VERSION 5.8 ;
BUSBITCHARS "[]" ;
DIVIDERCHAR "/" ;
UNITS
    DATABASE MICRONS 1000 ;
END UNITS

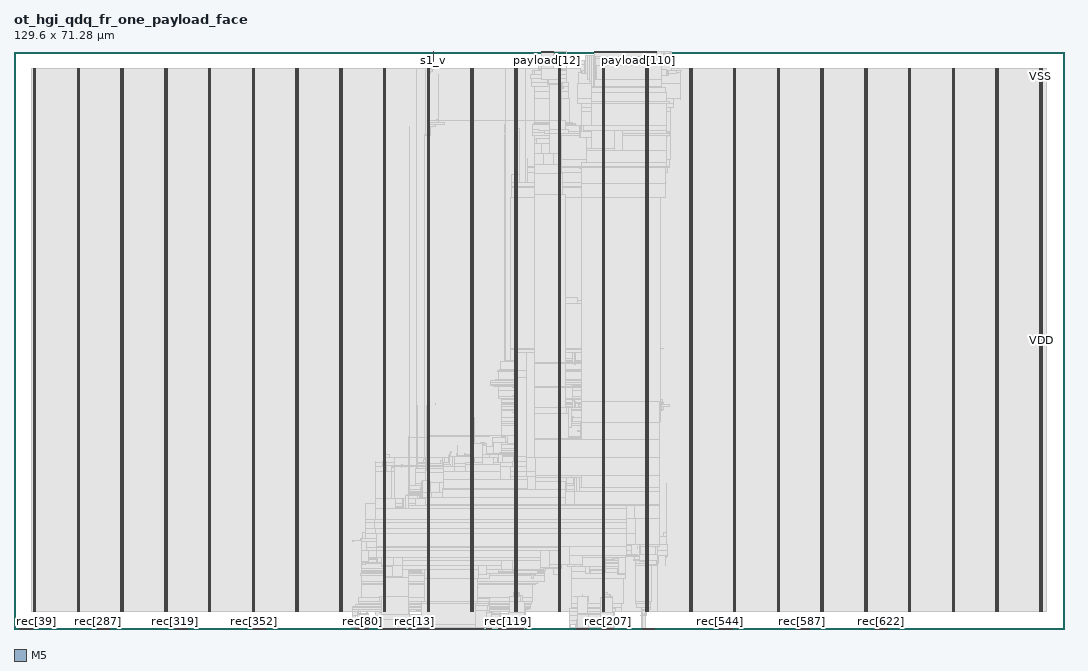
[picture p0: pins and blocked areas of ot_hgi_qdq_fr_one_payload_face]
MACRO ot_hgi_qdq_fr_one_payload_face
  FOREIGN ot_hgi_qdq_fr_one_payload_face 0 0 ;
  CLASS BLOCK ;
  SIZE 129.6 BY 71.28 ;
  PIN clk
    DIRECTION INPUT ;
    USE SIGNAL ;
    PORT
      LAYER M5 ;
        RECT  48.72 0 48.744 0.084 ;
    END
  END clk
  PIN nfault
    DIRECTION OUTPUT ;
    USE SIGNAL ;
    PORT
      LAYER M5 ;
        RECT  65.136 71.196 65.16 71.28 ;
    END
  END nfault
  PIN one_s1
    DIRECTION OUTPUT ;
    USE SIGNAL ;
    PORT
      LAYER M5 ;
        RECT  65.184 71.196 65.208 71.28 ;
    END
  END one_s1
  PIN payload[0]
    DIRECTION OUTPUT ;
    USE SIGNAL ;
    PORT
      LAYER M5 ;
        RECT  65.232 71.196 65.256 71.28 ;
    END
  END payload[0]
  PIN payload[100]
    DIRECTION OUTPUT ;
    USE SIGNAL ;
    PORT
      LAYER M5 ;
        RECT  76.56 71.196 76.584 71.28 ;
    END
  END payload[100]
  PIN payload[101]
    DIRECTION OUTPUT ;
    USE SIGNAL ;
    PORT
      LAYER M5 ;
        RECT  76.608 71.196 76.632 71.28 ;
    END
  END payload[101]
  PIN payload[102]
    DIRECTION OUTPUT ;
    USE SIGNAL ;
    PORT
      LAYER M5 ;
        RECT  76.656 71.196 76.68 71.28 ;
    END
  END payload[102]
  PIN payload[103]
    DIRECTION OUTPUT ;
    USE SIGNAL ;
    PORT
      LAYER M5 ;
        RECT  76.704 71.196 76.728 71.28 ;
    END
  END payload[103]
  PIN payload[104]
    DIRECTION OUTPUT ;
    USE SIGNAL ;
    PORT
      LAYER M5 ;
        RECT  76.752 71.196 76.776 71.28 ;
    END
  END payload[104]
  PIN payload[105]
    DIRECTION OUTPUT ;
    USE SIGNAL ;
    PORT
      LAYER M5 ;
        RECT  76.8 71.196 76.824 71.28 ;
    END
  END payload[105]
  PIN payload[106]
    DIRECTION OUTPUT ;
    USE SIGNAL ;
    PORT
      LAYER M5 ;
        RECT  76.848 71.196 76.872 71.28 ;
    END
  END payload[106]
  PIN payload[107]
    DIRECTION OUTPUT ;
    USE SIGNAL ;
    PORT
      LAYER M5 ;
        RECT  76.896 71.196 76.92 71.28 ;
    END
  END payload[107]
  PIN payload[108]
    DIRECTION OUTPUT ;
    USE SIGNAL ;
    PORT
      LAYER M5 ;
        RECT  76.944 71.196 76.968 71.28 ;
    END
  END payload[108]
  PIN payload[109]
    DIRECTION OUTPUT ;
    USE SIGNAL ;
    PORT
      LAYER M5 ;
        RECT  76.992 71.196 77.016 71.28 ;
    END
  END payload[109]
  PIN payload[10]
    DIRECTION OUTPUT ;
    USE SIGNAL ;
    PORT
      LAYER M5 ;
        RECT  65.712 71.196 65.736 71.28 ;
    END
  END payload[10]
  PIN payload[110]
    DIRECTION OUTPUT ;
    USE SIGNAL ;
    PORT
      LAYER M5 ;
        RECT  77.04 71.196 77.064 71.28 ;
    END
  END payload[110]
  PIN payload[111]
    DIRECTION OUTPUT ;
    USE SIGNAL ;
    PORT
      LAYER M5 ;
        RECT  77.088 71.196 77.112 71.28 ;
    END
  END payload[111]
  PIN payload[112]
    DIRECTION OUTPUT ;
    USE SIGNAL ;
    PORT
      LAYER M5 ;
        RECT  77.136 71.196 77.16 71.28 ;
    END
  END payload[112]
  PIN payload[113]
    DIRECTION OUTPUT ;
    USE SIGNAL ;
    PORT
      LAYER M5 ;
        RECT  77.184 71.196 77.208 71.28 ;
    END
  END payload[113]
  PIN payload[114]
    DIRECTION OUTPUT ;
    USE SIGNAL ;
    PORT
      LAYER M5 ;
        RECT  77.232 71.196 77.256 71.28 ;
    END
  END payload[114]
  PIN payload[115]
    DIRECTION OUTPUT ;
    USE SIGNAL ;
    PORT
      LAYER M5 ;
        RECT  77.28 71.196 77.304 71.28 ;
    END
  END payload[115]
  PIN payload[116]
    DIRECTION OUTPUT ;
    USE SIGNAL ;
    PORT
      LAYER M5 ;
        RECT  77.328 71.196 77.352 71.28 ;
    END
  END payload[116]
  PIN payload[117]
    DIRECTION OUTPUT ;
    USE SIGNAL ;
    PORT
      LAYER M5 ;
        RECT  77.376 71.196 77.4 71.28 ;
    END
  END payload[117]
  PIN payload[118]
    DIRECTION OUTPUT ;
    USE SIGNAL ;
    PORT
      LAYER M5 ;
        RECT  77.424 71.196 77.448 71.28 ;
    END
  END payload[118]
  PIN payload[119]
    DIRECTION OUTPUT ;
    USE SIGNAL ;
    PORT
      LAYER M5 ;
        RECT  77.472 71.196 77.496 71.28 ;
    END
  END payload[119]
  PIN payload[11]
    DIRECTION OUTPUT ;
    USE SIGNAL ;
    PORT
      LAYER M5 ;
        RECT  65.76 71.196 65.784 71.28 ;
    END
  END payload[11]
  PIN payload[120]
    DIRECTION OUTPUT ;
    USE SIGNAL ;
    PORT
      LAYER M5 ;
        RECT  77.52 71.196 77.544 71.28 ;
    END
  END payload[120]
  PIN payload[121]
    DIRECTION OUTPUT ;
    USE SIGNAL ;
    PORT
      LAYER M5 ;
        RECT  77.568 71.196 77.592 71.28 ;
    END
  END payload[121]
  PIN payload[122]
    DIRECTION OUTPUT ;
    USE SIGNAL ;
    PORT
      LAYER M5 ;
        RECT  77.616 71.196 77.64 71.28 ;
    END
  END payload[122]
  PIN payload[123]
    DIRECTION OUTPUT ;
    USE SIGNAL ;
    PORT
      LAYER M5 ;
        RECT  77.664 71.196 77.688 71.28 ;
    END
  END payload[123]
  PIN payload[124]
    DIRECTION OUTPUT ;
    USE SIGNAL ;
    PORT
      LAYER M5 ;
        RECT  77.712 71.196 77.736 71.28 ;
    END
  END payload[124]
  PIN payload[125]
    DIRECTION OUTPUT ;
    USE SIGNAL ;
    PORT
      LAYER M5 ;
        RECT  77.76 71.196 77.784 71.28 ;
    END
  END payload[125]
  PIN payload[126]
    DIRECTION OUTPUT ;
    USE SIGNAL ;
    PORT
      LAYER M5 ;
        RECT  74.736 71.196 74.76 71.28 ;
    END
  END payload[126]
  PIN payload[127]
    DIRECTION OUTPUT ;
    USE SIGNAL ;
    PORT
      LAYER M5 ;
        RECT  74.784 71.196 74.808 71.28 ;
    END
  END payload[127]
  PIN payload[128]
    DIRECTION OUTPUT ;
    USE SIGNAL ;
    PORT
      LAYER M5 ;
        RECT  74.832 71.196 74.856 71.28 ;
    END
  END payload[128]
  PIN payload[129]
    DIRECTION OUTPUT ;
    USE SIGNAL ;
    PORT
      LAYER M5 ;
        RECT  74.88 71.196 74.904 71.28 ;
    END
  END payload[129]
  PIN payload[12]
    DIRECTION OUTPUT ;
    USE SIGNAL ;
    PORT
      LAYER M5 ;
        RECT  65.808 71.196 65.832 71.28 ;
    END
  END payload[12]
  PIN payload[130]
    DIRECTION OUTPUT ;
    USE SIGNAL ;
    PORT
      LAYER M5 ;
        RECT  74.928 71.196 74.952 71.28 ;
    END
  END payload[130]
  PIN payload[131]
    DIRECTION OUTPUT ;
    USE SIGNAL ;
    PORT
      LAYER M5 ;
        RECT  74.976 71.196 75 71.28 ;
    END
  END payload[131]
  PIN payload[132]
    DIRECTION OUTPUT ;
    USE SIGNAL ;
    PORT
      LAYER M5 ;
        RECT  75.024 71.196 75.048 71.28 ;
    END
  END payload[132]
  PIN payload[133]
    DIRECTION OUTPUT ;
    USE SIGNAL ;
    PORT
      LAYER M5 ;
        RECT  75.072 71.196 75.096 71.28 ;
    END
  END payload[133]
  PIN payload[134]
    DIRECTION OUTPUT ;
    USE SIGNAL ;
    PORT
      LAYER M5 ;
        RECT  75.12 71.196 75.144 71.28 ;
    END
  END payload[134]
  PIN payload[135]
    DIRECTION OUTPUT ;
    USE SIGNAL ;
    PORT
      LAYER M5 ;
        RECT  75.168 71.196 75.192 71.28 ;
    END
  END payload[135]
  PIN payload[136]
    DIRECTION OUTPUT ;
    USE SIGNAL ;
    PORT
      LAYER M5 ;
        RECT  75.216 71.196 75.24 71.28 ;
    END
  END payload[136]
  PIN payload[137]
    DIRECTION OUTPUT ;
    USE SIGNAL ;
    PORT
      LAYER M5 ;
        RECT  75.264 71.196 75.288 71.28 ;
    END
  END payload[137]
  PIN payload[138]
    DIRECTION OUTPUT ;
    USE SIGNAL ;
    PORT
      LAYER M5 ;
        RECT  75.312 71.196 75.336 71.28 ;
    END
  END payload[138]
  PIN payload[139]
    DIRECTION OUTPUT ;
    USE SIGNAL ;
    PORT
      LAYER M5 ;
        RECT  75.36 71.196 75.384 71.28 ;
    END
  END payload[139]
  PIN payload[13]
    DIRECTION OUTPUT ;
    USE SIGNAL ;
    PORT
      LAYER M5 ;
        RECT  65.856 71.196 65.88 71.28 ;
    END
  END payload[13]
  PIN payload[140]
    DIRECTION OUTPUT ;
    USE SIGNAL ;
    PORT
      LAYER M5 ;
        RECT  75.408 71.196 75.432 71.28 ;
    END
  END payload[140]
  PIN payload[141]
    DIRECTION OUTPUT ;
    USE SIGNAL ;
    PORT
      LAYER M5 ;
        RECT  75.456 71.196 75.48 71.28 ;
    END
  END payload[141]
  PIN payload[142]
    DIRECTION OUTPUT ;
    USE SIGNAL ;
    PORT
      LAYER M5 ;
        RECT  75.504 71.196 75.528 71.28 ;
    END
  END payload[142]
  PIN payload[143]
    DIRECTION OUTPUT ;
    USE SIGNAL ;
    PORT
      LAYER M5 ;
        RECT  75.552 71.196 75.576 71.28 ;
    END
  END payload[143]
  PIN payload[144]
    DIRECTION OUTPUT ;
    USE SIGNAL ;
    PORT
      LAYER M5 ;
        RECT  75.6 71.196 75.624 71.28 ;
    END
  END payload[144]
  PIN payload[145]
    DIRECTION OUTPUT ;
    USE SIGNAL ;
    PORT
      LAYER M5 ;
        RECT  75.648 71.196 75.672 71.28 ;
    END
  END payload[145]
  PIN payload[146]
    DIRECTION OUTPUT ;
    USE SIGNAL ;
    PORT
      LAYER M5 ;
        RECT  75.696 71.196 75.72 71.28 ;
    END
  END payload[146]
  PIN payload[147]
    DIRECTION OUTPUT ;
    USE SIGNAL ;
    PORT
      LAYER M5 ;
        RECT  75.744 71.196 75.768 71.28 ;
    END
  END payload[147]
  PIN payload[148]
    DIRECTION OUTPUT ;
    USE SIGNAL ;
    PORT
      LAYER M5 ;
        RECT  75.792 71.196 75.816 71.28 ;
    END
  END payload[148]
  PIN payload[149]
    DIRECTION OUTPUT ;
    USE SIGNAL ;
    PORT
      LAYER M5 ;
        RECT  75.84 71.196 75.864 71.28 ;
    END
  END payload[149]
  PIN payload[14]
    DIRECTION OUTPUT ;
    USE SIGNAL ;
    PORT
      LAYER M5 ;
        RECT  65.904 71.196 65.928 71.28 ;
    END
  END payload[14]
  PIN payload[150]
    DIRECTION OUTPUT ;
    USE SIGNAL ;
    PORT
      LAYER M5 ;
        RECT  75.888 71.196 75.912 71.28 ;
    END
  END payload[150]
  PIN payload[151]
    DIRECTION OUTPUT ;
    USE SIGNAL ;
    PORT
      LAYER M5 ;
        RECT  75.936 71.196 75.96 71.28 ;
    END
  END payload[151]
  PIN payload[152]
    DIRECTION OUTPUT ;
    USE SIGNAL ;
    PORT
      LAYER M5 ;
        RECT  75.984 71.196 76.008 71.28 ;
    END
  END payload[152]
  PIN payload[153]
    DIRECTION OUTPUT ;
    USE SIGNAL ;
    PORT
      LAYER M5 ;
        RECT  76.032 71.196 76.056 71.28 ;
    END
  END payload[153]
  PIN payload[154]
    DIRECTION OUTPUT ;
    USE SIGNAL ;
    PORT
      LAYER M5 ;
        RECT  76.08 71.196 76.104 71.28 ;
    END
  END payload[154]
  PIN payload[155]
    DIRECTION OUTPUT ;
    USE SIGNAL ;
    PORT
      LAYER M5 ;
        RECT  76.128 71.196 76.152 71.28 ;
    END
  END payload[155]
  PIN payload[156]
    DIRECTION OUTPUT ;
    USE SIGNAL ;
    PORT
      LAYER M5 ;
        RECT  76.176 71.196 76.2 71.28 ;
    END
  END payload[156]
  PIN payload[157]
    DIRECTION OUTPUT ;
    USE SIGNAL ;
    PORT
      LAYER M5 ;
        RECT  76.224 71.196 76.248 71.28 ;
    END
  END payload[157]
  PIN payload[158]
    DIRECTION OUTPUT ;
    USE SIGNAL ;
    PORT
      LAYER M5 ;
        RECT  77.808 71.196 77.832 71.28 ;
    END
  END payload[158]
  PIN payload[159]
    DIRECTION OUTPUT ;
    USE SIGNAL ;
    PORT
      LAYER M5 ;
        RECT  77.856 71.196 77.88 71.28 ;
    END
  END payload[159]
  PIN payload[15]
    DIRECTION OUTPUT ;
    USE SIGNAL ;
    PORT
      LAYER M5 ;
        RECT  65.952 71.196 65.976 71.28 ;
    END
  END payload[15]
  PIN payload[160]
    DIRECTION OUTPUT ;
    USE SIGNAL ;
    PORT
      LAYER M5 ;
        RECT  77.904 71.196 77.928 71.28 ;
    END
  END payload[160]
  PIN payload[161]
    DIRECTION OUTPUT ;
    USE SIGNAL ;
    PORT
      LAYER M5 ;
        RECT  77.952 71.196 77.976 71.28 ;
    END
  END payload[161]
  PIN payload[162]
    DIRECTION OUTPUT ;
    USE SIGNAL ;
    PORT
      LAYER M5 ;
        RECT  78 71.196 78.024 71.28 ;
    END
  END payload[162]
  PIN payload[163]
    DIRECTION OUTPUT ;
    USE SIGNAL ;
    PORT
      LAYER M5 ;
        RECT  78.048 71.196 78.072 71.28 ;
    END
  END payload[163]
  PIN payload[164]
    DIRECTION OUTPUT ;
    USE SIGNAL ;
    PORT
      LAYER M5 ;
        RECT  78.096 71.196 78.12 71.28 ;
    END
  END payload[164]
  PIN payload[165]
    DIRECTION OUTPUT ;
    USE SIGNAL ;
    PORT
      LAYER M5 ;
        RECT  78.144 71.196 78.168 71.28 ;
    END
  END payload[165]
  PIN payload[166]
    DIRECTION OUTPUT ;
    USE SIGNAL ;
    PORT
      LAYER M5 ;
        RECT  78.192 71.196 78.216 71.28 ;
    END
  END payload[166]
  PIN payload[167]
    DIRECTION OUTPUT ;
    USE SIGNAL ;
    PORT
      LAYER M5 ;
        RECT  78.24 71.196 78.264 71.28 ;
    END
  END payload[167]
  PIN payload[168]
    DIRECTION OUTPUT ;
    USE SIGNAL ;
    PORT
      LAYER M5 ;
        RECT  78.288 71.196 78.312 71.28 ;
    END
  END payload[168]
  PIN payload[169]
    DIRECTION OUTPUT ;
    USE SIGNAL ;
    PORT
      LAYER M5 ;
        RECT  78.336 71.196 78.36 71.28 ;
    END
  END payload[169]
  PIN payload[16]
    DIRECTION OUTPUT ;
    USE SIGNAL ;
    PORT
      LAYER M5 ;
        RECT  66 71.196 66.024 71.28 ;
    END
  END payload[16]
  PIN payload[170]
    DIRECTION OUTPUT ;
    USE SIGNAL ;
    PORT
      LAYER M5 ;
        RECT  78.384 71.196 78.408 71.28 ;
    END
  END payload[170]
  PIN payload[171]
    DIRECTION OUTPUT ;
    USE SIGNAL ;
    PORT
      LAYER M5 ;
        RECT  78.432 71.196 78.456 71.28 ;
    END
  END payload[171]
  PIN payload[172]
    DIRECTION OUTPUT ;
    USE SIGNAL ;
    PORT
      LAYER M5 ;
        RECT  78.48 71.196 78.504 71.28 ;
    END
  END payload[172]
  PIN payload[173]
    DIRECTION OUTPUT ;
    USE SIGNAL ;
    PORT
      LAYER M5 ;
        RECT  78.528 71.196 78.552 71.28 ;
    END
  END payload[173]
  PIN payload[174]
    DIRECTION OUTPUT ;
    USE SIGNAL ;
    PORT
      LAYER M5 ;
        RECT  78.576 71.196 78.6 71.28 ;
    END
  END payload[174]
  PIN payload[175]
    DIRECTION OUTPUT ;
    USE SIGNAL ;
    PORT
      LAYER M5 ;
        RECT  78.624 71.196 78.648 71.28 ;
    END
  END payload[175]
  PIN payload[176]
    DIRECTION OUTPUT ;
    USE SIGNAL ;
    PORT
      LAYER M5 ;
        RECT  78.672 71.196 78.696 71.28 ;
    END
  END payload[176]
  PIN payload[177]
    DIRECTION OUTPUT ;
    USE SIGNAL ;
    PORT
      LAYER M5 ;
        RECT  78.72 71.196 78.744 71.28 ;
    END
  END payload[177]
  PIN payload[178]
    DIRECTION OUTPUT ;
    USE SIGNAL ;
    PORT
      LAYER M5 ;
        RECT  78.768 71.196 78.792 71.28 ;
    END
  END payload[178]
  PIN payload[179]
    DIRECTION OUTPUT ;
    USE SIGNAL ;
    PORT
      LAYER M5 ;
        RECT  78.816 71.196 78.84 71.28 ;
    END
  END payload[179]
  PIN payload[17]
    DIRECTION OUTPUT ;
    USE SIGNAL ;
    PORT
      LAYER M5 ;
        RECT  66.048 71.196 66.072 71.28 ;
    END
  END payload[17]
  PIN payload[180]
    DIRECTION OUTPUT ;
    USE SIGNAL ;
    PORT
      LAYER M5 ;
        RECT  78.864 71.196 78.888 71.28 ;
    END
  END payload[180]
  PIN payload[181]
    DIRECTION OUTPUT ;
    USE SIGNAL ;
    PORT
      LAYER M5 ;
        RECT  78.912 71.196 78.936 71.28 ;
    END
  END payload[181]
  PIN payload[182]
    DIRECTION OUTPUT ;
    USE SIGNAL ;
    PORT
      LAYER M5 ;
        RECT  78.96 71.196 78.984 71.28 ;
    END
  END payload[182]
  PIN payload[183]
    DIRECTION OUTPUT ;
    USE SIGNAL ;
    PORT
      LAYER M5 ;
        RECT  79.008 71.196 79.032 71.28 ;
    END
  END payload[183]
  PIN payload[184]
    DIRECTION OUTPUT ;
    USE SIGNAL ;
    PORT
      LAYER M5 ;
        RECT  79.056 71.196 79.08 71.28 ;
    END
  END payload[184]
  PIN payload[185]
    DIRECTION OUTPUT ;
    USE SIGNAL ;
    PORT
      LAYER M5 ;
        RECT  79.104 71.196 79.128 71.28 ;
    END
  END payload[185]
  PIN payload[186]
    DIRECTION OUTPUT ;
    USE SIGNAL ;
    PORT
      LAYER M5 ;
        RECT  79.152 71.196 79.176 71.28 ;
    END
  END payload[186]
  PIN payload[187]
    DIRECTION OUTPUT ;
    USE SIGNAL ;
    PORT
      LAYER M5 ;
        RECT  79.2 71.196 79.224 71.28 ;
    END
  END payload[187]
  PIN payload[188]
    DIRECTION OUTPUT ;
    USE SIGNAL ;
    PORT
      LAYER M5 ;
        RECT  79.248 71.196 79.272 71.28 ;
    END
  END payload[188]
  PIN payload[189]
    DIRECTION OUTPUT ;
    USE SIGNAL ;
    PORT
      LAYER M5 ;
        RECT  79.296 71.196 79.32 71.28 ;
    END
  END payload[189]
  PIN payload[18]
    DIRECTION OUTPUT ;
    USE SIGNAL ;
    PORT
      LAYER M5 ;
        RECT  66.096 71.196 66.12 71.28 ;
    END
  END payload[18]
  PIN payload[19]
    DIRECTION OUTPUT ;
    USE SIGNAL ;
    PORT
      LAYER M5 ;
        RECT  66.144 71.196 66.168 71.28 ;
    END
  END payload[19]
  PIN payload[1]
    DIRECTION OUTPUT ;
    USE SIGNAL ;
    PORT
      LAYER M5 ;
        RECT  65.28 71.196 65.304 71.28 ;
    END
  END payload[1]
  PIN payload[20]
    DIRECTION OUTPUT ;
    USE SIGNAL ;
    PORT
      LAYER M5 ;
        RECT  66.192 71.196 66.216 71.28 ;
    END
  END payload[20]
  PIN payload[21]
    DIRECTION OUTPUT ;
    USE SIGNAL ;
    PORT
      LAYER M5 ;
        RECT  66.24 71.196 66.264 71.28 ;
    END
  END payload[21]
  PIN payload[22]
    DIRECTION OUTPUT ;
    USE SIGNAL ;
    PORT
      LAYER M5 ;
        RECT  66.288 71.196 66.312 71.28 ;
    END
  END payload[22]
  PIN payload[23]
    DIRECTION OUTPUT ;
    USE SIGNAL ;
    PORT
      LAYER M5 ;
        RECT  66.336 71.196 66.36 71.28 ;
    END
  END payload[23]
  PIN payload[24]
    DIRECTION OUTPUT ;
    USE SIGNAL ;
    PORT
      LAYER M5 ;
        RECT  66.384 71.196 66.408 71.28 ;
    END
  END payload[24]
  PIN payload[25]
    DIRECTION OUTPUT ;
    USE SIGNAL ;
    PORT
      LAYER M5 ;
        RECT  66.432 71.196 66.456 71.28 ;
    END
  END payload[25]
  PIN payload[26]
    DIRECTION OUTPUT ;
    USE SIGNAL ;
    PORT
      LAYER M5 ;
        RECT  66.48 71.196 66.504 71.28 ;
    END
  END payload[26]
  PIN payload[27]
    DIRECTION OUTPUT ;
    USE SIGNAL ;
    PORT
      LAYER M5 ;
        RECT  66.528 71.196 66.552 71.28 ;
    END
  END payload[27]
  PIN payload[28]
    DIRECTION OUTPUT ;
    USE SIGNAL ;
    PORT
      LAYER M5 ;
        RECT  66.576 71.196 66.6 71.28 ;
    END
  END payload[28]
  PIN payload[29]
    DIRECTION OUTPUT ;
    USE SIGNAL ;
    PORT
      LAYER M5 ;
        RECT  66.624 71.196 66.648 71.28 ;
    END
  END payload[29]
  PIN payload[2]
    DIRECTION OUTPUT ;
    USE SIGNAL ;
    PORT
      LAYER M5 ;
        RECT  65.328 71.196 65.352 71.28 ;
    END
  END payload[2]
  PIN payload[30]
    DIRECTION OUTPUT ;
    USE SIGNAL ;
    PORT
      LAYER M5 ;
        RECT  71.664 71.196 71.688 71.28 ;
    END
  END payload[30]
  PIN payload[31]
    DIRECTION OUTPUT ;
    USE SIGNAL ;
    PORT
      LAYER M5 ;
        RECT  71.712 71.196 71.736 71.28 ;
    END
  END payload[31]
  PIN payload[32]
    DIRECTION OUTPUT ;
    USE SIGNAL ;
    PORT
      LAYER M5 ;
        RECT  71.76 71.196 71.784 71.28 ;
    END
  END payload[32]
  PIN payload[33]
    DIRECTION OUTPUT ;
    USE SIGNAL ;
    PORT
      LAYER M5 ;
        RECT  71.808 71.196 71.832 71.28 ;
    END
  END payload[33]
  PIN payload[34]
    DIRECTION OUTPUT ;
    USE SIGNAL ;
    PORT
      LAYER M5 ;
        RECT  71.856 71.196 71.88 71.28 ;
    END
  END payload[34]
  PIN payload[35]
    DIRECTION OUTPUT ;
    USE SIGNAL ;
    PORT
      LAYER M5 ;
        RECT  71.904 71.196 71.928 71.28 ;
    END
  END payload[35]
  PIN payload[36]
    DIRECTION OUTPUT ;
    USE SIGNAL ;
    PORT
      LAYER M5 ;
        RECT  71.952 71.196 71.976 71.28 ;
    END
  END payload[36]
  PIN payload[37]
    DIRECTION OUTPUT ;
    USE SIGNAL ;
    PORT
      LAYER M5 ;
        RECT  72 71.196 72.024 71.28 ;
    END
  END payload[37]
  PIN payload[38]
    DIRECTION OUTPUT ;
    USE SIGNAL ;
    PORT
      LAYER M5 ;
        RECT  72.048 71.196 72.072 71.28 ;
    END
  END payload[38]
  PIN payload[39]
    DIRECTION OUTPUT ;
    USE SIGNAL ;
    PORT
      LAYER M5 ;
        RECT  72.096 71.196 72.12 71.28 ;
    END
  END payload[39]
  PIN payload[3]
    DIRECTION OUTPUT ;
    USE SIGNAL ;
    PORT
      LAYER M5 ;
        RECT  65.376 71.196 65.4 71.28 ;
    END
  END payload[3]
  PIN payload[40]
    DIRECTION OUTPUT ;
    USE SIGNAL ;
    PORT
      LAYER M5 ;
        RECT  72.144 71.196 72.168 71.28 ;
    END
  END payload[40]
  PIN payload[41]
    DIRECTION OUTPUT ;
    USE SIGNAL ;
    PORT
      LAYER M5 ;
        RECT  72.192 71.196 72.216 71.28 ;
    END
  END payload[41]
  PIN payload[42]
    DIRECTION OUTPUT ;
    USE SIGNAL ;
    PORT
      LAYER M5 ;
        RECT  72.24 71.196 72.264 71.28 ;
    END
  END payload[42]
  PIN payload[43]
    DIRECTION OUTPUT ;
    USE SIGNAL ;
    PORT
      LAYER M5 ;
        RECT  72.288 71.196 72.312 71.28 ;
    END
  END payload[43]
  PIN payload[44]
    DIRECTION OUTPUT ;
    USE SIGNAL ;
    PORT
      LAYER M5 ;
        RECT  72.336 71.196 72.36 71.28 ;
    END
  END payload[44]
  PIN payload[45]
    DIRECTION OUTPUT ;
    USE SIGNAL ;
    PORT
      LAYER M5 ;
        RECT  72.384 71.196 72.408 71.28 ;
    END
  END payload[45]
  PIN payload[46]
    DIRECTION OUTPUT ;
    USE SIGNAL ;
    PORT
      LAYER M5 ;
        RECT  72.432 71.196 72.456 71.28 ;
    END
  END payload[46]
  PIN payload[47]
    DIRECTION OUTPUT ;
    USE SIGNAL ;
    PORT
      LAYER M5 ;
        RECT  72.48 71.196 72.504 71.28 ;
    END
  END payload[47]
  PIN payload[48]
    DIRECTION OUTPUT ;
    USE SIGNAL ;
    PORT
      LAYER M5 ;
        RECT  72.528 71.196 72.552 71.28 ;
    END
  END payload[48]
  PIN payload[49]
    DIRECTION OUTPUT ;
    USE SIGNAL ;
    PORT
      LAYER M5 ;
        RECT  72.576 71.196 72.6 71.28 ;
    END
  END payload[49]
  PIN payload[4]
    DIRECTION OUTPUT ;
    USE SIGNAL ;
    PORT
      LAYER M5 ;
        RECT  65.424 71.196 65.448 71.28 ;
    END
  END payload[4]
  PIN payload[50]
    DIRECTION OUTPUT ;
    USE SIGNAL ;
    PORT
      LAYER M5 ;
        RECT  72.624 71.196 72.648 71.28 ;
    END
  END payload[50]
  PIN payload[51]
    DIRECTION OUTPUT ;
    USE SIGNAL ;
    PORT
      LAYER M5 ;
        RECT  72.672 71.196 72.696 71.28 ;
    END
  END payload[51]
  PIN payload[52]
    DIRECTION OUTPUT ;
    USE SIGNAL ;
    PORT
      LAYER M5 ;
        RECT  72.72 71.196 72.744 71.28 ;
    END
  END payload[52]
  PIN payload[53]
    DIRECTION OUTPUT ;
    USE SIGNAL ;
    PORT
      LAYER M5 ;
        RECT  72.768 71.196 72.792 71.28 ;
    END
  END payload[53]
  PIN payload[54]
    DIRECTION OUTPUT ;
    USE SIGNAL ;
    PORT
      LAYER M5 ;
        RECT  72.816 71.196 72.84 71.28 ;
    END
  END payload[54]
  PIN payload[55]
    DIRECTION OUTPUT ;
    USE SIGNAL ;
    PORT
      LAYER M5 ;
        RECT  72.864 71.196 72.888 71.28 ;
    END
  END payload[55]
  PIN payload[56]
    DIRECTION OUTPUT ;
    USE SIGNAL ;
    PORT
      LAYER M5 ;
        RECT  72.912 71.196 72.936 71.28 ;
    END
  END payload[56]
  PIN payload[57]
    DIRECTION OUTPUT ;
    USE SIGNAL ;
    PORT
      LAYER M5 ;
        RECT  72.96 71.196 72.984 71.28 ;
    END
  END payload[57]
  PIN payload[58]
    DIRECTION OUTPUT ;
    USE SIGNAL ;
    PORT
      LAYER M5 ;
        RECT  73.008 71.196 73.032 71.28 ;
    END
  END payload[58]
  PIN payload[59]
    DIRECTION OUTPUT ;
    USE SIGNAL ;
    PORT
      LAYER M5 ;
        RECT  73.056 71.196 73.08 71.28 ;
    END
  END payload[59]
  PIN payload[5]
    DIRECTION OUTPUT ;
    USE SIGNAL ;
    PORT
      LAYER M5 ;
        RECT  65.472 71.196 65.496 71.28 ;
    END
  END payload[5]
  PIN payload[60]
    DIRECTION OUTPUT ;
    USE SIGNAL ;
    PORT
      LAYER M5 ;
        RECT  73.104 71.196 73.128 71.28 ;
    END
  END payload[60]
  PIN payload[61]
    DIRECTION OUTPUT ;
    USE SIGNAL ;
    PORT
      LAYER M5 ;
        RECT  73.152 71.196 73.176 71.28 ;
    END
  END payload[61]
  PIN payload[62]
    DIRECTION OUTPUT ;
    USE SIGNAL ;
    PORT
      LAYER M5 ;
        RECT  73.2 71.196 73.224 71.28 ;
    END
  END payload[62]
  PIN payload[63]
    DIRECTION OUTPUT ;
    USE SIGNAL ;
    PORT
      LAYER M5 ;
        RECT  73.248 71.196 73.272 71.28 ;
    END
  END payload[63]
  PIN payload[64]
    DIRECTION OUTPUT ;
    USE SIGNAL ;
    PORT
      LAYER M5 ;
        RECT  73.296 71.196 73.32 71.28 ;
    END
  END payload[64]
  PIN payload[65]
    DIRECTION OUTPUT ;
    USE SIGNAL ;
    PORT
      LAYER M5 ;
        RECT  73.344 71.196 73.368 71.28 ;
    END
  END payload[65]
  PIN payload[66]
    DIRECTION OUTPUT ;
    USE SIGNAL ;
    PORT
      LAYER M5 ;
        RECT  73.392 71.196 73.416 71.28 ;
    END
  END payload[66]
  PIN payload[67]
    DIRECTION OUTPUT ;
    USE SIGNAL ;
    PORT
      LAYER M5 ;
        RECT  73.44 71.196 73.464 71.28 ;
    END
  END payload[67]
  PIN payload[68]
    DIRECTION OUTPUT ;
    USE SIGNAL ;
    PORT
      LAYER M5 ;
        RECT  73.488 71.196 73.512 71.28 ;
    END
  END payload[68]
  PIN payload[69]
    DIRECTION OUTPUT ;
    USE SIGNAL ;
    PORT
      LAYER M5 ;
        RECT  73.536 71.196 73.56 71.28 ;
    END
  END payload[69]
  PIN payload[6]
    DIRECTION OUTPUT ;
    USE SIGNAL ;
    PORT
      LAYER M5 ;
        RECT  65.52 71.196 65.544 71.28 ;
    END
  END payload[6]
  PIN payload[70]
    DIRECTION OUTPUT ;
    USE SIGNAL ;
    PORT
      LAYER M5 ;
        RECT  73.584 71.196 73.608 71.28 ;
    END
  END payload[70]
  PIN payload[71]
    DIRECTION OUTPUT ;
    USE SIGNAL ;
    PORT
      LAYER M5 ;
        RECT  73.632 71.196 73.656 71.28 ;
    END
  END payload[71]
  PIN payload[72]
    DIRECTION OUTPUT ;
    USE SIGNAL ;
    PORT
      LAYER M5 ;
        RECT  73.68 71.196 73.704 71.28 ;
    END
  END payload[72]
  PIN payload[73]
    DIRECTION OUTPUT ;
    USE SIGNAL ;
    PORT
      LAYER M5 ;
        RECT  73.728 71.196 73.752 71.28 ;
    END
  END payload[73]
  PIN payload[74]
    DIRECTION OUTPUT ;
    USE SIGNAL ;
    PORT
      LAYER M5 ;
        RECT  73.776 71.196 73.8 71.28 ;
    END
  END payload[74]
  PIN payload[75]
    DIRECTION OUTPUT ;
    USE SIGNAL ;
    PORT
      LAYER M5 ;
        RECT  73.824 71.196 73.848 71.28 ;
    END
  END payload[75]
  PIN payload[76]
    DIRECTION OUTPUT ;
    USE SIGNAL ;
    PORT
      LAYER M5 ;
        RECT  73.872 71.196 73.896 71.28 ;
    END
  END payload[76]
  PIN payload[77]
    DIRECTION OUTPUT ;
    USE SIGNAL ;
    PORT
      LAYER M5 ;
        RECT  73.92 71.196 73.944 71.28 ;
    END
  END payload[77]
  PIN payload[78]
    DIRECTION OUTPUT ;
    USE SIGNAL ;
    PORT
      LAYER M5 ;
        RECT  73.968 71.196 73.992 71.28 ;
    END
  END payload[78]
  PIN payload[79]
    DIRECTION OUTPUT ;
    USE SIGNAL ;
    PORT
      LAYER M5 ;
        RECT  74.016 71.196 74.04 71.28 ;
    END
  END payload[79]
  PIN payload[7]
    DIRECTION OUTPUT ;
    USE SIGNAL ;
    PORT
      LAYER M5 ;
        RECT  65.568 71.196 65.592 71.28 ;
    END
  END payload[7]
  PIN payload[80]
    DIRECTION OUTPUT ;
    USE SIGNAL ;
    PORT
      LAYER M5 ;
        RECT  74.064 71.196 74.088 71.28 ;
    END
  END payload[80]
  PIN payload[81]
    DIRECTION OUTPUT ;
    USE SIGNAL ;
    PORT
      LAYER M5 ;
        RECT  74.112 71.196 74.136 71.28 ;
    END
  END payload[81]
  PIN payload[82]
    DIRECTION OUTPUT ;
    USE SIGNAL ;
    PORT
      LAYER M5 ;
        RECT  74.16 71.196 74.184 71.28 ;
    END
  END payload[82]
  PIN payload[83]
    DIRECTION OUTPUT ;
    USE SIGNAL ;
    PORT
      LAYER M5 ;
        RECT  74.208 71.196 74.232 71.28 ;
    END
  END payload[83]
  PIN payload[84]
    DIRECTION OUTPUT ;
    USE SIGNAL ;
    PORT
      LAYER M5 ;
        RECT  74.256 71.196 74.28 71.28 ;
    END
  END payload[84]
  PIN payload[85]
    DIRECTION OUTPUT ;
    USE SIGNAL ;
    PORT
      LAYER M5 ;
        RECT  74.304 71.196 74.328 71.28 ;
    END
  END payload[85]
  PIN payload[86]
    DIRECTION OUTPUT ;
    USE SIGNAL ;
    PORT
      LAYER M5 ;
        RECT  74.352 71.196 74.376 71.28 ;
    END
  END payload[86]
  PIN payload[87]
    DIRECTION OUTPUT ;
    USE SIGNAL ;
    PORT
      LAYER M5 ;
        RECT  74.4 71.196 74.424 71.28 ;
    END
  END payload[87]
  PIN payload[88]
    DIRECTION OUTPUT ;
    USE SIGNAL ;
    PORT
      LAYER M5 ;
        RECT  74.448 71.196 74.472 71.28 ;
    END
  END payload[88]
  PIN payload[89]
    DIRECTION OUTPUT ;
    USE SIGNAL ;
    PORT
      LAYER M5 ;
        RECT  74.496 71.196 74.52 71.28 ;
    END
  END payload[89]
  PIN payload[8]
    DIRECTION OUTPUT ;
    USE SIGNAL ;
    PORT
      LAYER M5 ;
        RECT  65.616 71.196 65.64 71.28 ;
    END
  END payload[8]
  PIN payload[90]
    DIRECTION OUTPUT ;
    USE SIGNAL ;
    PORT
      LAYER M5 ;
        RECT  74.544 71.196 74.568 71.28 ;
    END
  END payload[90]
  PIN payload[91]
    DIRECTION OUTPUT ;
    USE SIGNAL ;
    PORT
      LAYER M5 ;
        RECT  74.592 71.196 74.616 71.28 ;
    END
  END payload[91]
  PIN payload[92]
    DIRECTION OUTPUT ;
    USE SIGNAL ;
    PORT
      LAYER M5 ;
        RECT  74.64 71.196 74.664 71.28 ;
    END
  END payload[92]
  PIN payload[93]
    DIRECTION OUTPUT ;
    USE SIGNAL ;
    PORT
      LAYER M5 ;
        RECT  74.688 71.196 74.712 71.28 ;
    END
  END payload[93]
  PIN payload[94]
    DIRECTION OUTPUT ;
    USE SIGNAL ;
    PORT
      LAYER M5 ;
        RECT  76.272 71.196 76.296 71.28 ;
    END
  END payload[94]
  PIN payload[95]
    DIRECTION OUTPUT ;
    USE SIGNAL ;
    PORT
      LAYER M5 ;
        RECT  76.32 71.196 76.344 71.28 ;
    END
  END payload[95]
  PIN payload[96]
    DIRECTION OUTPUT ;
    USE SIGNAL ;
    PORT
      LAYER M5 ;
        RECT  76.368 71.196 76.392 71.28 ;
    END
  END payload[96]
  PIN payload[97]
    DIRECTION OUTPUT ;
    USE SIGNAL ;
    PORT
      LAYER M5 ;
        RECT  76.416 71.196 76.44 71.28 ;
    END
  END payload[97]
  PIN payload[98]
    DIRECTION OUTPUT ;
    USE SIGNAL ;
    PORT
      LAYER M5 ;
        RECT  76.464 71.196 76.488 71.28 ;
    END
  END payload[98]
  PIN payload[99]
    DIRECTION OUTPUT ;
    USE SIGNAL ;
    PORT
      LAYER M5 ;
        RECT  76.512 71.196 76.536 71.28 ;
    END
  END payload[99]
  PIN payload[9]
    DIRECTION OUTPUT ;
    USE SIGNAL ;
    PORT
      LAYER M5 ;
        RECT  65.664 71.196 65.688 71.28 ;
    END
  END payload[9]
  PIN rec[0]
    DIRECTION INPUT ;
    USE SIGNAL ;
    PORT
      LAYER M5 ;
        RECT  48.768 0 48.792 0.084 ;
    END
  END rec[0]
  PIN rec[100]
    DIRECTION INPUT ;
    USE SIGNAL ;
    PORT
      LAYER M5 ;
        RECT  60.096 0 60.12 0.084 ;
    END
  END rec[100]
  PIN rec[101]
    DIRECTION INPUT ;
    USE SIGNAL ;
    PORT
      LAYER M5 ;
        RECT  60.144 0 60.168 0.084 ;
    END
  END rec[101]
  PIN rec[102]
    DIRECTION INPUT ;
    USE SIGNAL ;
    PORT
      LAYER M5 ;
        RECT  60.192 0 60.216 0.084 ;
    END
  END rec[102]
  PIN rec[103]
    DIRECTION INPUT ;
    USE SIGNAL ;
    PORT
      LAYER M5 ;
        RECT  60.24 0 60.264 0.084 ;
    END
  END rec[103]
  PIN rec[104]
    DIRECTION INPUT ;
    USE SIGNAL ;
    PORT
      LAYER M5 ;
        RECT  60.288 0 60.312 0.084 ;
    END
  END rec[104]
  PIN rec[105]
    DIRECTION INPUT ;
    USE SIGNAL ;
    PORT
      LAYER M5 ;
        RECT  60.336 0 60.36 0.084 ;
    END
  END rec[105]
  PIN rec[106]
    DIRECTION INPUT ;
    USE SIGNAL ;
    PORT
      LAYER M5 ;
        RECT  60.384 0 60.408 0.084 ;
    END
  END rec[106]
  PIN rec[107]
    DIRECTION INPUT ;
    USE SIGNAL ;
    PORT
      LAYER M5 ;
        RECT  60.432 0 60.456 0.084 ;
    END
  END rec[107]
  PIN rec[108]
    DIRECTION INPUT ;
    USE SIGNAL ;
    PORT
      LAYER M5 ;
        RECT  60.48 0 60.504 0.084 ;
    END
  END rec[108]
  PIN rec[109]
    DIRECTION INPUT ;
    USE SIGNAL ;
    PORT
      LAYER M5 ;
        RECT  60.528 0 60.552 0.084 ;
    END
  END rec[109]
  PIN rec[10]
    DIRECTION INPUT ;
    USE SIGNAL ;
    PORT
      LAYER M5 ;
        RECT  49.248 0 49.272 0.084 ;
    END
  END rec[10]
  PIN rec[110]
    DIRECTION INPUT ;
    USE SIGNAL ;
    PORT
      LAYER M5 ;
        RECT  60.576 0 60.6 0.084 ;
    END
  END rec[110]
  PIN rec[111]
    DIRECTION INPUT ;
    USE SIGNAL ;
    PORT
      LAYER M5 ;
        RECT  60.624 0 60.648 0.084 ;
    END
  END rec[111]
  PIN rec[112]
    DIRECTION INPUT ;
    USE SIGNAL ;
    PORT
      LAYER M5 ;
        RECT  60.672 0 60.696 0.084 ;
    END
  END rec[112]
  PIN rec[113]
    DIRECTION INPUT ;
    USE SIGNAL ;
    PORT
      LAYER M5 ;
        RECT  60.72 0 60.744 0.084 ;
    END
  END rec[113]
  PIN rec[114]
    DIRECTION INPUT ;
    USE SIGNAL ;
    PORT
      LAYER M5 ;
        RECT  60.768 0 60.792 0.084 ;
    END
  END rec[114]
  PIN rec[115]
    DIRECTION INPUT ;
    USE SIGNAL ;
    PORT
      LAYER M5 ;
        RECT  60.816 0 60.84 0.084 ;
    END
  END rec[115]
  PIN rec[116]
    DIRECTION INPUT ;
    USE SIGNAL ;
    PORT
      LAYER M5 ;
        RECT  60.864 0 60.888 0.084 ;
    END
  END rec[116]
  PIN rec[117]
    DIRECTION INPUT ;
    USE SIGNAL ;
    PORT
      LAYER M5 ;
        RECT  60.912 0 60.936 0.084 ;
    END
  END rec[117]
  PIN rec[118]
    DIRECTION INPUT ;
    USE SIGNAL ;
    PORT
      LAYER M5 ;
        RECT  60.96 0 60.984 0.084 ;
    END
  END rec[118]
  PIN rec[119]
    DIRECTION INPUT ;
    USE SIGNAL ;
    PORT
      LAYER M5 ;
        RECT  61.008 0 61.032 0.084 ;
    END
  END rec[119]
  PIN rec[11]
    DIRECTION INPUT ;
    USE SIGNAL ;
    PORT
      LAYER M5 ;
        RECT  49.296 0 49.32 0.084 ;
    END
  END rec[11]
  PIN rec[120]
    DIRECTION INPUT ;
    USE SIGNAL ;
    PORT
      LAYER M5 ;
        RECT  61.056 0 61.08 0.084 ;
    END
  END rec[120]
  PIN rec[121]
    DIRECTION INPUT ;
    USE SIGNAL ;
    PORT
      LAYER M5 ;
        RECT  61.104 0 61.128 0.084 ;
    END
  END rec[121]
  PIN rec[122]
    DIRECTION INPUT ;
    USE SIGNAL ;
    PORT
      LAYER M5 ;
        RECT  61.152 0 61.176 0.084 ;
    END
  END rec[122]
  PIN rec[123]
    DIRECTION INPUT ;
    USE SIGNAL ;
    PORT
      LAYER M5 ;
        RECT  61.2 0 61.224 0.084 ;
    END
  END rec[123]
  PIN rec[124]
    DIRECTION INPUT ;
    USE SIGNAL ;
    PORT
      LAYER M5 ;
        RECT  61.248 0 61.272 0.084 ;
    END
  END rec[124]
  PIN rec[125]
    DIRECTION INPUT ;
    USE SIGNAL ;
    PORT
      LAYER M5 ;
        RECT  61.296 0 61.32 0.084 ;
    END
  END rec[125]
  PIN rec[126]
    DIRECTION INPUT ;
    USE SIGNAL ;
    PORT
      LAYER M5 ;
        RECT  61.344 0 61.368 0.084 ;
    END
  END rec[126]
  PIN rec[127]
    DIRECTION INPUT ;
    USE SIGNAL ;
    PORT
      LAYER M5 ;
        RECT  50.256 0 50.28 0.084 ;
    END
  END rec[127]
  PIN rec[128]
    DIRECTION INPUT ;
    USE SIGNAL ;
    PORT
      LAYER M5 ;
        RECT  50.304 0 50.328 0.084 ;
    END
  END rec[128]
  PIN rec[129]
    DIRECTION INPUT ;
    USE SIGNAL ;
    PORT
      LAYER M5 ;
        RECT  50.352 0 50.376 0.084 ;
    END
  END rec[129]
  PIN rec[12]
    DIRECTION INPUT ;
    USE SIGNAL ;
    PORT
      LAYER M5 ;
        RECT  49.344 0 49.368 0.084 ;
    END
  END rec[12]
  PIN rec[130]
    DIRECTION INPUT ;
    USE SIGNAL ;
    PORT
      LAYER M5 ;
        RECT  50.4 0 50.424 0.084 ;
    END
  END rec[130]
  PIN rec[131]
    DIRECTION INPUT ;
    USE SIGNAL ;
    PORT
      LAYER M5 ;
        RECT  50.448 0 50.472 0.084 ;
    END
  END rec[131]
  PIN rec[132]
    DIRECTION INPUT ;
    USE SIGNAL ;
    PORT
      LAYER M5 ;
        RECT  50.496 0 50.52 0.084 ;
    END
  END rec[132]
  PIN rec[133]
    DIRECTION INPUT ;
    USE SIGNAL ;
    PORT
      LAYER M5 ;
        RECT  50.544 0 50.568 0.084 ;
    END
  END rec[133]
  PIN rec[134]
    DIRECTION INPUT ;
    USE SIGNAL ;
    PORT
      LAYER M5 ;
        RECT  50.592 0 50.616 0.084 ;
    END
  END rec[134]
  PIN rec[135]
    DIRECTION INPUT ;
    USE SIGNAL ;
    PORT
      LAYER M5 ;
        RECT  50.64 0 50.664 0.084 ;
    END
  END rec[135]
  PIN rec[136]
    DIRECTION INPUT ;
    USE SIGNAL ;
    PORT
      LAYER M5 ;
        RECT  50.688 0 50.712 0.084 ;
    END
  END rec[136]
  PIN rec[137]
    DIRECTION INPUT ;
    USE SIGNAL ;
    PORT
      LAYER M5 ;
        RECT  50.736 0 50.76 0.084 ;
    END
  END rec[137]
  PIN rec[138]
    DIRECTION INPUT ;
    USE SIGNAL ;
    PORT
      LAYER M5 ;
        RECT  50.784 0 50.808 0.084 ;
    END
  END rec[138]
  PIN rec[139]
    DIRECTION INPUT ;
    USE SIGNAL ;
    PORT
      LAYER M5 ;
        RECT  50.832 0 50.856 0.084 ;
    END
  END rec[139]
  PIN rec[13]
    DIRECTION INPUT ;
    USE SIGNAL ;
    PORT
      LAYER M5 ;
        RECT  49.392 0 49.416 0.084 ;
    END
  END rec[13]
  PIN rec[140]
    DIRECTION INPUT ;
    USE SIGNAL ;
    PORT
      LAYER M5 ;
        RECT  50.88 0 50.904 0.084 ;
    END
  END rec[140]
  PIN rec[141]
    DIRECTION INPUT ;
    USE SIGNAL ;
    PORT
      LAYER M5 ;
        RECT  50.928 0 50.952 0.084 ;
    END
  END rec[141]
  PIN rec[142]
    DIRECTION INPUT ;
    USE SIGNAL ;
    PORT
      LAYER M5 ;
        RECT  50.976 0 51 0.084 ;
    END
  END rec[142]
  PIN rec[143]
    DIRECTION INPUT ;
    USE SIGNAL ;
    PORT
      LAYER M5 ;
        RECT  51.024 0 51.048 0.084 ;
    END
  END rec[143]
  PIN rec[144]
    DIRECTION INPUT ;
    USE SIGNAL ;
    PORT
      LAYER M5 ;
        RECT  51.072 0 51.096 0.084 ;
    END
  END rec[144]
  PIN rec[145]
    DIRECTION INPUT ;
    USE SIGNAL ;
    PORT
      LAYER M5 ;
        RECT  51.12 0 51.144 0.084 ;
    END
  END rec[145]
  PIN rec[146]
    DIRECTION INPUT ;
    USE SIGNAL ;
    PORT
      LAYER M5 ;
        RECT  51.168 0 51.192 0.084 ;
    END
  END rec[146]
  PIN rec[147]
    DIRECTION INPUT ;
    USE SIGNAL ;
    PORT
      LAYER M5 ;
        RECT  51.216 0 51.24 0.084 ;
    END
  END rec[147]
  PIN rec[148]
    DIRECTION INPUT ;
    USE SIGNAL ;
    PORT
      LAYER M5 ;
        RECT  51.264 0 51.288 0.084 ;
    END
  END rec[148]
  PIN rec[149]
    DIRECTION INPUT ;
    USE SIGNAL ;
    PORT
      LAYER M5 ;
        RECT  51.312 0 51.336 0.084 ;
    END
  END rec[149]
  PIN rec[14]
    DIRECTION INPUT ;
    USE SIGNAL ;
    PORT
      LAYER M5 ;
        RECT  49.44 0 49.464 0.084 ;
    END
  END rec[14]
  PIN rec[150]
    DIRECTION INPUT ;
    USE SIGNAL ;
    PORT
      LAYER M5 ;
        RECT  51.36 0 51.384 0.084 ;
    END
  END rec[150]
  PIN rec[151]
    DIRECTION INPUT ;
    USE SIGNAL ;
    PORT
      LAYER M5 ;
        RECT  51.408 0 51.432 0.084 ;
    END
  END rec[151]
  PIN rec[152]
    DIRECTION INPUT ;
    USE SIGNAL ;
    PORT
      LAYER M5 ;
        RECT  51.456 0 51.48 0.084 ;
    END
  END rec[152]
  PIN rec[153]
    DIRECTION INPUT ;
    USE SIGNAL ;
    PORT
      LAYER M5 ;
        RECT  51.504 0 51.528 0.084 ;
    END
  END rec[153]
  PIN rec[154]
    DIRECTION INPUT ;
    USE SIGNAL ;
    PORT
      LAYER M5 ;
        RECT  51.552 0 51.576 0.084 ;
    END
  END rec[154]
  PIN rec[155]
    DIRECTION INPUT ;
    USE SIGNAL ;
    PORT
      LAYER M5 ;
        RECT  51.6 0 51.624 0.084 ;
    END
  END rec[155]
  PIN rec[156]
    DIRECTION INPUT ;
    USE SIGNAL ;
    PORT
      LAYER M5 ;
        RECT  51.648 0 51.672 0.084 ;
    END
  END rec[156]
  PIN rec[157]
    DIRECTION INPUT ;
    USE SIGNAL ;
    PORT
      LAYER M5 ;
        RECT  51.696 0 51.72 0.084 ;
    END
  END rec[157]
  PIN rec[158]
    DIRECTION INPUT ;
    USE SIGNAL ;
    PORT
      LAYER M5 ;
        RECT  51.744 0 51.768 0.084 ;
    END
  END rec[158]
  PIN rec[159]
    DIRECTION INPUT ;
    USE SIGNAL ;
    PORT
      LAYER M5 ;
        RECT  51.792 0 51.816 0.084 ;
    END
  END rec[159]
  PIN rec[15]
    DIRECTION INPUT ;
    USE SIGNAL ;
    PORT
      LAYER M5 ;
        RECT  49.488 0 49.512 0.084 ;
    END
  END rec[15]
  PIN rec[160]
    DIRECTION INPUT ;
    USE SIGNAL ;
    PORT
      LAYER M5 ;
        RECT  51.84 0 51.864 0.084 ;
    END
  END rec[160]
  PIN rec[161]
    DIRECTION INPUT ;
    USE SIGNAL ;
    PORT
      LAYER M5 ;
        RECT  51.888 0 51.912 0.084 ;
    END
  END rec[161]
  PIN rec[162]
    DIRECTION INPUT ;
    USE SIGNAL ;
    PORT
      LAYER M5 ;
        RECT  51.936 0 51.96 0.084 ;
    END
  END rec[162]
  PIN rec[163]
    DIRECTION INPUT ;
    USE SIGNAL ;
    PORT
      LAYER M5 ;
        RECT  51.984 0 52.008 0.084 ;
    END
  END rec[163]
  PIN rec[164]
    DIRECTION INPUT ;
    USE SIGNAL ;
    PORT
      LAYER M5 ;
        RECT  52.032 0 52.056 0.084 ;
    END
  END rec[164]
  PIN rec[165]
    DIRECTION INPUT ;
    USE SIGNAL ;
    PORT
      LAYER M5 ;
        RECT  52.08 0 52.104 0.084 ;
    END
  END rec[165]
  PIN rec[166]
    DIRECTION INPUT ;
    USE SIGNAL ;
    PORT
      LAYER M5 ;
        RECT  52.128 0 52.152 0.084 ;
    END
  END rec[166]
  PIN rec[167]
    DIRECTION INPUT ;
    USE SIGNAL ;
    PORT
      LAYER M5 ;
        RECT  52.176 0 52.2 0.084 ;
    END
  END rec[167]
  PIN rec[168]
    DIRECTION INPUT ;
    USE SIGNAL ;
    PORT
      LAYER M5 ;
        RECT  52.224 0 52.248 0.084 ;
    END
  END rec[168]
  PIN rec[169]
    DIRECTION INPUT ;
    USE SIGNAL ;
    PORT
      LAYER M5 ;
        RECT  52.272 0 52.296 0.084 ;
    END
  END rec[169]
  PIN rec[16]
    DIRECTION INPUT ;
    USE SIGNAL ;
    PORT
      LAYER M5 ;
        RECT  49.536 0 49.56 0.084 ;
    END
  END rec[16]
  PIN rec[170]
    DIRECTION INPUT ;
    USE SIGNAL ;
    PORT
      LAYER M5 ;
        RECT  52.32 0 52.344 0.084 ;
    END
  END rec[170]
  PIN rec[171]
    DIRECTION INPUT ;
    USE SIGNAL ;
    PORT
      LAYER M5 ;
        RECT  52.368 0 52.392 0.084 ;
    END
  END rec[171]
  PIN rec[172]
    DIRECTION INPUT ;
    USE SIGNAL ;
    PORT
      LAYER M5 ;
        RECT  52.416 0 52.44 0.084 ;
    END
  END rec[172]
  PIN rec[173]
    DIRECTION INPUT ;
    USE SIGNAL ;
    PORT
      LAYER M5 ;
        RECT  52.464 0 52.488 0.084 ;
    END
  END rec[173]
  PIN rec[174]
    DIRECTION INPUT ;
    USE SIGNAL ;
    PORT
      LAYER M5 ;
        RECT  52.512 0 52.536 0.084 ;
    END
  END rec[174]
  PIN rec[175]
    DIRECTION INPUT ;
    USE SIGNAL ;
    PORT
      LAYER M5 ;
        RECT  52.56 0 52.584 0.084 ;
    END
  END rec[175]
  PIN rec[176]
    DIRECTION INPUT ;
    USE SIGNAL ;
    PORT
      LAYER M5 ;
        RECT  52.608 0 52.632 0.084 ;
    END
  END rec[176]
  PIN rec[177]
    DIRECTION INPUT ;
    USE SIGNAL ;
    PORT
      LAYER M5 ;
        RECT  52.656 0 52.68 0.084 ;
    END
  END rec[177]
  PIN rec[178]
    DIRECTION INPUT ;
    USE SIGNAL ;
    PORT
      LAYER M5 ;
        RECT  52.704 0 52.728 0.084 ;
    END
  END rec[178]
  PIN rec[179]
    DIRECTION INPUT ;
    USE SIGNAL ;
    PORT
      LAYER M5 ;
        RECT  52.752 0 52.776 0.084 ;
    END
  END rec[179]
  PIN rec[17]
    DIRECTION INPUT ;
    USE SIGNAL ;
    PORT
      LAYER M5 ;
        RECT  49.584 0 49.608 0.084 ;
    END
  END rec[17]
  PIN rec[180]
    DIRECTION INPUT ;
    USE SIGNAL ;
    PORT
      LAYER M5 ;
        RECT  52.8 0 52.824 0.084 ;
    END
  END rec[180]
  PIN rec[181]
    DIRECTION INPUT ;
    USE SIGNAL ;
    PORT
      LAYER M5 ;
        RECT  52.848 0 52.872 0.084 ;
    END
  END rec[181]
  PIN rec[182]
    DIRECTION INPUT ;
    USE SIGNAL ;
    PORT
      LAYER M5 ;
        RECT  52.896 0 52.92 0.084 ;
    END
  END rec[182]
  PIN rec[183]
    DIRECTION INPUT ;
    USE SIGNAL ;
    PORT
      LAYER M5 ;
        RECT  52.944 0 52.968 0.084 ;
    END
  END rec[183]
  PIN rec[184]
    DIRECTION INPUT ;
    USE SIGNAL ;
    PORT
      LAYER M5 ;
        RECT  52.992 0 53.016 0.084 ;
    END
  END rec[184]
  PIN rec[185]
    DIRECTION INPUT ;
    USE SIGNAL ;
    PORT
      LAYER M5 ;
        RECT  53.04 0 53.064 0.084 ;
    END
  END rec[185]
  PIN rec[186]
    DIRECTION INPUT ;
    USE SIGNAL ;
    PORT
      LAYER M5 ;
        RECT  53.088 0 53.112 0.084 ;
    END
  END rec[186]
  PIN rec[187]
    DIRECTION INPUT ;
    USE SIGNAL ;
    PORT
      LAYER M5 ;
        RECT  53.136 0 53.16 0.084 ;
    END
  END rec[187]
  PIN rec[188]
    DIRECTION INPUT ;
    USE SIGNAL ;
    PORT
      LAYER M5 ;
        RECT  53.184 0 53.208 0.084 ;
    END
  END rec[188]
  PIN rec[189]
    DIRECTION INPUT ;
    USE SIGNAL ;
    PORT
      LAYER M5 ;
        RECT  53.232 0 53.256 0.084 ;
    END
  END rec[189]
  PIN rec[18]
    DIRECTION INPUT ;
    USE SIGNAL ;
    PORT
      LAYER M5 ;
        RECT  49.632 0 49.656 0.084 ;
    END
  END rec[18]
  PIN rec[190]
    DIRECTION INPUT ;
    USE SIGNAL ;
    PORT
      LAYER M5 ;
        RECT  53.28 0 53.304 0.084 ;
    END
  END rec[190]
  PIN rec[191]
    DIRECTION INPUT ;
    USE SIGNAL ;
    PORT
      LAYER M5 ;
        RECT  72.528 0 72.552 0.084 ;
    END
  END rec[191]
  PIN rec[192]
    DIRECTION INPUT ;
    USE SIGNAL ;
    PORT
      LAYER M5 ;
        RECT  72.576 0 72.6 0.084 ;
    END
  END rec[192]
  PIN rec[193]
    DIRECTION INPUT ;
    USE SIGNAL ;
    PORT
      LAYER M5 ;
        RECT  72.624 0 72.648 0.084 ;
    END
  END rec[193]
  PIN rec[194]
    DIRECTION INPUT ;
    USE SIGNAL ;
    PORT
      LAYER M5 ;
        RECT  72.672 0 72.696 0.084 ;
    END
  END rec[194]
  PIN rec[195]
    DIRECTION INPUT ;
    USE SIGNAL ;
    PORT
      LAYER M5 ;
        RECT  72.72 0 72.744 0.084 ;
    END
  END rec[195]
  PIN rec[196]
    DIRECTION INPUT ;
    USE SIGNAL ;
    PORT
      LAYER M5 ;
        RECT  72.768 0 72.792 0.084 ;
    END
  END rec[196]
  PIN rec[197]
    DIRECTION INPUT ;
    USE SIGNAL ;
    PORT
      LAYER M5 ;
        RECT  72.816 0 72.84 0.084 ;
    END
  END rec[197]
  PIN rec[198]
    DIRECTION INPUT ;
    USE SIGNAL ;
    PORT
      LAYER M5 ;
        RECT  72.864 0 72.888 0.084 ;
    END
  END rec[198]
  PIN rec[199]
    DIRECTION INPUT ;
    USE SIGNAL ;
    PORT
      LAYER M5 ;
        RECT  72.912 0 72.936 0.084 ;
    END
  END rec[199]
  PIN rec[19]
    DIRECTION INPUT ;
    USE SIGNAL ;
    PORT
      LAYER M5 ;
        RECT  49.68 0 49.704 0.084 ;
    END
  END rec[19]
  PIN rec[1]
    DIRECTION INPUT ;
    USE SIGNAL ;
    PORT
      LAYER M5 ;
        RECT  48.816 0 48.84 0.084 ;
    END
  END rec[1]
  PIN rec[200]
    DIRECTION INPUT ;
    USE SIGNAL ;
    PORT
      LAYER M5 ;
        RECT  72.96 0 72.984 0.084 ;
    END
  END rec[200]
  PIN rec[201]
    DIRECTION INPUT ;
    USE SIGNAL ;
    PORT
      LAYER M5 ;
        RECT  73.008 0 73.032 0.084 ;
    END
  END rec[201]
  PIN rec[202]
    DIRECTION INPUT ;
    USE SIGNAL ;
    PORT
      LAYER M5 ;
        RECT  73.056 0 73.08 0.084 ;
    END
  END rec[202]
  PIN rec[203]
    DIRECTION INPUT ;
    USE SIGNAL ;
    PORT
      LAYER M5 ;
        RECT  73.104 0 73.128 0.084 ;
    END
  END rec[203]
  PIN rec[204]
    DIRECTION INPUT ;
    USE SIGNAL ;
    PORT
      LAYER M5 ;
        RECT  73.152 0 73.176 0.084 ;
    END
  END rec[204]
  PIN rec[205]
    DIRECTION INPUT ;
    USE SIGNAL ;
    PORT
      LAYER M5 ;
        RECT  73.2 0 73.224 0.084 ;
    END
  END rec[205]
  PIN rec[206]
    DIRECTION INPUT ;
    USE SIGNAL ;
    PORT
      LAYER M5 ;
        RECT  73.248 0 73.272 0.084 ;
    END
  END rec[206]
  PIN rec[207]
    DIRECTION INPUT ;
    USE SIGNAL ;
    PORT
      LAYER M5 ;
        RECT  73.296 0 73.32 0.084 ;
    END
  END rec[207]
  PIN rec[208]
    DIRECTION INPUT ;
    USE SIGNAL ;
    PORT
      LAYER M5 ;
        RECT  73.344 0 73.368 0.084 ;
    END
  END rec[208]
  PIN rec[209]
    DIRECTION INPUT ;
    USE SIGNAL ;
    PORT
      LAYER M5 ;
        RECT  73.392 0 73.416 0.084 ;
    END
  END rec[209]
  PIN rec[20]
    DIRECTION INPUT ;
    USE SIGNAL ;
    PORT
      LAYER M5 ;
        RECT  49.728 0 49.752 0.084 ;
    END
  END rec[20]
  PIN rec[210]
    DIRECTION INPUT ;
    USE SIGNAL ;
    PORT
      LAYER M5 ;
        RECT  73.44 0 73.464 0.084 ;
    END
  END rec[210]
  PIN rec[211]
    DIRECTION INPUT ;
    USE SIGNAL ;
    PORT
      LAYER M5 ;
        RECT  73.488 0 73.512 0.084 ;
    END
  END rec[211]
  PIN rec[212]
    DIRECTION INPUT ;
    USE SIGNAL ;
    PORT
      LAYER M5 ;
        RECT  73.536 0 73.56 0.084 ;
    END
  END rec[212]
  PIN rec[213]
    DIRECTION INPUT ;
    USE SIGNAL ;
    PORT
      LAYER M5 ;
        RECT  73.584 0 73.608 0.084 ;
    END
  END rec[213]
  PIN rec[214]
    DIRECTION INPUT ;
    USE SIGNAL ;
    PORT
      LAYER M5 ;
        RECT  73.632 0 73.656 0.084 ;
    END
  END rec[214]
  PIN rec[215]
    DIRECTION INPUT ;
    USE SIGNAL ;
    PORT
      LAYER M5 ;
        RECT  73.68 0 73.704 0.084 ;
    END
  END rec[215]
  PIN rec[216]
    DIRECTION INPUT ;
    USE SIGNAL ;
    PORT
      LAYER M5 ;
        RECT  73.728 0 73.752 0.084 ;
    END
  END rec[216]
  PIN rec[217]
    DIRECTION INPUT ;
    USE SIGNAL ;
    PORT
      LAYER M5 ;
        RECT  73.776 0 73.8 0.084 ;
    END
  END rec[217]
  PIN rec[218]
    DIRECTION INPUT ;
    USE SIGNAL ;
    PORT
      LAYER M5 ;
        RECT  73.824 0 73.848 0.084 ;
    END
  END rec[218]
  PIN rec[219]
    DIRECTION INPUT ;
    USE SIGNAL ;
    PORT
      LAYER M5 ;
        RECT  73.872 0 73.896 0.084 ;
    END
  END rec[219]
  PIN rec[21]
    DIRECTION INPUT ;
    USE SIGNAL ;
    PORT
      LAYER M5 ;
        RECT  49.776 0 49.8 0.084 ;
    END
  END rec[21]
  PIN rec[220]
    DIRECTION INPUT ;
    USE SIGNAL ;
    PORT
      LAYER M5 ;
        RECT  73.92 0 73.944 0.084 ;
    END
  END rec[220]
  PIN rec[221]
    DIRECTION INPUT ;
    USE SIGNAL ;
    PORT
      LAYER M5 ;
        RECT  73.968 0 73.992 0.084 ;
    END
  END rec[221]
  PIN rec[222]
    DIRECTION INPUT ;
    USE SIGNAL ;
    PORT
      LAYER M5 ;
        RECT  74.016 0 74.04 0.084 ;
    END
  END rec[222]
  PIN rec[223]
    DIRECTION INPUT ;
    USE SIGNAL ;
    PORT
      LAYER M5 ;
        RECT  54.864 0 54.888 0.084 ;
    END
  END rec[223]
  PIN rec[224]
    DIRECTION INPUT ;
    USE SIGNAL ;
    PORT
      LAYER M5 ;
        RECT  54.912 0 54.936 0.084 ;
    END
  END rec[224]
  PIN rec[225]
    DIRECTION INPUT ;
    USE SIGNAL ;
    PORT
      LAYER M5 ;
        RECT  54.96 0 54.984 0.084 ;
    END
  END rec[225]
  PIN rec[226]
    DIRECTION INPUT ;
    USE SIGNAL ;
    PORT
      LAYER M5 ;
        RECT  55.008 0 55.032 0.084 ;
    END
  END rec[226]
  PIN rec[227]
    DIRECTION INPUT ;
    USE SIGNAL ;
    PORT
      LAYER M5 ;
        RECT  55.056 0 55.08 0.084 ;
    END
  END rec[227]
  PIN rec[228]
    DIRECTION INPUT ;
    USE SIGNAL ;
    PORT
      LAYER M5 ;
        RECT  55.104 0 55.128 0.084 ;
    END
  END rec[228]
  PIN rec[229]
    DIRECTION INPUT ;
    USE SIGNAL ;
    PORT
      LAYER M5 ;
        RECT  55.152 0 55.176 0.084 ;
    END
  END rec[229]
  PIN rec[22]
    DIRECTION INPUT ;
    USE SIGNAL ;
    PORT
      LAYER M5 ;
        RECT  49.824 0 49.848 0.084 ;
    END
  END rec[22]
  PIN rec[230]
    DIRECTION INPUT ;
    USE SIGNAL ;
    PORT
      LAYER M5 ;
        RECT  55.2 0 55.224 0.084 ;
    END
  END rec[230]
  PIN rec[231]
    DIRECTION INPUT ;
    USE SIGNAL ;
    PORT
      LAYER M5 ;
        RECT  55.248 0 55.272 0.084 ;
    END
  END rec[231]
  PIN rec[232]
    DIRECTION INPUT ;
    USE SIGNAL ;
    PORT
      LAYER M5 ;
        RECT  55.296 0 55.32 0.084 ;
    END
  END rec[232]
  PIN rec[233]
    DIRECTION INPUT ;
    USE SIGNAL ;
    PORT
      LAYER M5 ;
        RECT  55.344 0 55.368 0.084 ;
    END
  END rec[233]
  PIN rec[234]
    DIRECTION INPUT ;
    USE SIGNAL ;
    PORT
      LAYER M5 ;
        RECT  55.392 0 55.416 0.084 ;
    END
  END rec[234]
  PIN rec[235]
    DIRECTION INPUT ;
    USE SIGNAL ;
    PORT
      LAYER M5 ;
        RECT  55.44 0 55.464 0.084 ;
    END
  END rec[235]
  PIN rec[236]
    DIRECTION INPUT ;
    USE SIGNAL ;
    PORT
      LAYER M5 ;
        RECT  55.488 0 55.512 0.084 ;
    END
  END rec[236]
  PIN rec[237]
    DIRECTION INPUT ;
    USE SIGNAL ;
    PORT
      LAYER M5 ;
        RECT  55.536 0 55.56 0.084 ;
    END
  END rec[237]
  PIN rec[238]
    DIRECTION INPUT ;
    USE SIGNAL ;
    PORT
      LAYER M5 ;
        RECT  55.584 0 55.608 0.084 ;
    END
  END rec[238]
  PIN rec[239]
    DIRECTION INPUT ;
    USE SIGNAL ;
    PORT
      LAYER M5 ;
        RECT  55.632 0 55.656 0.084 ;
    END
  END rec[239]
  PIN rec[23]
    DIRECTION INPUT ;
    USE SIGNAL ;
    PORT
      LAYER M5 ;
        RECT  49.872 0 49.896 0.084 ;
    END
  END rec[23]
  PIN rec[240]
    DIRECTION INPUT ;
    USE SIGNAL ;
    PORT
      LAYER M5 ;
        RECT  55.68 0 55.704 0.084 ;
    END
  END rec[240]
  PIN rec[241]
    DIRECTION INPUT ;
    USE SIGNAL ;
    PORT
      LAYER M5 ;
        RECT  55.728 0 55.752 0.084 ;
    END
  END rec[241]
  PIN rec[242]
    DIRECTION INPUT ;
    USE SIGNAL ;
    PORT
      LAYER M5 ;
        RECT  55.776 0 55.8 0.084 ;
    END
  END rec[242]
  PIN rec[243]
    DIRECTION INPUT ;
    USE SIGNAL ;
    PORT
      LAYER M5 ;
        RECT  55.824 0 55.848 0.084 ;
    END
  END rec[243]
  PIN rec[244]
    DIRECTION INPUT ;
    USE SIGNAL ;
    PORT
      LAYER M5 ;
        RECT  55.872 0 55.896 0.084 ;
    END
  END rec[244]
  PIN rec[245]
    DIRECTION INPUT ;
    USE SIGNAL ;
    PORT
      LAYER M5 ;
        RECT  55.92 0 55.944 0.084 ;
    END
  END rec[245]
  PIN rec[246]
    DIRECTION INPUT ;
    USE SIGNAL ;
    PORT
      LAYER M5 ;
        RECT  55.968 0 55.992 0.084 ;
    END
  END rec[246]
  PIN rec[247]
    DIRECTION INPUT ;
    USE SIGNAL ;
    PORT
      LAYER M5 ;
        RECT  56.016 0 56.04 0.084 ;
    END
  END rec[247]
  PIN rec[248]
    DIRECTION INPUT ;
    USE SIGNAL ;
    PORT
      LAYER M5 ;
        RECT  56.064 0 56.088 0.084 ;
    END
  END rec[248]
  PIN rec[249]
    DIRECTION INPUT ;
    USE SIGNAL ;
    PORT
      LAYER M5 ;
        RECT  56.112 0 56.136 0.084 ;
    END
  END rec[249]
  PIN rec[24]
    DIRECTION INPUT ;
    USE SIGNAL ;
    PORT
      LAYER M5 ;
        RECT  49.92 0 49.944 0.084 ;
    END
  END rec[24]
  PIN rec[250]
    DIRECTION INPUT ;
    USE SIGNAL ;
    PORT
      LAYER M5 ;
        RECT  56.16 0 56.184 0.084 ;
    END
  END rec[250]
  PIN rec[251]
    DIRECTION INPUT ;
    USE SIGNAL ;
    PORT
      LAYER M5 ;
        RECT  56.208 0 56.232 0.084 ;
    END
  END rec[251]
  PIN rec[252]
    DIRECTION INPUT ;
    USE SIGNAL ;
    PORT
      LAYER M5 ;
        RECT  56.256 0 56.28 0.084 ;
    END
  END rec[252]
  PIN rec[253]
    DIRECTION INPUT ;
    USE SIGNAL ;
    PORT
      LAYER M5 ;
        RECT  56.304 0 56.328 0.084 ;
    END
  END rec[253]
  PIN rec[254]
    DIRECTION INPUT ;
    USE SIGNAL ;
    PORT
      LAYER M5 ;
        RECT  56.352 0 56.376 0.084 ;
    END
  END rec[254]
  PIN rec[255]
    DIRECTION INPUT ;
    USE SIGNAL ;
    PORT
      LAYER M5 ;
        RECT  56.4 0 56.424 0.084 ;
    END
  END rec[255]
  PIN rec[256]
    DIRECTION INPUT ;
    USE SIGNAL ;
    PORT
      LAYER M5 ;
        RECT  56.448 0 56.472 0.084 ;
    END
  END rec[256]
  PIN rec[257]
    DIRECTION INPUT ;
    USE SIGNAL ;
    PORT
      LAYER M5 ;
        RECT  56.496 0 56.52 0.084 ;
    END
  END rec[257]
  PIN rec[258]
    DIRECTION INPUT ;
    USE SIGNAL ;
    PORT
      LAYER M5 ;
        RECT  56.544 0 56.568 0.084 ;
    END
  END rec[258]
  PIN rec[259]
    DIRECTION INPUT ;
    USE SIGNAL ;
    PORT
      LAYER M5 ;
        RECT  56.592 0 56.616 0.084 ;
    END
  END rec[259]
  PIN rec[25]
    DIRECTION INPUT ;
    USE SIGNAL ;
    PORT
      LAYER M5 ;
        RECT  49.968 0 49.992 0.084 ;
    END
  END rec[25]
  PIN rec[260]
    DIRECTION INPUT ;
    USE SIGNAL ;
    PORT
      LAYER M5 ;
        RECT  56.64 0 56.664 0.084 ;
    END
  END rec[260]
  PIN rec[261]
    DIRECTION INPUT ;
    USE SIGNAL ;
    PORT
      LAYER M5 ;
        RECT  56.688 0 56.712 0.084 ;
    END
  END rec[261]
  PIN rec[262]
    DIRECTION INPUT ;
    USE SIGNAL ;
    PORT
      LAYER M5 ;
        RECT  56.736 0 56.76 0.084 ;
    END
  END rec[262]
  PIN rec[263]
    DIRECTION INPUT ;
    USE SIGNAL ;
    PORT
      LAYER M5 ;
        RECT  56.784 0 56.808 0.084 ;
    END
  END rec[263]
  PIN rec[264]
    DIRECTION INPUT ;
    USE SIGNAL ;
    PORT
      LAYER M5 ;
        RECT  56.832 0 56.856 0.084 ;
    END
  END rec[264]
  PIN rec[265]
    DIRECTION INPUT ;
    USE SIGNAL ;
    PORT
      LAYER M5 ;
        RECT  56.88 0 56.904 0.084 ;
    END
  END rec[265]
  PIN rec[266]
    DIRECTION INPUT ;
    USE SIGNAL ;
    PORT
      LAYER M5 ;
        RECT  56.928 0 56.952 0.084 ;
    END
  END rec[266]
  PIN rec[267]
    DIRECTION INPUT ;
    USE SIGNAL ;
    PORT
      LAYER M5 ;
        RECT  56.976 0 57 0.084 ;
    END
  END rec[267]
  PIN rec[268]
    DIRECTION INPUT ;
    USE SIGNAL ;
    PORT
      LAYER M5 ;
        RECT  57.024 0 57.048 0.084 ;
    END
  END rec[268]
  PIN rec[269]
    DIRECTION INPUT ;
    USE SIGNAL ;
    PORT
      LAYER M5 ;
        RECT  57.072 0 57.096 0.084 ;
    END
  END rec[269]
  PIN rec[26]
    DIRECTION INPUT ;
    USE SIGNAL ;
    PORT
      LAYER M5 ;
        RECT  50.016 0 50.04 0.084 ;
    END
  END rec[26]
  PIN rec[270]
    DIRECTION INPUT ;
    USE SIGNAL ;
    PORT
      LAYER M5 ;
        RECT  57.12 0 57.144 0.084 ;
    END
  END rec[270]
  PIN rec[271]
    DIRECTION INPUT ;
    USE SIGNAL ;
    PORT
      LAYER M5 ;
        RECT  57.168 0 57.192 0.084 ;
    END
  END rec[271]
  PIN rec[272]
    DIRECTION INPUT ;
    USE SIGNAL ;
    PORT
      LAYER M5 ;
        RECT  57.216 0 57.24 0.084 ;
    END
  END rec[272]
  PIN rec[273]
    DIRECTION INPUT ;
    USE SIGNAL ;
    PORT
      LAYER M5 ;
        RECT  57.264 0 57.288 0.084 ;
    END
  END rec[273]
  PIN rec[274]
    DIRECTION INPUT ;
    USE SIGNAL ;
    PORT
      LAYER M5 ;
        RECT  57.312 0 57.336 0.084 ;
    END
  END rec[274]
  PIN rec[275]
    DIRECTION INPUT ;
    USE SIGNAL ;
    PORT
      LAYER M5 ;
        RECT  57.36 0 57.384 0.084 ;
    END
  END rec[275]
  PIN rec[276]
    DIRECTION INPUT ;
    USE SIGNAL ;
    PORT
      LAYER M5 ;
        RECT  57.408 0 57.432 0.084 ;
    END
  END rec[276]
  PIN rec[277]
    DIRECTION INPUT ;
    USE SIGNAL ;
    PORT
      LAYER M5 ;
        RECT  57.456 0 57.48 0.084 ;
    END
  END rec[277]
  PIN rec[278]
    DIRECTION INPUT ;
    USE SIGNAL ;
    PORT
      LAYER M5 ;
        RECT  57.504 0 57.528 0.084 ;
    END
  END rec[278]
  PIN rec[279]
    DIRECTION INPUT ;
    USE SIGNAL ;
    PORT
      LAYER M5 ;
        RECT  57.552 0 57.576 0.084 ;
    END
  END rec[279]
  PIN rec[27]
    DIRECTION INPUT ;
    USE SIGNAL ;
    PORT
      LAYER M5 ;
        RECT  50.064 0 50.088 0.084 ;
    END
  END rec[27]
  PIN rec[280]
    DIRECTION INPUT ;
    USE SIGNAL ;
    PORT
      LAYER M5 ;
        RECT  57.6 0 57.624 0.084 ;
    END
  END rec[280]
  PIN rec[281]
    DIRECTION INPUT ;
    USE SIGNAL ;
    PORT
      LAYER M5 ;
        RECT  57.648 0 57.672 0.084 ;
    END
  END rec[281]
  PIN rec[282]
    DIRECTION INPUT ;
    USE SIGNAL ;
    PORT
      LAYER M5 ;
        RECT  57.696 0 57.72 0.084 ;
    END
  END rec[282]
  PIN rec[283]
    DIRECTION INPUT ;
    USE SIGNAL ;
    PORT
      LAYER M5 ;
        RECT  57.744 0 57.768 0.084 ;
    END
  END rec[283]
  PIN rec[284]
    DIRECTION INPUT ;
    USE SIGNAL ;
    PORT
      LAYER M5 ;
        RECT  57.792 0 57.816 0.084 ;
    END
  END rec[284]
  PIN rec[285]
    DIRECTION INPUT ;
    USE SIGNAL ;
    PORT
      LAYER M5 ;
        RECT  57.84 0 57.864 0.084 ;
    END
  END rec[285]
  PIN rec[286]
    DIRECTION INPUT ;
    USE SIGNAL ;
    PORT
      LAYER M5 ;
        RECT  57.888 0 57.912 0.084 ;
    END
  END rec[286]
  PIN rec[287]
    DIRECTION INPUT ;
    USE SIGNAL ;
    PORT
      LAYER M5 ;
        RECT  10.32 0 10.344 0.084 ;
    END
  END rec[287]
  PIN rec[288]
    DIRECTION INPUT ;
    USE SIGNAL ;
    PORT
      LAYER M5 ;
        RECT  10.368 0 10.392 0.084 ;
    END
  END rec[288]
  PIN rec[289]
    DIRECTION INPUT ;
    USE SIGNAL ;
    PORT
      LAYER M5 ;
        RECT  10.416 0 10.44 0.084 ;
    END
  END rec[289]
  PIN rec[28]
    DIRECTION INPUT ;
    USE SIGNAL ;
    PORT
      LAYER M5 ;
        RECT  50.112 0 50.136 0.084 ;
    END
  END rec[28]
  PIN rec[290]
    DIRECTION INPUT ;
    USE SIGNAL ;
    PORT
      LAYER M5 ;
        RECT  10.464 0 10.488 0.084 ;
    END
  END rec[290]
  PIN rec[291]
    DIRECTION INPUT ;
    USE SIGNAL ;
    PORT
      LAYER M5 ;
        RECT  10.512 0 10.536 0.084 ;
    END
  END rec[291]
  PIN rec[292]
    DIRECTION INPUT ;
    USE SIGNAL ;
    PORT
      LAYER M5 ;
        RECT  10.56 0 10.584 0.084 ;
    END
  END rec[292]
  PIN rec[293]
    DIRECTION INPUT ;
    USE SIGNAL ;
    PORT
      LAYER M5 ;
        RECT  10.608 0 10.632 0.084 ;
    END
  END rec[293]
  PIN rec[294]
    DIRECTION INPUT ;
    USE SIGNAL ;
    PORT
      LAYER M5 ;
        RECT  10.656 0 10.68 0.084 ;
    END
  END rec[294]
  PIN rec[295]
    DIRECTION INPUT ;
    USE SIGNAL ;
    PORT
      LAYER M5 ;
        RECT  10.704 0 10.728 0.084 ;
    END
  END rec[295]
  PIN rec[296]
    DIRECTION INPUT ;
    USE SIGNAL ;
    PORT
      LAYER M5 ;
        RECT  10.752 0 10.776 0.084 ;
    END
  END rec[296]
  PIN rec[297]
    DIRECTION INPUT ;
    USE SIGNAL ;
    PORT
      LAYER M5 ;
        RECT  10.8 0 10.824 0.084 ;
    END
  END rec[297]
  PIN rec[298]
    DIRECTION INPUT ;
    USE SIGNAL ;
    PORT
      LAYER M5 ;
        RECT  10.848 0 10.872 0.084 ;
    END
  END rec[298]
  PIN rec[299]
    DIRECTION INPUT ;
    USE SIGNAL ;
    PORT
      LAYER M5 ;
        RECT  10.896 0 10.92 0.084 ;
    END
  END rec[299]
  PIN rec[29]
    DIRECTION INPUT ;
    USE SIGNAL ;
    PORT
      LAYER M5 ;
        RECT  50.16 0 50.184 0.084 ;
    END
  END rec[29]
  PIN rec[2]
    DIRECTION INPUT ;
    USE SIGNAL ;
    PORT
      LAYER M5 ;
        RECT  48.864 0 48.888 0.084 ;
    END
  END rec[2]
  PIN rec[300]
    DIRECTION INPUT ;
    USE SIGNAL ;
    PORT
      LAYER M5 ;
        RECT  10.944 0 10.968 0.084 ;
    END
  END rec[300]
  PIN rec[301]
    DIRECTION INPUT ;
    USE SIGNAL ;
    PORT
      LAYER M5 ;
        RECT  10.992 0 11.016 0.084 ;
    END
  END rec[301]
  PIN rec[302]
    DIRECTION INPUT ;
    USE SIGNAL ;
    PORT
      LAYER M5 ;
        RECT  11.04 0 11.064 0.084 ;
    END
  END rec[302]
  PIN rec[303]
    DIRECTION INPUT ;
    USE SIGNAL ;
    PORT
      LAYER M5 ;
        RECT  11.088 0 11.112 0.084 ;
    END
  END rec[303]
  PIN rec[304]
    DIRECTION INPUT ;
    USE SIGNAL ;
    PORT
      LAYER M5 ;
        RECT  11.136 0 11.16 0.084 ;
    END
  END rec[304]
  PIN rec[305]
    DIRECTION INPUT ;
    USE SIGNAL ;
    PORT
      LAYER M5 ;
        RECT  11.184 0 11.208 0.084 ;
    END
  END rec[305]
  PIN rec[306]
    DIRECTION INPUT ;
    USE SIGNAL ;
    PORT
      LAYER M5 ;
        RECT  11.232 0 11.256 0.084 ;
    END
  END rec[306]
  PIN rec[307]
    DIRECTION INPUT ;
    USE SIGNAL ;
    PORT
      LAYER M5 ;
        RECT  11.28 0 11.304 0.084 ;
    END
  END rec[307]
  PIN rec[308]
    DIRECTION INPUT ;
    USE SIGNAL ;
    PORT
      LAYER M5 ;
        RECT  11.328 0 11.352 0.084 ;
    END
  END rec[308]
  PIN rec[309]
    DIRECTION INPUT ;
    USE SIGNAL ;
    PORT
      LAYER M5 ;
        RECT  11.376 0 11.4 0.084 ;
    END
  END rec[309]
  PIN rec[30]
    DIRECTION INPUT ;
    USE SIGNAL ;
    PORT
      LAYER M5 ;
        RECT  50.208 0 50.232 0.084 ;
    END
  END rec[30]
  PIN rec[310]
    DIRECTION INPUT ;
    USE SIGNAL ;
    PORT
      LAYER M5 ;
        RECT  11.424 0 11.448 0.084 ;
    END
  END rec[310]
  PIN rec[311]
    DIRECTION INPUT ;
    USE SIGNAL ;
    PORT
      LAYER M5 ;
        RECT  11.472 0 11.496 0.084 ;
    END
  END rec[311]
  PIN rec[312]
    DIRECTION INPUT ;
    USE SIGNAL ;
    PORT
      LAYER M5 ;
        RECT  11.52 0 11.544 0.084 ;
    END
  END rec[312]
  PIN rec[313]
    DIRECTION INPUT ;
    USE SIGNAL ;
    PORT
      LAYER M5 ;
        RECT  11.568 0 11.592 0.084 ;
    END
  END rec[313]
  PIN rec[314]
    DIRECTION INPUT ;
    USE SIGNAL ;
    PORT
      LAYER M5 ;
        RECT  11.616 0 11.64 0.084 ;
    END
  END rec[314]
  PIN rec[315]
    DIRECTION INPUT ;
    USE SIGNAL ;
    PORT
      LAYER M5 ;
        RECT  11.664 0 11.688 0.084 ;
    END
  END rec[315]
  PIN rec[316]
    DIRECTION INPUT ;
    USE SIGNAL ;
    PORT
      LAYER M5 ;
        RECT  11.712 0 11.736 0.084 ;
    END
  END rec[316]
  PIN rec[317]
    DIRECTION INPUT ;
    USE SIGNAL ;
    PORT
      LAYER M5 ;
        RECT  11.76 0 11.784 0.084 ;
    END
  END rec[317]
  PIN rec[318]
    DIRECTION INPUT ;
    USE SIGNAL ;
    PORT
      LAYER M5 ;
        RECT  11.808 0 11.832 0.084 ;
    END
  END rec[318]
  PIN rec[319]
    DIRECTION INPUT ;
    USE SIGNAL ;
    PORT
      LAYER M5 ;
        RECT  19.92 0 19.944 0.084 ;
    END
  END rec[319]
  PIN rec[31]
    DIRECTION INPUT ;
    USE SIGNAL ;
    PORT
      LAYER M5 ;
        RECT  0.72 0 0.744 0.084 ;
    END
  END rec[31]
  PIN rec[320]
    DIRECTION INPUT ;
    USE SIGNAL ;
    PORT
      LAYER M5 ;
        RECT  19.968 0 19.992 0.084 ;
    END
  END rec[320]
  PIN rec[321]
    DIRECTION INPUT ;
    USE SIGNAL ;
    PORT
      LAYER M5 ;
        RECT  20.016 0 20.04 0.084 ;
    END
  END rec[321]
  PIN rec[322]
    DIRECTION INPUT ;
    USE SIGNAL ;
    PORT
      LAYER M5 ;
        RECT  20.064 0 20.088 0.084 ;
    END
  END rec[322]
  PIN rec[323]
    DIRECTION INPUT ;
    USE SIGNAL ;
    PORT
      LAYER M5 ;
        RECT  20.112 0 20.136 0.084 ;
    END
  END rec[323]
  PIN rec[324]
    DIRECTION INPUT ;
    USE SIGNAL ;
    PORT
      LAYER M5 ;
        RECT  20.16 0 20.184 0.084 ;
    END
  END rec[324]
  PIN rec[325]
    DIRECTION INPUT ;
    USE SIGNAL ;
    PORT
      LAYER M5 ;
        RECT  20.208 0 20.232 0.084 ;
    END
  END rec[325]
  PIN rec[326]
    DIRECTION INPUT ;
    USE SIGNAL ;
    PORT
      LAYER M5 ;
        RECT  20.256 0 20.28 0.084 ;
    END
  END rec[326]
  PIN rec[327]
    DIRECTION INPUT ;
    USE SIGNAL ;
    PORT
      LAYER M5 ;
        RECT  20.304 0 20.328 0.084 ;
    END
  END rec[327]
  PIN rec[328]
    DIRECTION INPUT ;
    USE SIGNAL ;
    PORT
      LAYER M5 ;
        RECT  20.352 0 20.376 0.084 ;
    END
  END rec[328]
  PIN rec[329]
    DIRECTION INPUT ;
    USE SIGNAL ;
    PORT
      LAYER M5 ;
        RECT  20.4 0 20.424 0.084 ;
    END
  END rec[329]
  PIN rec[32]
    DIRECTION INPUT ;
    USE SIGNAL ;
    PORT
      LAYER M5 ;
        RECT  0.768 0 0.792 0.084 ;
    END
  END rec[32]
  PIN rec[330]
    DIRECTION INPUT ;
    USE SIGNAL ;
    PORT
      LAYER M5 ;
        RECT  20.448 0 20.472 0.084 ;
    END
  END rec[330]
  PIN rec[331]
    DIRECTION INPUT ;
    USE SIGNAL ;
    PORT
      LAYER M5 ;
        RECT  20.496 0 20.52 0.084 ;
    END
  END rec[331]
  PIN rec[332]
    DIRECTION INPUT ;
    USE SIGNAL ;
    PORT
      LAYER M5 ;
        RECT  20.544 0 20.568 0.084 ;
    END
  END rec[332]
  PIN rec[333]
    DIRECTION INPUT ;
    USE SIGNAL ;
    PORT
      LAYER M5 ;
        RECT  20.592 0 20.616 0.084 ;
    END
  END rec[333]
  PIN rec[334]
    DIRECTION INPUT ;
    USE SIGNAL ;
    PORT
      LAYER M5 ;
        RECT  20.64 0 20.664 0.084 ;
    END
  END rec[334]
  PIN rec[335]
    DIRECTION INPUT ;
    USE SIGNAL ;
    PORT
      LAYER M5 ;
        RECT  20.688 0 20.712 0.084 ;
    END
  END rec[335]
  PIN rec[336]
    DIRECTION INPUT ;
    USE SIGNAL ;
    PORT
      LAYER M5 ;
        RECT  20.736 0 20.76 0.084 ;
    END
  END rec[336]
  PIN rec[337]
    DIRECTION INPUT ;
    USE SIGNAL ;
    PORT
      LAYER M5 ;
        RECT  20.784 0 20.808 0.084 ;
    END
  END rec[337]
  PIN rec[338]
    DIRECTION INPUT ;
    USE SIGNAL ;
    PORT
      LAYER M5 ;
        RECT  20.832 0 20.856 0.084 ;
    END
  END rec[338]
  PIN rec[339]
    DIRECTION INPUT ;
    USE SIGNAL ;
    PORT
      LAYER M5 ;
        RECT  20.88 0 20.904 0.084 ;
    END
  END rec[339]
  PIN rec[33]
    DIRECTION INPUT ;
    USE SIGNAL ;
    PORT
      LAYER M5 ;
        RECT  0.816 0 0.84 0.084 ;
    END
  END rec[33]
  PIN rec[340]
    DIRECTION INPUT ;
    USE SIGNAL ;
    PORT
      LAYER M5 ;
        RECT  20.928 0 20.952 0.084 ;
    END
  END rec[340]
  PIN rec[341]
    DIRECTION INPUT ;
    USE SIGNAL ;
    PORT
      LAYER M5 ;
        RECT  20.976 0 21 0.084 ;
    END
  END rec[341]
  PIN rec[342]
    DIRECTION INPUT ;
    USE SIGNAL ;
    PORT
      LAYER M5 ;
        RECT  21.024 0 21.048 0.084 ;
    END
  END rec[342]
  PIN rec[343]
    DIRECTION INPUT ;
    USE SIGNAL ;
    PORT
      LAYER M5 ;
        RECT  21.072 0 21.096 0.084 ;
    END
  END rec[343]
  PIN rec[344]
    DIRECTION INPUT ;
    USE SIGNAL ;
    PORT
      LAYER M5 ;
        RECT  21.12 0 21.144 0.084 ;
    END
  END rec[344]
  PIN rec[345]
    DIRECTION INPUT ;
    USE SIGNAL ;
    PORT
      LAYER M5 ;
        RECT  21.168 0 21.192 0.084 ;
    END
  END rec[345]
  PIN rec[346]
    DIRECTION INPUT ;
    USE SIGNAL ;
    PORT
      LAYER M5 ;
        RECT  21.216 0 21.24 0.084 ;
    END
  END rec[346]
  PIN rec[347]
    DIRECTION INPUT ;
    USE SIGNAL ;
    PORT
      LAYER M5 ;
        RECT  21.264 0 21.288 0.084 ;
    END
  END rec[347]
  PIN rec[348]
    DIRECTION INPUT ;
    USE SIGNAL ;
    PORT
      LAYER M5 ;
        RECT  21.312 0 21.336 0.084 ;
    END
  END rec[348]
  PIN rec[349]
    DIRECTION INPUT ;
    USE SIGNAL ;
    PORT
      LAYER M5 ;
        RECT  21.36 0 21.384 0.084 ;
    END
  END rec[349]
  PIN rec[34]
    DIRECTION INPUT ;
    USE SIGNAL ;
    PORT
      LAYER M5 ;
        RECT  0.864 0 0.888 0.084 ;
    END
  END rec[34]
  PIN rec[350]
    DIRECTION INPUT ;
    USE SIGNAL ;
    PORT
      LAYER M5 ;
        RECT  21.408 0 21.432 0.084 ;
    END
  END rec[350]
  PIN rec[351]
    DIRECTION INPUT ;
    USE SIGNAL ;
    PORT
      LAYER M5 ;
        RECT  29.52 0 29.544 0.084 ;
    END
  END rec[351]
  PIN rec[352]
    DIRECTION INPUT ;
    USE SIGNAL ;
    PORT
      LAYER M5 ;
        RECT  29.568 0 29.592 0.084 ;
    END
  END rec[352]
  PIN rec[353]
    DIRECTION INPUT ;
    USE SIGNAL ;
    PORT
      LAYER M5 ;
        RECT  29.616 0 29.64 0.084 ;
    END
  END rec[353]
  PIN rec[354]
    DIRECTION INPUT ;
    USE SIGNAL ;
    PORT
      LAYER M5 ;
        RECT  29.664 0 29.688 0.084 ;
    END
  END rec[354]
  PIN rec[355]
    DIRECTION INPUT ;
    USE SIGNAL ;
    PORT
      LAYER M5 ;
        RECT  29.712 0 29.736 0.084 ;
    END
  END rec[355]
  PIN rec[356]
    DIRECTION INPUT ;
    USE SIGNAL ;
    PORT
      LAYER M5 ;
        RECT  29.76 0 29.784 0.084 ;
    END
  END rec[356]
  PIN rec[357]
    DIRECTION INPUT ;
    USE SIGNAL ;
    PORT
      LAYER M5 ;
        RECT  29.808 0 29.832 0.084 ;
    END
  END rec[357]
  PIN rec[358]
    DIRECTION INPUT ;
    USE SIGNAL ;
    PORT
      LAYER M5 ;
        RECT  29.856 0 29.88 0.084 ;
    END
  END rec[358]
  PIN rec[359]
    DIRECTION INPUT ;
    USE SIGNAL ;
    PORT
      LAYER M5 ;
        RECT  29.904 0 29.928 0.084 ;
    END
  END rec[359]
  PIN rec[35]
    DIRECTION INPUT ;
    USE SIGNAL ;
    PORT
      LAYER M5 ;
        RECT  0.912 0 0.936 0.084 ;
    END
  END rec[35]
  PIN rec[360]
    DIRECTION INPUT ;
    USE SIGNAL ;
    PORT
      LAYER M5 ;
        RECT  29.952 0 29.976 0.084 ;
    END
  END rec[360]
  PIN rec[361]
    DIRECTION INPUT ;
    USE SIGNAL ;
    PORT
      LAYER M5 ;
        RECT  30 0 30.024 0.084 ;
    END
  END rec[361]
  PIN rec[362]
    DIRECTION INPUT ;
    USE SIGNAL ;
    PORT
      LAYER M5 ;
        RECT  30.048 0 30.072 0.084 ;
    END
  END rec[362]
  PIN rec[363]
    DIRECTION INPUT ;
    USE SIGNAL ;
    PORT
      LAYER M5 ;
        RECT  30.096 0 30.12 0.084 ;
    END
  END rec[363]
  PIN rec[364]
    DIRECTION INPUT ;
    USE SIGNAL ;
    PORT
      LAYER M5 ;
        RECT  30.144 0 30.168 0.084 ;
    END
  END rec[364]
  PIN rec[365]
    DIRECTION INPUT ;
    USE SIGNAL ;
    PORT
      LAYER M5 ;
        RECT  30.192 0 30.216 0.084 ;
    END
  END rec[365]
  PIN rec[366]
    DIRECTION INPUT ;
    USE SIGNAL ;
    PORT
      LAYER M5 ;
        RECT  30.24 0 30.264 0.084 ;
    END
  END rec[366]
  PIN rec[367]
    DIRECTION INPUT ;
    USE SIGNAL ;
    PORT
      LAYER M5 ;
        RECT  30.288 0 30.312 0.084 ;
    END
  END rec[367]
  PIN rec[368]
    DIRECTION INPUT ;
    USE SIGNAL ;
    PORT
      LAYER M5 ;
        RECT  30.336 0 30.36 0.084 ;
    END
  END rec[368]
  PIN rec[369]
    DIRECTION INPUT ;
    USE SIGNAL ;
    PORT
      LAYER M5 ;
        RECT  30.384 0 30.408 0.084 ;
    END
  END rec[369]
  PIN rec[36]
    DIRECTION INPUT ;
    USE SIGNAL ;
    PORT
      LAYER M5 ;
        RECT  0.96 0 0.984 0.084 ;
    END
  END rec[36]
  PIN rec[370]
    DIRECTION INPUT ;
    USE SIGNAL ;
    PORT
      LAYER M5 ;
        RECT  30.432 0 30.456 0.084 ;
    END
  END rec[370]
  PIN rec[371]
    DIRECTION INPUT ;
    USE SIGNAL ;
    PORT
      LAYER M5 ;
        RECT  30.48 0 30.504 0.084 ;
    END
  END rec[371]
  PIN rec[372]
    DIRECTION INPUT ;
    USE SIGNAL ;
    PORT
      LAYER M5 ;
        RECT  30.528 0 30.552 0.084 ;
    END
  END rec[372]
  PIN rec[373]
    DIRECTION INPUT ;
    USE SIGNAL ;
    PORT
      LAYER M5 ;
        RECT  30.576 0 30.6 0.084 ;
    END
  END rec[373]
  PIN rec[374]
    DIRECTION INPUT ;
    USE SIGNAL ;
    PORT
      LAYER M5 ;
        RECT  30.624 0 30.648 0.084 ;
    END
  END rec[374]
  PIN rec[375]
    DIRECTION INPUT ;
    USE SIGNAL ;
    PORT
      LAYER M5 ;
        RECT  30.672 0 30.696 0.084 ;
    END
  END rec[375]
  PIN rec[376]
    DIRECTION INPUT ;
    USE SIGNAL ;
    PORT
      LAYER M5 ;
        RECT  30.72 0 30.744 0.084 ;
    END
  END rec[376]
  PIN rec[377]
    DIRECTION INPUT ;
    USE SIGNAL ;
    PORT
      LAYER M5 ;
        RECT  30.768 0 30.792 0.084 ;
    END
  END rec[377]
  PIN rec[378]
    DIRECTION INPUT ;
    USE SIGNAL ;
    PORT
      LAYER M5 ;
        RECT  30.816 0 30.84 0.084 ;
    END
  END rec[378]
  PIN rec[379]
    DIRECTION INPUT ;
    USE SIGNAL ;
    PORT
      LAYER M5 ;
        RECT  30.864 0 30.888 0.084 ;
    END
  END rec[379]
  PIN rec[37]
    DIRECTION INPUT ;
    USE SIGNAL ;
    PORT
      LAYER M5 ;
        RECT  1.008 0 1.032 0.084 ;
    END
  END rec[37]
  PIN rec[380]
    DIRECTION INPUT ;
    USE SIGNAL ;
    PORT
      LAYER M5 ;
        RECT  30.912 0 30.936 0.084 ;
    END
  END rec[380]
  PIN rec[381]
    DIRECTION INPUT ;
    USE SIGNAL ;
    PORT
      LAYER M5 ;
        RECT  30.96 0 30.984 0.084 ;
    END
  END rec[381]
  PIN rec[382]
    DIRECTION INPUT ;
    USE SIGNAL ;
    PORT
      LAYER M5 ;
        RECT  31.008 0 31.032 0.084 ;
    END
  END rec[382]
  PIN rec[383]
    DIRECTION INPUT ;
    USE SIGNAL ;
    PORT
      LAYER M5 ;
        RECT  53.328 0 53.352 0.084 ;
    END
  END rec[383]
  PIN rec[384]
    DIRECTION INPUT ;
    USE SIGNAL ;
    PORT
      LAYER M5 ;
        RECT  53.376 0 53.4 0.084 ;
    END
  END rec[384]
  PIN rec[385]
    DIRECTION INPUT ;
    USE SIGNAL ;
    PORT
      LAYER M5 ;
        RECT  53.424 0 53.448 0.084 ;
    END
  END rec[385]
  PIN rec[386]
    DIRECTION INPUT ;
    USE SIGNAL ;
    PORT
      LAYER M5 ;
        RECT  53.472 0 53.496 0.084 ;
    END
  END rec[386]
  PIN rec[387]
    DIRECTION INPUT ;
    USE SIGNAL ;
    PORT
      LAYER M5 ;
        RECT  53.52 0 53.544 0.084 ;
    END
  END rec[387]
  PIN rec[388]
    DIRECTION INPUT ;
    USE SIGNAL ;
    PORT
      LAYER M5 ;
        RECT  53.568 0 53.592 0.084 ;
    END
  END rec[388]
  PIN rec[389]
    DIRECTION INPUT ;
    USE SIGNAL ;
    PORT
      LAYER M5 ;
        RECT  53.616 0 53.64 0.084 ;
    END
  END rec[389]
  PIN rec[38]
    DIRECTION INPUT ;
    USE SIGNAL ;
    PORT
      LAYER M5 ;
        RECT  1.056 0 1.08 0.084 ;
    END
  END rec[38]
  PIN rec[390]
    DIRECTION INPUT ;
    USE SIGNAL ;
    PORT
      LAYER M5 ;
        RECT  53.664 0 53.688 0.084 ;
    END
  END rec[390]
  PIN rec[391]
    DIRECTION INPUT ;
    USE SIGNAL ;
    PORT
      LAYER M5 ;
        RECT  53.712 0 53.736 0.084 ;
    END
  END rec[391]
  PIN rec[392]
    DIRECTION INPUT ;
    USE SIGNAL ;
    PORT
      LAYER M5 ;
        RECT  53.76 0 53.784 0.084 ;
    END
  END rec[392]
  PIN rec[393]
    DIRECTION INPUT ;
    USE SIGNAL ;
    PORT
      LAYER M5 ;
        RECT  53.808 0 53.832 0.084 ;
    END
  END rec[393]
  PIN rec[394]
    DIRECTION INPUT ;
    USE SIGNAL ;
    PORT
      LAYER M5 ;
        RECT  53.856 0 53.88 0.084 ;
    END
  END rec[394]
  PIN rec[395]
    DIRECTION INPUT ;
    USE SIGNAL ;
    PORT
      LAYER M5 ;
        RECT  53.904 0 53.928 0.084 ;
    END
  END rec[395]
  PIN rec[396]
    DIRECTION INPUT ;
    USE SIGNAL ;
    PORT
      LAYER M5 ;
        RECT  53.952 0 53.976 0.084 ;
    END
  END rec[396]
  PIN rec[397]
    DIRECTION INPUT ;
    USE SIGNAL ;
    PORT
      LAYER M5 ;
        RECT  54 0 54.024 0.084 ;
    END
  END rec[397]
  PIN rec[398]
    DIRECTION INPUT ;
    USE SIGNAL ;
    PORT
      LAYER M5 ;
        RECT  54.048 0 54.072 0.084 ;
    END
  END rec[398]
  PIN rec[399]
    DIRECTION INPUT ;
    USE SIGNAL ;
    PORT
      LAYER M5 ;
        RECT  54.096 0 54.12 0.084 ;
    END
  END rec[399]
  PIN rec[39]
    DIRECTION INPUT ;
    USE SIGNAL ;
    PORT
      LAYER M5 ;
        RECT  1.104 0 1.128 0.084 ;
    END
  END rec[39]
  PIN rec[3]
    DIRECTION INPUT ;
    USE SIGNAL ;
    PORT
      LAYER M5 ;
        RECT  48.912 0 48.936 0.084 ;
    END
  END rec[3]
  PIN rec[400]
    DIRECTION INPUT ;
    USE SIGNAL ;
    PORT
      LAYER M5 ;
        RECT  54.144 0 54.168 0.084 ;
    END
  END rec[400]
  PIN rec[401]
    DIRECTION INPUT ;
    USE SIGNAL ;
    PORT
      LAYER M5 ;
        RECT  54.192 0 54.216 0.084 ;
    END
  END rec[401]
  PIN rec[402]
    DIRECTION INPUT ;
    USE SIGNAL ;
    PORT
      LAYER M5 ;
        RECT  54.24 0 54.264 0.084 ;
    END
  END rec[402]
  PIN rec[403]
    DIRECTION INPUT ;
    USE SIGNAL ;
    PORT
      LAYER M5 ;
        RECT  54.288 0 54.312 0.084 ;
    END
  END rec[403]
  PIN rec[404]
    DIRECTION INPUT ;
    USE SIGNAL ;
    PORT
      LAYER M5 ;
        RECT  54.336 0 54.36 0.084 ;
    END
  END rec[404]
  PIN rec[405]
    DIRECTION INPUT ;
    USE SIGNAL ;
    PORT
      LAYER M5 ;
        RECT  54.384 0 54.408 0.084 ;
    END
  END rec[405]
  PIN rec[406]
    DIRECTION INPUT ;
    USE SIGNAL ;
    PORT
      LAYER M5 ;
        RECT  54.432 0 54.456 0.084 ;
    END
  END rec[406]
  PIN rec[407]
    DIRECTION INPUT ;
    USE SIGNAL ;
    PORT
      LAYER M5 ;
        RECT  54.48 0 54.504 0.084 ;
    END
  END rec[407]
  PIN rec[408]
    DIRECTION INPUT ;
    USE SIGNAL ;
    PORT
      LAYER M5 ;
        RECT  54.528 0 54.552 0.084 ;
    END
  END rec[408]
  PIN rec[409]
    DIRECTION INPUT ;
    USE SIGNAL ;
    PORT
      LAYER M5 ;
        RECT  54.576 0 54.6 0.084 ;
    END
  END rec[409]
  PIN rec[40]
    DIRECTION INPUT ;
    USE SIGNAL ;
    PORT
      LAYER M5 ;
        RECT  1.152 0 1.176 0.084 ;
    END
  END rec[40]
  PIN rec[410]
    DIRECTION INPUT ;
    USE SIGNAL ;
    PORT
      LAYER M5 ;
        RECT  54.624 0 54.648 0.084 ;
    END
  END rec[410]
  PIN rec[411]
    DIRECTION INPUT ;
    USE SIGNAL ;
    PORT
      LAYER M5 ;
        RECT  54.672 0 54.696 0.084 ;
    END
  END rec[411]
  PIN rec[412]
    DIRECTION INPUT ;
    USE SIGNAL ;
    PORT
      LAYER M5 ;
        RECT  54.72 0 54.744 0.084 ;
    END
  END rec[412]
  PIN rec[413]
    DIRECTION INPUT ;
    USE SIGNAL ;
    PORT
      LAYER M5 ;
        RECT  54.768 0 54.792 0.084 ;
    END
  END rec[413]
  PIN rec[414]
    DIRECTION INPUT ;
    USE SIGNAL ;
    PORT
      LAYER M5 ;
        RECT  54.816 0 54.84 0.084 ;
    END
  END rec[414]
  PIN rec[415]
    DIRECTION INPUT ;
    USE SIGNAL ;
    PORT
      LAYER M5 ;
        RECT  46.8 0 46.824 0.084 ;
    END
  END rec[415]
  PIN rec[416]
    DIRECTION INPUT ;
    USE SIGNAL ;
    PORT
      LAYER M5 ;
        RECT  46.848 0 46.872 0.084 ;
    END
  END rec[416]
  PIN rec[417]
    DIRECTION INPUT ;
    USE SIGNAL ;
    PORT
      LAYER M5 ;
        RECT  46.896 0 46.92 0.084 ;
    END
  END rec[417]
  PIN rec[418]
    DIRECTION INPUT ;
    USE SIGNAL ;
    PORT
      LAYER M5 ;
        RECT  46.944 0 46.968 0.084 ;
    END
  END rec[418]
  PIN rec[419]
    DIRECTION INPUT ;
    USE SIGNAL ;
    PORT
      LAYER M5 ;
        RECT  46.992 0 47.016 0.084 ;
    END
  END rec[419]
  PIN rec[41]
    DIRECTION INPUT ;
    USE SIGNAL ;
    PORT
      LAYER M5 ;
        RECT  1.2 0 1.224 0.084 ;
    END
  END rec[41]
  PIN rec[420]
    DIRECTION INPUT ;
    USE SIGNAL ;
    PORT
      LAYER M5 ;
        RECT  47.04 0 47.064 0.084 ;
    END
  END rec[420]
  PIN rec[421]
    DIRECTION INPUT ;
    USE SIGNAL ;
    PORT
      LAYER M5 ;
        RECT  47.088 0 47.112 0.084 ;
    END
  END rec[421]
  PIN rec[422]
    DIRECTION INPUT ;
    USE SIGNAL ;
    PORT
      LAYER M5 ;
        RECT  47.136 0 47.16 0.084 ;
    END
  END rec[422]
  PIN rec[423]
    DIRECTION INPUT ;
    USE SIGNAL ;
    PORT
      LAYER M5 ;
        RECT  47.184 0 47.208 0.084 ;
    END
  END rec[423]
  PIN rec[424]
    DIRECTION INPUT ;
    USE SIGNAL ;
    PORT
      LAYER M5 ;
        RECT  47.232 0 47.256 0.084 ;
    END
  END rec[424]
  PIN rec[425]
    DIRECTION INPUT ;
    USE SIGNAL ;
    PORT
      LAYER M5 ;
        RECT  47.28 0 47.304 0.084 ;
    END
  END rec[425]
  PIN rec[426]
    DIRECTION INPUT ;
    USE SIGNAL ;
    PORT
      LAYER M5 ;
        RECT  47.328 0 47.352 0.084 ;
    END
  END rec[426]
  PIN rec[427]
    DIRECTION INPUT ;
    USE SIGNAL ;
    PORT
      LAYER M5 ;
        RECT  47.376 0 47.4 0.084 ;
    END
  END rec[427]
  PIN rec[428]
    DIRECTION INPUT ;
    USE SIGNAL ;
    PORT
      LAYER M5 ;
        RECT  47.424 0 47.448 0.084 ;
    END
  END rec[428]
  PIN rec[429]
    DIRECTION INPUT ;
    USE SIGNAL ;
    PORT
      LAYER M5 ;
        RECT  47.472 0 47.496 0.084 ;
    END
  END rec[429]
  PIN rec[42]
    DIRECTION INPUT ;
    USE SIGNAL ;
    PORT
      LAYER M5 ;
        RECT  1.248 0 1.272 0.084 ;
    END
  END rec[42]
  PIN rec[430]
    DIRECTION INPUT ;
    USE SIGNAL ;
    PORT
      LAYER M5 ;
        RECT  47.52 0 47.544 0.084 ;
    END
  END rec[430]
  PIN rec[431]
    DIRECTION INPUT ;
    USE SIGNAL ;
    PORT
      LAYER M5 ;
        RECT  47.568 0 47.592 0.084 ;
    END
  END rec[431]
  PIN rec[432]
    DIRECTION INPUT ;
    USE SIGNAL ;
    PORT
      LAYER M5 ;
        RECT  47.616 0 47.64 0.084 ;
    END
  END rec[432]
  PIN rec[433]
    DIRECTION INPUT ;
    USE SIGNAL ;
    PORT
      LAYER M5 ;
        RECT  47.664 0 47.688 0.084 ;
    END
  END rec[433]
  PIN rec[434]
    DIRECTION INPUT ;
    USE SIGNAL ;
    PORT
      LAYER M5 ;
        RECT  47.712 0 47.736 0.084 ;
    END
  END rec[434]
  PIN rec[435]
    DIRECTION INPUT ;
    USE SIGNAL ;
    PORT
      LAYER M5 ;
        RECT  47.76 0 47.784 0.084 ;
    END
  END rec[435]
  PIN rec[436]
    DIRECTION INPUT ;
    USE SIGNAL ;
    PORT
      LAYER M5 ;
        RECT  47.808 0 47.832 0.084 ;
    END
  END rec[436]
  PIN rec[437]
    DIRECTION INPUT ;
    USE SIGNAL ;
    PORT
      LAYER M5 ;
        RECT  47.856 0 47.88 0.084 ;
    END
  END rec[437]
  PIN rec[438]
    DIRECTION INPUT ;
    USE SIGNAL ;
    PORT
      LAYER M5 ;
        RECT  47.904 0 47.928 0.084 ;
    END
  END rec[438]
  PIN rec[439]
    DIRECTION INPUT ;
    USE SIGNAL ;
    PORT
      LAYER M5 ;
        RECT  47.952 0 47.976 0.084 ;
    END
  END rec[439]
  PIN rec[43]
    DIRECTION INPUT ;
    USE SIGNAL ;
    PORT
      LAYER M5 ;
        RECT  1.296 0 1.32 0.084 ;
    END
  END rec[43]
  PIN rec[440]
    DIRECTION INPUT ;
    USE SIGNAL ;
    PORT
      LAYER M5 ;
        RECT  48 0 48.024 0.084 ;
    END
  END rec[440]
  PIN rec[441]
    DIRECTION INPUT ;
    USE SIGNAL ;
    PORT
      LAYER M5 ;
        RECT  48.048 0 48.072 0.084 ;
    END
  END rec[441]
  PIN rec[442]
    DIRECTION INPUT ;
    USE SIGNAL ;
    PORT
      LAYER M5 ;
        RECT  48.096 0 48.12 0.084 ;
    END
  END rec[442]
  PIN rec[443]
    DIRECTION INPUT ;
    USE SIGNAL ;
    PORT
      LAYER M5 ;
        RECT  48.144 0 48.168 0.084 ;
    END
  END rec[443]
  PIN rec[444]
    DIRECTION INPUT ;
    USE SIGNAL ;
    PORT
      LAYER M5 ;
        RECT  48.192 0 48.216 0.084 ;
    END
  END rec[444]
  PIN rec[445]
    DIRECTION INPUT ;
    USE SIGNAL ;
    PORT
      LAYER M5 ;
        RECT  48.24 0 48.264 0.084 ;
    END
  END rec[445]
  PIN rec[446]
    DIRECTION INPUT ;
    USE SIGNAL ;
    PORT
      LAYER M5 ;
        RECT  48.288 0 48.312 0.084 ;
    END
  END rec[446]
  PIN rec[447]
    DIRECTION INPUT ;
    USE SIGNAL ;
    PORT
      LAYER M5 ;
        RECT  69.456 0 69.48 0.084 ;
    END
  END rec[447]
  PIN rec[448]
    DIRECTION INPUT ;
    USE SIGNAL ;
    PORT
      LAYER M5 ;
        RECT  69.504 0 69.528 0.084 ;
    END
  END rec[448]
  PIN rec[449]
    DIRECTION INPUT ;
    USE SIGNAL ;
    PORT
      LAYER M5 ;
        RECT  69.552 0 69.576 0.084 ;
    END
  END rec[449]
  PIN rec[44]
    DIRECTION INPUT ;
    USE SIGNAL ;
    PORT
      LAYER M5 ;
        RECT  1.344 0 1.368 0.084 ;
    END
  END rec[44]
  PIN rec[450]
    DIRECTION INPUT ;
    USE SIGNAL ;
    PORT
      LAYER M5 ;
        RECT  69.6 0 69.624 0.084 ;
    END
  END rec[450]
  PIN rec[451]
    DIRECTION INPUT ;
    USE SIGNAL ;
    PORT
      LAYER M5 ;
        RECT  69.648 0 69.672 0.084 ;
    END
  END rec[451]
  PIN rec[452]
    DIRECTION INPUT ;
    USE SIGNAL ;
    PORT
      LAYER M5 ;
        RECT  69.696 0 69.72 0.084 ;
    END
  END rec[452]
  PIN rec[453]
    DIRECTION INPUT ;
    USE SIGNAL ;
    PORT
      LAYER M5 ;
        RECT  69.744 0 69.768 0.084 ;
    END
  END rec[453]
  PIN rec[454]
    DIRECTION INPUT ;
    USE SIGNAL ;
    PORT
      LAYER M5 ;
        RECT  69.792 0 69.816 0.084 ;
    END
  END rec[454]
  PIN rec[455]
    DIRECTION INPUT ;
    USE SIGNAL ;
    PORT
      LAYER M5 ;
        RECT  69.84 0 69.864 0.084 ;
    END
  END rec[455]
  PIN rec[456]
    DIRECTION INPUT ;
    USE SIGNAL ;
    PORT
      LAYER M5 ;
        RECT  69.888 0 69.912 0.084 ;
    END
  END rec[456]
  PIN rec[457]
    DIRECTION INPUT ;
    USE SIGNAL ;
    PORT
      LAYER M5 ;
        RECT  69.936 0 69.96 0.084 ;
    END
  END rec[457]
  PIN rec[458]
    DIRECTION INPUT ;
    USE SIGNAL ;
    PORT
      LAYER M5 ;
        RECT  69.984 0 70.008 0.084 ;
    END
  END rec[458]
  PIN rec[459]
    DIRECTION INPUT ;
    USE SIGNAL ;
    PORT
      LAYER M5 ;
        RECT  70.032 0 70.056 0.084 ;
    END
  END rec[459]
  PIN rec[45]
    DIRECTION INPUT ;
    USE SIGNAL ;
    PORT
      LAYER M5 ;
        RECT  1.392 0 1.416 0.084 ;
    END
  END rec[45]
  PIN rec[460]
    DIRECTION INPUT ;
    USE SIGNAL ;
    PORT
      LAYER M5 ;
        RECT  70.08 0 70.104 0.084 ;
    END
  END rec[460]
  PIN rec[461]
    DIRECTION INPUT ;
    USE SIGNAL ;
    PORT
      LAYER M5 ;
        RECT  70.128 0 70.152 0.084 ;
    END
  END rec[461]
  PIN rec[462]
    DIRECTION INPUT ;
    USE SIGNAL ;
    PORT
      LAYER M5 ;
        RECT  70.176 0 70.2 0.084 ;
    END
  END rec[462]
  PIN rec[463]
    DIRECTION INPUT ;
    USE SIGNAL ;
    PORT
      LAYER M5 ;
        RECT  70.224 0 70.248 0.084 ;
    END
  END rec[463]
  PIN rec[464]
    DIRECTION INPUT ;
    USE SIGNAL ;
    PORT
      LAYER M5 ;
        RECT  70.272 0 70.296 0.084 ;
    END
  END rec[464]
  PIN rec[465]
    DIRECTION INPUT ;
    USE SIGNAL ;
    PORT
      LAYER M5 ;
        RECT  70.32 0 70.344 0.084 ;
    END
  END rec[465]
  PIN rec[466]
    DIRECTION INPUT ;
    USE SIGNAL ;
    PORT
      LAYER M5 ;
        RECT  70.368 0 70.392 0.084 ;
    END
  END rec[466]
  PIN rec[467]
    DIRECTION INPUT ;
    USE SIGNAL ;
    PORT
      LAYER M5 ;
        RECT  70.416 0 70.44 0.084 ;
    END
  END rec[467]
  PIN rec[468]
    DIRECTION INPUT ;
    USE SIGNAL ;
    PORT
      LAYER M5 ;
        RECT  70.464 0 70.488 0.084 ;
    END
  END rec[468]
  PIN rec[469]
    DIRECTION INPUT ;
    USE SIGNAL ;
    PORT
      LAYER M5 ;
        RECT  70.512 0 70.536 0.084 ;
    END
  END rec[469]
  PIN rec[46]
    DIRECTION INPUT ;
    USE SIGNAL ;
    PORT
      LAYER M5 ;
        RECT  1.44 0 1.464 0.084 ;
    END
  END rec[46]
  PIN rec[470]
    DIRECTION INPUT ;
    USE SIGNAL ;
    PORT
      LAYER M5 ;
        RECT  70.56 0 70.584 0.084 ;
    END
  END rec[470]
  PIN rec[471]
    DIRECTION INPUT ;
    USE SIGNAL ;
    PORT
      LAYER M5 ;
        RECT  70.608 0 70.632 0.084 ;
    END
  END rec[471]
  PIN rec[472]
    DIRECTION INPUT ;
    USE SIGNAL ;
    PORT
      LAYER M5 ;
        RECT  70.656 0 70.68 0.084 ;
    END
  END rec[472]
  PIN rec[473]
    DIRECTION INPUT ;
    USE SIGNAL ;
    PORT
      LAYER M5 ;
        RECT  70.704 0 70.728 0.084 ;
    END
  END rec[473]
  PIN rec[474]
    DIRECTION INPUT ;
    USE SIGNAL ;
    PORT
      LAYER M5 ;
        RECT  70.752 0 70.776 0.084 ;
    END
  END rec[474]
  PIN rec[475]
    DIRECTION INPUT ;
    USE SIGNAL ;
    PORT
      LAYER M5 ;
        RECT  70.8 0 70.824 0.084 ;
    END
  END rec[475]
  PIN rec[476]
    DIRECTION INPUT ;
    USE SIGNAL ;
    PORT
      LAYER M5 ;
        RECT  70.848 0 70.872 0.084 ;
    END
  END rec[476]
  PIN rec[477]
    DIRECTION INPUT ;
    USE SIGNAL ;
    PORT
      LAYER M5 ;
        RECT  70.896 0 70.92 0.084 ;
    END
  END rec[477]
  PIN rec[478]
    DIRECTION INPUT ;
    USE SIGNAL ;
    PORT
      LAYER M5 ;
        RECT  70.944 0 70.968 0.084 ;
    END
  END rec[478]
  PIN rec[479]
    DIRECTION INPUT ;
    USE SIGNAL ;
    PORT
      LAYER M5 ;
        RECT  61.392 0 61.416 0.084 ;
    END
  END rec[479]
  PIN rec[47]
    DIRECTION INPUT ;
    USE SIGNAL ;
    PORT
      LAYER M5 ;
        RECT  1.488 0 1.512 0.084 ;
    END
  END rec[47]
  PIN rec[480]
    DIRECTION INPUT ;
    USE SIGNAL ;
    PORT
      LAYER M5 ;
        RECT  61.44 0 61.464 0.084 ;
    END
  END rec[480]
  PIN rec[481]
    DIRECTION INPUT ;
    USE SIGNAL ;
    PORT
      LAYER M5 ;
        RECT  61.488 0 61.512 0.084 ;
    END
  END rec[481]
  PIN rec[482]
    DIRECTION INPUT ;
    USE SIGNAL ;
    PORT
      LAYER M5 ;
        RECT  61.536 0 61.56 0.084 ;
    END
  END rec[482]
  PIN rec[483]
    DIRECTION INPUT ;
    USE SIGNAL ;
    PORT
      LAYER M5 ;
        RECT  61.584 0 61.608 0.084 ;
    END
  END rec[483]
  PIN rec[484]
    DIRECTION INPUT ;
    USE SIGNAL ;
    PORT
      LAYER M5 ;
        RECT  61.632 0 61.656 0.084 ;
    END
  END rec[484]
  PIN rec[485]
    DIRECTION INPUT ;
    USE SIGNAL ;
    PORT
      LAYER M5 ;
        RECT  61.68 0 61.704 0.084 ;
    END
  END rec[485]
  PIN rec[486]
    DIRECTION INPUT ;
    USE SIGNAL ;
    PORT
      LAYER M5 ;
        RECT  61.728 0 61.752 0.084 ;
    END
  END rec[486]
  PIN rec[487]
    DIRECTION INPUT ;
    USE SIGNAL ;
    PORT
      LAYER M5 ;
        RECT  61.776 0 61.8 0.084 ;
    END
  END rec[487]
  PIN rec[488]
    DIRECTION INPUT ;
    USE SIGNAL ;
    PORT
      LAYER M5 ;
        RECT  61.824 0 61.848 0.084 ;
    END
  END rec[488]
  PIN rec[489]
    DIRECTION INPUT ;
    USE SIGNAL ;
    PORT
      LAYER M5 ;
        RECT  61.872 0 61.896 0.084 ;
    END
  END rec[489]
  PIN rec[48]
    DIRECTION INPUT ;
    USE SIGNAL ;
    PORT
      LAYER M5 ;
        RECT  1.536 0 1.56 0.084 ;
    END
  END rec[48]
  PIN rec[490]
    DIRECTION INPUT ;
    USE SIGNAL ;
    PORT
      LAYER M5 ;
        RECT  61.92 0 61.944 0.084 ;
    END
  END rec[490]
  PIN rec[491]
    DIRECTION INPUT ;
    USE SIGNAL ;
    PORT
      LAYER M5 ;
        RECT  61.968 0 61.992 0.084 ;
    END
  END rec[491]
  PIN rec[492]
    DIRECTION INPUT ;
    USE SIGNAL ;
    PORT
      LAYER M5 ;
        RECT  62.016 0 62.04 0.084 ;
    END
  END rec[492]
  PIN rec[493]
    DIRECTION INPUT ;
    USE SIGNAL ;
    PORT
      LAYER M5 ;
        RECT  62.064 0 62.088 0.084 ;
    END
  END rec[493]
  PIN rec[494]
    DIRECTION INPUT ;
    USE SIGNAL ;
    PORT
      LAYER M5 ;
        RECT  62.112 0 62.136 0.084 ;
    END
  END rec[494]
  PIN rec[495]
    DIRECTION INPUT ;
    USE SIGNAL ;
    PORT
      LAYER M5 ;
        RECT  62.16 0 62.184 0.084 ;
    END
  END rec[495]
  PIN rec[496]
    DIRECTION INPUT ;
    USE SIGNAL ;
    PORT
      LAYER M5 ;
        RECT  62.208 0 62.232 0.084 ;
    END
  END rec[496]
  PIN rec[497]
    DIRECTION INPUT ;
    USE SIGNAL ;
    PORT
      LAYER M5 ;
        RECT  62.256 0 62.28 0.084 ;
    END
  END rec[497]
  PIN rec[498]
    DIRECTION INPUT ;
    USE SIGNAL ;
    PORT
      LAYER M5 ;
        RECT  62.304 0 62.328 0.084 ;
    END
  END rec[498]
  PIN rec[499]
    DIRECTION INPUT ;
    USE SIGNAL ;
    PORT
      LAYER M5 ;
        RECT  62.352 0 62.376 0.084 ;
    END
  END rec[499]
  PIN rec[49]
    DIRECTION INPUT ;
    USE SIGNAL ;
    PORT
      LAYER M5 ;
        RECT  1.584 0 1.608 0.084 ;
    END
  END rec[49]
  PIN rec[4]
    DIRECTION INPUT ;
    USE SIGNAL ;
    PORT
      LAYER M5 ;
        RECT  48.96 0 48.984 0.084 ;
    END
  END rec[4]
  PIN rec[500]
    DIRECTION INPUT ;
    USE SIGNAL ;
    PORT
      LAYER M5 ;
        RECT  62.4 0 62.424 0.084 ;
    END
  END rec[500]
  PIN rec[501]
    DIRECTION INPUT ;
    USE SIGNAL ;
    PORT
      LAYER M5 ;
        RECT  62.448 0 62.472 0.084 ;
    END
  END rec[501]
  PIN rec[502]
    DIRECTION INPUT ;
    USE SIGNAL ;
    PORT
      LAYER M5 ;
        RECT  62.496 0 62.52 0.084 ;
    END
  END rec[502]
  PIN rec[503]
    DIRECTION INPUT ;
    USE SIGNAL ;
    PORT
      LAYER M5 ;
        RECT  62.544 0 62.568 0.084 ;
    END
  END rec[503]
  PIN rec[504]
    DIRECTION INPUT ;
    USE SIGNAL ;
    PORT
      LAYER M5 ;
        RECT  62.592 0 62.616 0.084 ;
    END
  END rec[504]
  PIN rec[505]
    DIRECTION INPUT ;
    USE SIGNAL ;
    PORT
      LAYER M5 ;
        RECT  62.64 0 62.664 0.084 ;
    END
  END rec[505]
  PIN rec[506]
    DIRECTION INPUT ;
    USE SIGNAL ;
    PORT
      LAYER M5 ;
        RECT  62.688 0 62.712 0.084 ;
    END
  END rec[506]
  PIN rec[507]
    DIRECTION INPUT ;
    USE SIGNAL ;
    PORT
      LAYER M5 ;
        RECT  62.736 0 62.76 0.084 ;
    END
  END rec[507]
  PIN rec[508]
    DIRECTION INPUT ;
    USE SIGNAL ;
    PORT
      LAYER M5 ;
        RECT  62.784 0 62.808 0.084 ;
    END
  END rec[508]
  PIN rec[509]
    DIRECTION INPUT ;
    USE SIGNAL ;
    PORT
      LAYER M5 ;
        RECT  62.832 0 62.856 0.084 ;
    END
  END rec[509]
  PIN rec[50]
    DIRECTION INPUT ;
    USE SIGNAL ;
    PORT
      LAYER M5 ;
        RECT  1.632 0 1.656 0.084 ;
    END
  END rec[50]
  PIN rec[510]
    DIRECTION INPUT ;
    USE SIGNAL ;
    PORT
      LAYER M5 ;
        RECT  62.88 0 62.904 0.084 ;
    END
  END rec[510]
  PIN rec[511]
    DIRECTION INPUT ;
    USE SIGNAL ;
    PORT
      LAYER M5 ;
        RECT  77.52 0 77.544 0.084 ;
    END
  END rec[511]
  PIN rec[512]
    DIRECTION INPUT ;
    USE SIGNAL ;
    PORT
      LAYER M5 ;
        RECT  77.568 0 77.592 0.084 ;
    END
  END rec[512]
  PIN rec[513]
    DIRECTION INPUT ;
    USE SIGNAL ;
    PORT
      LAYER M5 ;
        RECT  77.616 0 77.64 0.084 ;
    END
  END rec[513]
  PIN rec[514]
    DIRECTION INPUT ;
    USE SIGNAL ;
    PORT
      LAYER M5 ;
        RECT  77.664 0 77.688 0.084 ;
    END
  END rec[514]
  PIN rec[515]
    DIRECTION INPUT ;
    USE SIGNAL ;
    PORT
      LAYER M5 ;
        RECT  77.712 0 77.736 0.084 ;
    END
  END rec[515]
  PIN rec[516]
    DIRECTION INPUT ;
    USE SIGNAL ;
    PORT
      LAYER M5 ;
        RECT  77.76 0 77.784 0.084 ;
    END
  END rec[516]
  PIN rec[517]
    DIRECTION INPUT ;
    USE SIGNAL ;
    PORT
      LAYER M5 ;
        RECT  77.808 0 77.832 0.084 ;
    END
  END rec[517]
  PIN rec[518]
    DIRECTION INPUT ;
    USE SIGNAL ;
    PORT
      LAYER M5 ;
        RECT  77.856 0 77.88 0.084 ;
    END
  END rec[518]
  PIN rec[519]
    DIRECTION INPUT ;
    USE SIGNAL ;
    PORT
      LAYER M5 ;
        RECT  77.904 0 77.928 0.084 ;
    END
  END rec[519]
  PIN rec[51]
    DIRECTION INPUT ;
    USE SIGNAL ;
    PORT
      LAYER M5 ;
        RECT  1.68 0 1.704 0.084 ;
    END
  END rec[51]
  PIN rec[520]
    DIRECTION INPUT ;
    USE SIGNAL ;
    PORT
      LAYER M5 ;
        RECT  77.952 0 77.976 0.084 ;
    END
  END rec[520]
  PIN rec[521]
    DIRECTION INPUT ;
    USE SIGNAL ;
    PORT
      LAYER M5 ;
        RECT  78 0 78.024 0.084 ;
    END
  END rec[521]
  PIN rec[522]
    DIRECTION INPUT ;
    USE SIGNAL ;
    PORT
      LAYER M5 ;
        RECT  78.048 0 78.072 0.084 ;
    END
  END rec[522]
  PIN rec[523]
    DIRECTION INPUT ;
    USE SIGNAL ;
    PORT
      LAYER M5 ;
        RECT  78.096 0 78.12 0.084 ;
    END
  END rec[523]
  PIN rec[524]
    DIRECTION INPUT ;
    USE SIGNAL ;
    PORT
      LAYER M5 ;
        RECT  78.144 0 78.168 0.084 ;
    END
  END rec[524]
  PIN rec[525]
    DIRECTION INPUT ;
    USE SIGNAL ;
    PORT
      LAYER M5 ;
        RECT  78.192 0 78.216 0.084 ;
    END
  END rec[525]
  PIN rec[526]
    DIRECTION INPUT ;
    USE SIGNAL ;
    PORT
      LAYER M5 ;
        RECT  78.24 0 78.264 0.084 ;
    END
  END rec[526]
  PIN rec[527]
    DIRECTION INPUT ;
    USE SIGNAL ;
    PORT
      LAYER M5 ;
        RECT  78.288 0 78.312 0.084 ;
    END
  END rec[527]
  PIN rec[528]
    DIRECTION INPUT ;
    USE SIGNAL ;
    PORT
      LAYER M5 ;
        RECT  78.336 0 78.36 0.084 ;
    END
  END rec[528]
  PIN rec[529]
    DIRECTION INPUT ;
    USE SIGNAL ;
    PORT
      LAYER M5 ;
        RECT  78.384 0 78.408 0.084 ;
    END
  END rec[529]
  PIN rec[52]
    DIRECTION INPUT ;
    USE SIGNAL ;
    PORT
      LAYER M5 ;
        RECT  1.728 0 1.752 0.084 ;
    END
  END rec[52]
  PIN rec[530]
    DIRECTION INPUT ;
    USE SIGNAL ;
    PORT
      LAYER M5 ;
        RECT  78.432 0 78.456 0.084 ;
    END
  END rec[530]
  PIN rec[531]
    DIRECTION INPUT ;
    USE SIGNAL ;
    PORT
      LAYER M5 ;
        RECT  78.48 0 78.504 0.084 ;
    END
  END rec[531]
  PIN rec[532]
    DIRECTION INPUT ;
    USE SIGNAL ;
    PORT
      LAYER M5 ;
        RECT  78.528 0 78.552 0.084 ;
    END
  END rec[532]
  PIN rec[533]
    DIRECTION INPUT ;
    USE SIGNAL ;
    PORT
      LAYER M5 ;
        RECT  78.576 0 78.6 0.084 ;
    END
  END rec[533]
  PIN rec[534]
    DIRECTION INPUT ;
    USE SIGNAL ;
    PORT
      LAYER M5 ;
        RECT  78.624 0 78.648 0.084 ;
    END
  END rec[534]
  PIN rec[535]
    DIRECTION INPUT ;
    USE SIGNAL ;
    PORT
      LAYER M5 ;
        RECT  78.672 0 78.696 0.084 ;
    END
  END rec[535]
  PIN rec[536]
    DIRECTION INPUT ;
    USE SIGNAL ;
    PORT
      LAYER M5 ;
        RECT  78.72 0 78.744 0.084 ;
    END
  END rec[536]
  PIN rec[537]
    DIRECTION INPUT ;
    USE SIGNAL ;
    PORT
      LAYER M5 ;
        RECT  78.768 0 78.792 0.084 ;
    END
  END rec[537]
  PIN rec[538]
    DIRECTION INPUT ;
    USE SIGNAL ;
    PORT
      LAYER M5 ;
        RECT  78.816 0 78.84 0.084 ;
    END
  END rec[538]
  PIN rec[539]
    DIRECTION INPUT ;
    USE SIGNAL ;
    PORT
      LAYER M5 ;
        RECT  78.864 0 78.888 0.084 ;
    END
  END rec[539]
  PIN rec[53]
    DIRECTION INPUT ;
    USE SIGNAL ;
    PORT
      LAYER M5 ;
        RECT  1.776 0 1.8 0.084 ;
    END
  END rec[53]
  PIN rec[540]
    DIRECTION INPUT ;
    USE SIGNAL ;
    PORT
      LAYER M5 ;
        RECT  78.912 0 78.936 0.084 ;
    END
  END rec[540]
  PIN rec[541]
    DIRECTION INPUT ;
    USE SIGNAL ;
    PORT
      LAYER M5 ;
        RECT  78.96 0 78.984 0.084 ;
    END
  END rec[541]
  PIN rec[542]
    DIRECTION INPUT ;
    USE SIGNAL ;
    PORT
      LAYER M5 ;
        RECT  79.008 0 79.032 0.084 ;
    END
  END rec[542]
  PIN rec[543]
    DIRECTION INPUT ;
    USE SIGNAL ;
    PORT
      LAYER M5 ;
        RECT  87.12 0 87.144 0.084 ;
    END
  END rec[543]
  PIN rec[544]
    DIRECTION INPUT ;
    USE SIGNAL ;
    PORT
      LAYER M5 ;
        RECT  87.168 0 87.192 0.084 ;
    END
  END rec[544]
  PIN rec[545]
    DIRECTION INPUT ;
    USE SIGNAL ;
    PORT
      LAYER M5 ;
        RECT  87.216 0 87.24 0.084 ;
    END
  END rec[545]
  PIN rec[546]
    DIRECTION INPUT ;
    USE SIGNAL ;
    PORT
      LAYER M5 ;
        RECT  87.264 0 87.288 0.084 ;
    END
  END rec[546]
  PIN rec[547]
    DIRECTION INPUT ;
    USE SIGNAL ;
    PORT
      LAYER M5 ;
        RECT  87.312 0 87.336 0.084 ;
    END
  END rec[547]
  PIN rec[548]
    DIRECTION INPUT ;
    USE SIGNAL ;
    PORT
      LAYER M5 ;
        RECT  87.36 0 87.384 0.084 ;
    END
  END rec[548]
  PIN rec[549]
    DIRECTION INPUT ;
    USE SIGNAL ;
    PORT
      LAYER M5 ;
        RECT  87.408 0 87.432 0.084 ;
    END
  END rec[549]
  PIN rec[54]
    DIRECTION INPUT ;
    USE SIGNAL ;
    PORT
      LAYER M5 ;
        RECT  1.824 0 1.848 0.084 ;
    END
  END rec[54]
  PIN rec[550]
    DIRECTION INPUT ;
    USE SIGNAL ;
    PORT
      LAYER M5 ;
        RECT  87.456 0 87.48 0.084 ;
    END
  END rec[550]
  PIN rec[551]
    DIRECTION INPUT ;
    USE SIGNAL ;
    PORT
      LAYER M5 ;
        RECT  87.504 0 87.528 0.084 ;
    END
  END rec[551]
  PIN rec[552]
    DIRECTION INPUT ;
    USE SIGNAL ;
    PORT
      LAYER M5 ;
        RECT  87.552 0 87.576 0.084 ;
    END
  END rec[552]
  PIN rec[553]
    DIRECTION INPUT ;
    USE SIGNAL ;
    PORT
      LAYER M5 ;
        RECT  87.6 0 87.624 0.084 ;
    END
  END rec[553]
  PIN rec[554]
    DIRECTION INPUT ;
    USE SIGNAL ;
    PORT
      LAYER M5 ;
        RECT  87.648 0 87.672 0.084 ;
    END
  END rec[554]
  PIN rec[555]
    DIRECTION INPUT ;
    USE SIGNAL ;
    PORT
      LAYER M5 ;
        RECT  87.696 0 87.72 0.084 ;
    END
  END rec[555]
  PIN rec[556]
    DIRECTION INPUT ;
    USE SIGNAL ;
    PORT
      LAYER M5 ;
        RECT  87.744 0 87.768 0.084 ;
    END
  END rec[556]
  PIN rec[557]
    DIRECTION INPUT ;
    USE SIGNAL ;
    PORT
      LAYER M5 ;
        RECT  87.792 0 87.816 0.084 ;
    END
  END rec[557]
  PIN rec[558]
    DIRECTION INPUT ;
    USE SIGNAL ;
    PORT
      LAYER M5 ;
        RECT  87.84 0 87.864 0.084 ;
    END
  END rec[558]
  PIN rec[559]
    DIRECTION INPUT ;
    USE SIGNAL ;
    PORT
      LAYER M5 ;
        RECT  87.888 0 87.912 0.084 ;
    END
  END rec[559]
  PIN rec[55]
    DIRECTION INPUT ;
    USE SIGNAL ;
    PORT
      LAYER M5 ;
        RECT  1.872 0 1.896 0.084 ;
    END
  END rec[55]
  PIN rec[560]
    DIRECTION INPUT ;
    USE SIGNAL ;
    PORT
      LAYER M5 ;
        RECT  87.936 0 87.96 0.084 ;
    END
  END rec[560]
  PIN rec[561]
    DIRECTION INPUT ;
    USE SIGNAL ;
    PORT
      LAYER M5 ;
        RECT  87.984 0 88.008 0.084 ;
    END
  END rec[561]
  PIN rec[562]
    DIRECTION INPUT ;
    USE SIGNAL ;
    PORT
      LAYER M5 ;
        RECT  88.032 0 88.056 0.084 ;
    END
  END rec[562]
  PIN rec[563]
    DIRECTION INPUT ;
    USE SIGNAL ;
    PORT
      LAYER M5 ;
        RECT  88.08 0 88.104 0.084 ;
    END
  END rec[563]
  PIN rec[564]
    DIRECTION INPUT ;
    USE SIGNAL ;
    PORT
      LAYER M5 ;
        RECT  88.128 0 88.152 0.084 ;
    END
  END rec[564]
  PIN rec[565]
    DIRECTION INPUT ;
    USE SIGNAL ;
    PORT
      LAYER M5 ;
        RECT  88.176 0 88.2 0.084 ;
    END
  END rec[565]
  PIN rec[566]
    DIRECTION INPUT ;
    USE SIGNAL ;
    PORT
      LAYER M5 ;
        RECT  88.224 0 88.248 0.084 ;
    END
  END rec[566]
  PIN rec[567]
    DIRECTION INPUT ;
    USE SIGNAL ;
    PORT
      LAYER M5 ;
        RECT  88.272 0 88.296 0.084 ;
    END
  END rec[567]
  PIN rec[568]
    DIRECTION INPUT ;
    USE SIGNAL ;
    PORT
      LAYER M5 ;
        RECT  88.32 0 88.344 0.084 ;
    END
  END rec[568]
  PIN rec[569]
    DIRECTION INPUT ;
    USE SIGNAL ;
    PORT
      LAYER M5 ;
        RECT  88.368 0 88.392 0.084 ;
    END
  END rec[569]
  PIN rec[56]
    DIRECTION INPUT ;
    USE SIGNAL ;
    PORT
      LAYER M5 ;
        RECT  1.92 0 1.944 0.084 ;
    END
  END rec[56]
  PIN rec[570]
    DIRECTION INPUT ;
    USE SIGNAL ;
    PORT
      LAYER M5 ;
        RECT  88.416 0 88.44 0.084 ;
    END
  END rec[570]
  PIN rec[571]
    DIRECTION INPUT ;
    USE SIGNAL ;
    PORT
      LAYER M5 ;
        RECT  88.464 0 88.488 0.084 ;
    END
  END rec[571]
  PIN rec[572]
    DIRECTION INPUT ;
    USE SIGNAL ;
    PORT
      LAYER M5 ;
        RECT  88.512 0 88.536 0.084 ;
    END
  END rec[572]
  PIN rec[573]
    DIRECTION INPUT ;
    USE SIGNAL ;
    PORT
      LAYER M5 ;
        RECT  88.56 0 88.584 0.084 ;
    END
  END rec[573]
  PIN rec[574]
    DIRECTION INPUT ;
    USE SIGNAL ;
    PORT
      LAYER M5 ;
        RECT  88.608 0 88.632 0.084 ;
    END
  END rec[574]
  PIN rec[575]
    DIRECTION INPUT ;
    USE SIGNAL ;
    PORT
      LAYER M5 ;
        RECT  96.72 0 96.744 0.084 ;
    END
  END rec[575]
  PIN rec[576]
    DIRECTION INPUT ;
    USE SIGNAL ;
    PORT
      LAYER M5 ;
        RECT  96.768 0 96.792 0.084 ;
    END
  END rec[576]
  PIN rec[577]
    DIRECTION INPUT ;
    USE SIGNAL ;
    PORT
      LAYER M5 ;
        RECT  96.816 0 96.84 0.084 ;
    END
  END rec[577]
  PIN rec[578]
    DIRECTION INPUT ;
    USE SIGNAL ;
    PORT
      LAYER M5 ;
        RECT  96.864 0 96.888 0.084 ;
    END
  END rec[578]
  PIN rec[579]
    DIRECTION INPUT ;
    USE SIGNAL ;
    PORT
      LAYER M5 ;
        RECT  96.912 0 96.936 0.084 ;
    END
  END rec[579]
  PIN rec[57]
    DIRECTION INPUT ;
    USE SIGNAL ;
    PORT
      LAYER M5 ;
        RECT  1.968 0 1.992 0.084 ;
    END
  END rec[57]
  PIN rec[580]
    DIRECTION INPUT ;
    USE SIGNAL ;
    PORT
      LAYER M5 ;
        RECT  96.96 0 96.984 0.084 ;
    END
  END rec[580]
  PIN rec[581]
    DIRECTION INPUT ;
    USE SIGNAL ;
    PORT
      LAYER M5 ;
        RECT  97.008 0 97.032 0.084 ;
    END
  END rec[581]
  PIN rec[582]
    DIRECTION INPUT ;
    USE SIGNAL ;
    PORT
      LAYER M5 ;
        RECT  97.056 0 97.08 0.084 ;
    END
  END rec[582]
  PIN rec[583]
    DIRECTION INPUT ;
    USE SIGNAL ;
    PORT
      LAYER M5 ;
        RECT  97.104 0 97.128 0.084 ;
    END
  END rec[583]
  PIN rec[584]
    DIRECTION INPUT ;
    USE SIGNAL ;
    PORT
      LAYER M5 ;
        RECT  97.152 0 97.176 0.084 ;
    END
  END rec[584]
  PIN rec[585]
    DIRECTION INPUT ;
    USE SIGNAL ;
    PORT
      LAYER M5 ;
        RECT  97.2 0 97.224 0.084 ;
    END
  END rec[585]
  PIN rec[586]
    DIRECTION INPUT ;
    USE SIGNAL ;
    PORT
      LAYER M5 ;
        RECT  97.248 0 97.272 0.084 ;
    END
  END rec[586]
  PIN rec[587]
    DIRECTION INPUT ;
    USE SIGNAL ;
    PORT
      LAYER M5 ;
        RECT  97.296 0 97.32 0.084 ;
    END
  END rec[587]
  PIN rec[588]
    DIRECTION INPUT ;
    USE SIGNAL ;
    PORT
      LAYER M5 ;
        RECT  97.344 0 97.368 0.084 ;
    END
  END rec[588]
  PIN rec[589]
    DIRECTION INPUT ;
    USE SIGNAL ;
    PORT
      LAYER M5 ;
        RECT  97.392 0 97.416 0.084 ;
    END
  END rec[589]
  PIN rec[58]
    DIRECTION INPUT ;
    USE SIGNAL ;
    PORT
      LAYER M5 ;
        RECT  2.016 0 2.04 0.084 ;
    END
  END rec[58]
  PIN rec[590]
    DIRECTION INPUT ;
    USE SIGNAL ;
    PORT
      LAYER M5 ;
        RECT  97.44 0 97.464 0.084 ;
    END
  END rec[590]
  PIN rec[591]
    DIRECTION INPUT ;
    USE SIGNAL ;
    PORT
      LAYER M5 ;
        RECT  97.488 0 97.512 0.084 ;
    END
  END rec[591]
  PIN rec[592]
    DIRECTION INPUT ;
    USE SIGNAL ;
    PORT
      LAYER M5 ;
        RECT  97.536 0 97.56 0.084 ;
    END
  END rec[592]
  PIN rec[593]
    DIRECTION INPUT ;
    USE SIGNAL ;
    PORT
      LAYER M5 ;
        RECT  97.584 0 97.608 0.084 ;
    END
  END rec[593]
  PIN rec[594]
    DIRECTION INPUT ;
    USE SIGNAL ;
    PORT
      LAYER M5 ;
        RECT  97.632 0 97.656 0.084 ;
    END
  END rec[594]
  PIN rec[595]
    DIRECTION INPUT ;
    USE SIGNAL ;
    PORT
      LAYER M5 ;
        RECT  97.68 0 97.704 0.084 ;
    END
  END rec[595]
  PIN rec[596]
    DIRECTION INPUT ;
    USE SIGNAL ;
    PORT
      LAYER M5 ;
        RECT  97.728 0 97.752 0.084 ;
    END
  END rec[596]
  PIN rec[597]
    DIRECTION INPUT ;
    USE SIGNAL ;
    PORT
      LAYER M5 ;
        RECT  97.776 0 97.8 0.084 ;
    END
  END rec[597]
  PIN rec[598]
    DIRECTION INPUT ;
    USE SIGNAL ;
    PORT
      LAYER M5 ;
        RECT  97.824 0 97.848 0.084 ;
    END
  END rec[598]
  PIN rec[599]
    DIRECTION INPUT ;
    USE SIGNAL ;
    PORT
      LAYER M5 ;
        RECT  97.872 0 97.896 0.084 ;
    END
  END rec[599]
  PIN rec[59]
    DIRECTION INPUT ;
    USE SIGNAL ;
    PORT
      LAYER M5 ;
        RECT  2.064 0 2.088 0.084 ;
    END
  END rec[59]
  PIN rec[5]
    DIRECTION INPUT ;
    USE SIGNAL ;
    PORT
      LAYER M5 ;
        RECT  49.008 0 49.032 0.084 ;
    END
  END rec[5]
  PIN rec[600]
    DIRECTION INPUT ;
    USE SIGNAL ;
    PORT
      LAYER M5 ;
        RECT  97.92 0 97.944 0.084 ;
    END
  END rec[600]
  PIN rec[601]
    DIRECTION INPUT ;
    USE SIGNAL ;
    PORT
      LAYER M5 ;
        RECT  97.968 0 97.992 0.084 ;
    END
  END rec[601]
  PIN rec[602]
    DIRECTION INPUT ;
    USE SIGNAL ;
    PORT
      LAYER M5 ;
        RECT  98.016 0 98.04 0.084 ;
    END
  END rec[602]
  PIN rec[603]
    DIRECTION INPUT ;
    USE SIGNAL ;
    PORT
      LAYER M5 ;
        RECT  98.064 0 98.088 0.084 ;
    END
  END rec[603]
  PIN rec[604]
    DIRECTION INPUT ;
    USE SIGNAL ;
    PORT
      LAYER M5 ;
        RECT  98.112 0 98.136 0.084 ;
    END
  END rec[604]
  PIN rec[605]
    DIRECTION INPUT ;
    USE SIGNAL ;
    PORT
      LAYER M5 ;
        RECT  98.16 0 98.184 0.084 ;
    END
  END rec[605]
  PIN rec[606]
    DIRECTION INPUT ;
    USE SIGNAL ;
    PORT
      LAYER M5 ;
        RECT  98.208 0 98.232 0.084 ;
    END
  END rec[606]
  PIN rec[607]
    DIRECTION INPUT ;
    USE SIGNAL ;
    PORT
      LAYER M5 ;
        RECT  106.32 0 106.344 0.084 ;
    END
  END rec[607]
  PIN rec[608]
    DIRECTION INPUT ;
    USE SIGNAL ;
    PORT
      LAYER M5 ;
        RECT  106.368 0 106.392 0.084 ;
    END
  END rec[608]
  PIN rec[609]
    DIRECTION INPUT ;
    USE SIGNAL ;
    PORT
      LAYER M5 ;
        RECT  106.416 0 106.44 0.084 ;
    END
  END rec[609]
  PIN rec[60]
    DIRECTION INPUT ;
    USE SIGNAL ;
    PORT
      LAYER M5 ;
        RECT  2.112 0 2.136 0.084 ;
    END
  END rec[60]
  PIN rec[610]
    DIRECTION INPUT ;
    USE SIGNAL ;
    PORT
      LAYER M5 ;
        RECT  106.464 0 106.488 0.084 ;
    END
  END rec[610]
  PIN rec[611]
    DIRECTION INPUT ;
    USE SIGNAL ;
    PORT
      LAYER M5 ;
        RECT  106.512 0 106.536 0.084 ;
    END
  END rec[611]
  PIN rec[612]
    DIRECTION INPUT ;
    USE SIGNAL ;
    PORT
      LAYER M5 ;
        RECT  106.56 0 106.584 0.084 ;
    END
  END rec[612]
  PIN rec[613]
    DIRECTION INPUT ;
    USE SIGNAL ;
    PORT
      LAYER M5 ;
        RECT  106.608 0 106.632 0.084 ;
    END
  END rec[613]
  PIN rec[614]
    DIRECTION INPUT ;
    USE SIGNAL ;
    PORT
      LAYER M5 ;
        RECT  106.656 0 106.68 0.084 ;
    END
  END rec[614]
  PIN rec[615]
    DIRECTION INPUT ;
    USE SIGNAL ;
    PORT
      LAYER M5 ;
        RECT  106.704 0 106.728 0.084 ;
    END
  END rec[615]
  PIN rec[616]
    DIRECTION INPUT ;
    USE SIGNAL ;
    PORT
      LAYER M5 ;
        RECT  106.752 0 106.776 0.084 ;
    END
  END rec[616]
  PIN rec[617]
    DIRECTION INPUT ;
    USE SIGNAL ;
    PORT
      LAYER M5 ;
        RECT  106.8 0 106.824 0.084 ;
    END
  END rec[617]
  PIN rec[618]
    DIRECTION INPUT ;
    USE SIGNAL ;
    PORT
      LAYER M5 ;
        RECT  106.848 0 106.872 0.084 ;
    END
  END rec[618]
  PIN rec[619]
    DIRECTION INPUT ;
    USE SIGNAL ;
    PORT
      LAYER M5 ;
        RECT  106.896 0 106.92 0.084 ;
    END
  END rec[619]
  PIN rec[61]
    DIRECTION INPUT ;
    USE SIGNAL ;
    PORT
      LAYER M5 ;
        RECT  2.16 0 2.184 0.084 ;
    END
  END rec[61]
  PIN rec[620]
    DIRECTION INPUT ;
    USE SIGNAL ;
    PORT
      LAYER M5 ;
        RECT  106.944 0 106.968 0.084 ;
    END
  END rec[620]
  PIN rec[621]
    DIRECTION INPUT ;
    USE SIGNAL ;
    PORT
      LAYER M5 ;
        RECT  106.992 0 107.016 0.084 ;
    END
  END rec[621]
  PIN rec[622]
    DIRECTION INPUT ;
    USE SIGNAL ;
    PORT
      LAYER M5 ;
        RECT  107.04 0 107.064 0.084 ;
    END
  END rec[622]
  PIN rec[623]
    DIRECTION INPUT ;
    USE SIGNAL ;
    PORT
      LAYER M5 ;
        RECT  107.088 0 107.112 0.084 ;
    END
  END rec[623]
  PIN rec[624]
    DIRECTION INPUT ;
    USE SIGNAL ;
    PORT
      LAYER M5 ;
        RECT  107.136 0 107.16 0.084 ;
    END
  END rec[624]
  PIN rec[625]
    DIRECTION INPUT ;
    USE SIGNAL ;
    PORT
      LAYER M5 ;
        RECT  107.184 0 107.208 0.084 ;
    END
  END rec[625]
  PIN rec[626]
    DIRECTION INPUT ;
    USE SIGNAL ;
    PORT
      LAYER M5 ;
        RECT  107.232 0 107.256 0.084 ;
    END
  END rec[626]
  PIN rec[627]
    DIRECTION INPUT ;
    USE SIGNAL ;
    PORT
      LAYER M5 ;
        RECT  107.28 0 107.304 0.084 ;
    END
  END rec[627]
  PIN rec[628]
    DIRECTION INPUT ;
    USE SIGNAL ;
    PORT
      LAYER M5 ;
        RECT  107.328 0 107.352 0.084 ;
    END
  END rec[628]
  PIN rec[629]
    DIRECTION INPUT ;
    USE SIGNAL ;
    PORT
      LAYER M5 ;
        RECT  107.376 0 107.4 0.084 ;
    END
  END rec[629]
  PIN rec[62]
    DIRECTION INPUT ;
    USE SIGNAL ;
    PORT
      LAYER M5 ;
        RECT  2.208 0 2.232 0.084 ;
    END
  END rec[62]
  PIN rec[630]
    DIRECTION INPUT ;
    USE SIGNAL ;
    PORT
      LAYER M5 ;
        RECT  107.424 0 107.448 0.084 ;
    END
  END rec[630]
  PIN rec[631]
    DIRECTION INPUT ;
    USE SIGNAL ;
    PORT
      LAYER M5 ;
        RECT  107.472 0 107.496 0.084 ;
    END
  END rec[631]
  PIN rec[632]
    DIRECTION INPUT ;
    USE SIGNAL ;
    PORT
      LAYER M5 ;
        RECT  107.52 0 107.544 0.084 ;
    END
  END rec[632]
  PIN rec[633]
    DIRECTION INPUT ;
    USE SIGNAL ;
    PORT
      LAYER M5 ;
        RECT  107.568 0 107.592 0.084 ;
    END
  END rec[633]
  PIN rec[634]
    DIRECTION INPUT ;
    USE SIGNAL ;
    PORT
      LAYER M5 ;
        RECT  107.616 0 107.64 0.084 ;
    END
  END rec[634]
  PIN rec[635]
    DIRECTION INPUT ;
    USE SIGNAL ;
    PORT
      LAYER M5 ;
        RECT  107.664 0 107.688 0.084 ;
    END
  END rec[635]
  PIN rec[636]
    DIRECTION INPUT ;
    USE SIGNAL ;
    PORT
      LAYER M5 ;
        RECT  107.712 0 107.736 0.084 ;
    END
  END rec[636]
  PIN rec[637]
    DIRECTION INPUT ;
    USE SIGNAL ;
    PORT
      LAYER M5 ;
        RECT  107.76 0 107.784 0.084 ;
    END
  END rec[637]
  PIN rec[638]
    DIRECTION INPUT ;
    USE SIGNAL ;
    PORT
      LAYER M5 ;
        RECT  107.808 0 107.832 0.084 ;
    END
  END rec[638]
  PIN rec[639]
    DIRECTION INPUT ;
    USE SIGNAL ;
    PORT
      LAYER M5 ;
        RECT  45.264 0 45.288 0.084 ;
    END
  END rec[639]
  PIN rec[63]
    DIRECTION INPUT ;
    USE SIGNAL ;
    PORT
      LAYER M5 ;
        RECT  42.192 0 42.216 0.084 ;
    END
  END rec[63]
  PIN rec[640]
    DIRECTION INPUT ;
    USE SIGNAL ;
    PORT
      LAYER M5 ;
        RECT  45.312 0 45.336 0.084 ;
    END
  END rec[640]
  PIN rec[641]
    DIRECTION INPUT ;
    USE SIGNAL ;
    PORT
      LAYER M5 ;
        RECT  45.36 0 45.384 0.084 ;
    END
  END rec[641]
  PIN rec[642]
    DIRECTION INPUT ;
    USE SIGNAL ;
    PORT
      LAYER M5 ;
        RECT  45.408 0 45.432 0.084 ;
    END
  END rec[642]
  PIN rec[643]
    DIRECTION INPUT ;
    USE SIGNAL ;
    PORT
      LAYER M5 ;
        RECT  45.456 0 45.48 0.084 ;
    END
  END rec[643]
  PIN rec[644]
    DIRECTION INPUT ;
    USE SIGNAL ;
    PORT
      LAYER M5 ;
        RECT  45.504 0 45.528 0.084 ;
    END
  END rec[644]
  PIN rec[645]
    DIRECTION INPUT ;
    USE SIGNAL ;
    PORT
      LAYER M5 ;
        RECT  45.552 0 45.576 0.084 ;
    END
  END rec[645]
  PIN rec[646]
    DIRECTION INPUT ;
    USE SIGNAL ;
    PORT
      LAYER M5 ;
        RECT  45.6 0 45.624 0.084 ;
    END
  END rec[646]
  PIN rec[647]
    DIRECTION INPUT ;
    USE SIGNAL ;
    PORT
      LAYER M5 ;
        RECT  45.648 0 45.672 0.084 ;
    END
  END rec[647]
  PIN rec[648]
    DIRECTION INPUT ;
    USE SIGNAL ;
    PORT
      LAYER M5 ;
        RECT  45.696 0 45.72 0.084 ;
    END
  END rec[648]
  PIN rec[649]
    DIRECTION INPUT ;
    USE SIGNAL ;
    PORT
      LAYER M5 ;
        RECT  45.744 0 45.768 0.084 ;
    END
  END rec[649]
  PIN rec[64]
    DIRECTION INPUT ;
    USE SIGNAL ;
    PORT
      LAYER M5 ;
        RECT  42.24 0 42.264 0.084 ;
    END
  END rec[64]
  PIN rec[650]
    DIRECTION INPUT ;
    USE SIGNAL ;
    PORT
      LAYER M5 ;
        RECT  45.792 0 45.816 0.084 ;
    END
  END rec[650]
  PIN rec[651]
    DIRECTION INPUT ;
    USE SIGNAL ;
    PORT
      LAYER M5 ;
        RECT  45.84 0 45.864 0.084 ;
    END
  END rec[651]
  PIN rec[652]
    DIRECTION INPUT ;
    USE SIGNAL ;
    PORT
      LAYER M5 ;
        RECT  45.888 0 45.912 0.084 ;
    END
  END rec[652]
  PIN rec[653]
    DIRECTION INPUT ;
    USE SIGNAL ;
    PORT
      LAYER M5 ;
        RECT  45.936 0 45.96 0.084 ;
    END
  END rec[653]
  PIN rec[654]
    DIRECTION INPUT ;
    USE SIGNAL ;
    PORT
      LAYER M5 ;
        RECT  45.984 0 46.008 0.084 ;
    END
  END rec[654]
  PIN rec[655]
    DIRECTION INPUT ;
    USE SIGNAL ;
    PORT
      LAYER M5 ;
        RECT  46.032 0 46.056 0.084 ;
    END
  END rec[655]
  PIN rec[656]
    DIRECTION INPUT ;
    USE SIGNAL ;
    PORT
      LAYER M5 ;
        RECT  46.08 0 46.104 0.084 ;
    END
  END rec[656]
  PIN rec[657]
    DIRECTION INPUT ;
    USE SIGNAL ;
    PORT
      LAYER M5 ;
        RECT  46.128 0 46.152 0.084 ;
    END
  END rec[657]
  PIN rec[658]
    DIRECTION INPUT ;
    USE SIGNAL ;
    PORT
      LAYER M5 ;
        RECT  46.176 0 46.2 0.084 ;
    END
  END rec[658]
  PIN rec[659]
    DIRECTION INPUT ;
    USE SIGNAL ;
    PORT
      LAYER M5 ;
        RECT  46.224 0 46.248 0.084 ;
    END
  END rec[659]
  PIN rec[65]
    DIRECTION INPUT ;
    USE SIGNAL ;
    PORT
      LAYER M5 ;
        RECT  42.288 0 42.312 0.084 ;
    END
  END rec[65]
  PIN rec[660]
    DIRECTION INPUT ;
    USE SIGNAL ;
    PORT
      LAYER M5 ;
        RECT  46.272 0 46.296 0.084 ;
    END
  END rec[660]
  PIN rec[661]
    DIRECTION INPUT ;
    USE SIGNAL ;
    PORT
      LAYER M5 ;
        RECT  46.32 0 46.344 0.084 ;
    END
  END rec[661]
  PIN rec[662]
    DIRECTION INPUT ;
    USE SIGNAL ;
    PORT
      LAYER M5 ;
        RECT  46.368 0 46.392 0.084 ;
    END
  END rec[662]
  PIN rec[663]
    DIRECTION INPUT ;
    USE SIGNAL ;
    PORT
      LAYER M5 ;
        RECT  46.416 0 46.44 0.084 ;
    END
  END rec[663]
  PIN rec[664]
    DIRECTION INPUT ;
    USE SIGNAL ;
    PORT
      LAYER M5 ;
        RECT  46.464 0 46.488 0.084 ;
    END
  END rec[664]
  PIN rec[665]
    DIRECTION INPUT ;
    USE SIGNAL ;
    PORT
      LAYER M5 ;
        RECT  46.512 0 46.536 0.084 ;
    END
  END rec[665]
  PIN rec[666]
    DIRECTION INPUT ;
    USE SIGNAL ;
    PORT
      LAYER M5 ;
        RECT  46.56 0 46.584 0.084 ;
    END
  END rec[666]
  PIN rec[667]
    DIRECTION INPUT ;
    USE SIGNAL ;
    PORT
      LAYER M5 ;
        RECT  46.608 0 46.632 0.084 ;
    END
  END rec[667]
  PIN rec[668]
    DIRECTION INPUT ;
    USE SIGNAL ;
    PORT
      LAYER M5 ;
        RECT  46.656 0 46.68 0.084 ;
    END
  END rec[668]
  PIN rec[669]
    DIRECTION INPUT ;
    USE SIGNAL ;
    PORT
      LAYER M5 ;
        RECT  46.704 0 46.728 0.084 ;
    END
  END rec[669]
  PIN rec[66]
    DIRECTION INPUT ;
    USE SIGNAL ;
    PORT
      LAYER M5 ;
        RECT  42.336 0 42.36 0.084 ;
    END
  END rec[66]
  PIN rec[670]
    DIRECTION INPUT ;
    USE SIGNAL ;
    PORT
      LAYER M5 ;
        RECT  46.752 0 46.776 0.084 ;
    END
  END rec[670]
  PIN rec[671]
    DIRECTION INPUT ;
    USE SIGNAL ;
    PORT
      LAYER M5 ;
        RECT  58.32 0 58.344 0.084 ;
    END
  END rec[671]
  PIN rec[672]
    DIRECTION INPUT ;
    USE SIGNAL ;
    PORT
      LAYER M5 ;
        RECT  58.368 0 58.392 0.084 ;
    END
  END rec[672]
  PIN rec[673]
    DIRECTION INPUT ;
    USE SIGNAL ;
    PORT
      LAYER M5 ;
        RECT  58.416 0 58.44 0.084 ;
    END
  END rec[673]
  PIN rec[674]
    DIRECTION INPUT ;
    USE SIGNAL ;
    PORT
      LAYER M5 ;
        RECT  58.464 0 58.488 0.084 ;
    END
  END rec[674]
  PIN rec[675]
    DIRECTION INPUT ;
    USE SIGNAL ;
    PORT
      LAYER M5 ;
        RECT  58.512 0 58.536 0.084 ;
    END
  END rec[675]
  PIN rec[676]
    DIRECTION INPUT ;
    USE SIGNAL ;
    PORT
      LAYER M5 ;
        RECT  58.56 0 58.584 0.084 ;
    END
  END rec[676]
  PIN rec[677]
    DIRECTION INPUT ;
    USE SIGNAL ;
    PORT
      LAYER M5 ;
        RECT  58.608 0 58.632 0.084 ;
    END
  END rec[677]
  PIN rec[678]
    DIRECTION INPUT ;
    USE SIGNAL ;
    PORT
      LAYER M5 ;
        RECT  58.656 0 58.68 0.084 ;
    END
  END rec[678]
  PIN rec[679]
    DIRECTION INPUT ;
    USE SIGNAL ;
    PORT
      LAYER M5 ;
        RECT  58.704 0 58.728 0.084 ;
    END
  END rec[679]
  PIN rec[67]
    DIRECTION INPUT ;
    USE SIGNAL ;
    PORT
      LAYER M5 ;
        RECT  42.384 0 42.408 0.084 ;
    END
  END rec[67]
  PIN rec[680]
    DIRECTION INPUT ;
    USE SIGNAL ;
    PORT
      LAYER M5 ;
        RECT  58.752 0 58.776 0.084 ;
    END
  END rec[680]
  PIN rec[681]
    DIRECTION INPUT ;
    USE SIGNAL ;
    PORT
      LAYER M5 ;
        RECT  58.8 0 58.824 0.084 ;
    END
  END rec[681]
  PIN rec[682]
    DIRECTION INPUT ;
    USE SIGNAL ;
    PORT
      LAYER M5 ;
        RECT  58.848 0 58.872 0.084 ;
    END
  END rec[682]
  PIN rec[68]
    DIRECTION INPUT ;
    USE SIGNAL ;
    PORT
      LAYER M5 ;
        RECT  42.432 0 42.456 0.084 ;
    END
  END rec[68]
  PIN rec[69]
    DIRECTION INPUT ;
    USE SIGNAL ;
    PORT
      LAYER M5 ;
        RECT  42.48 0 42.504 0.084 ;
    END
  END rec[69]
  PIN rec[6]
    DIRECTION INPUT ;
    USE SIGNAL ;
    PORT
      LAYER M5 ;
        RECT  49.056 0 49.08 0.084 ;
    END
  END rec[6]
  PIN rec[70]
    DIRECTION INPUT ;
    USE SIGNAL ;
    PORT
      LAYER M5 ;
        RECT  42.528 0 42.552 0.084 ;
    END
  END rec[70]
  PIN rec[71]
    DIRECTION INPUT ;
    USE SIGNAL ;
    PORT
      LAYER M5 ;
        RECT  42.576 0 42.6 0.084 ;
    END
  END rec[71]
  PIN rec[72]
    DIRECTION INPUT ;
    USE SIGNAL ;
    PORT
      LAYER M5 ;
        RECT  42.624 0 42.648 0.084 ;
    END
  END rec[72]
  PIN rec[73]
    DIRECTION INPUT ;
    USE SIGNAL ;
    PORT
      LAYER M5 ;
        RECT  42.672 0 42.696 0.084 ;
    END
  END rec[73]
  PIN rec[74]
    DIRECTION INPUT ;
    USE SIGNAL ;
    PORT
      LAYER M5 ;
        RECT  42.72 0 42.744 0.084 ;
    END
  END rec[74]
  PIN rec[75]
    DIRECTION INPUT ;
    USE SIGNAL ;
    PORT
      LAYER M5 ;
        RECT  42.768 0 42.792 0.084 ;
    END
  END rec[75]
  PIN rec[76]
    DIRECTION INPUT ;
    USE SIGNAL ;
    PORT
      LAYER M5 ;
        RECT  42.816 0 42.84 0.084 ;
    END
  END rec[76]
  PIN rec[77]
    DIRECTION INPUT ;
    USE SIGNAL ;
    PORT
      LAYER M5 ;
        RECT  42.864 0 42.888 0.084 ;
    END
  END rec[77]
  PIN rec[78]
    DIRECTION INPUT ;
    USE SIGNAL ;
    PORT
      LAYER M5 ;
        RECT  42.912 0 42.936 0.084 ;
    END
  END rec[78]
  PIN rec[79]
    DIRECTION INPUT ;
    USE SIGNAL ;
    PORT
      LAYER M5 ;
        RECT  42.96 0 42.984 0.084 ;
    END
  END rec[79]
  PIN rec[7]
    DIRECTION INPUT ;
    USE SIGNAL ;
    PORT
      LAYER M5 ;
        RECT  49.104 0 49.128 0.084 ;
    END
  END rec[7]
  PIN rec[80]
    DIRECTION INPUT ;
    USE SIGNAL ;
    PORT
      LAYER M5 ;
        RECT  43.008 0 43.032 0.084 ;
    END
  END rec[80]
  PIN rec[81]
    DIRECTION INPUT ;
    USE SIGNAL ;
    PORT
      LAYER M5 ;
        RECT  43.056 0 43.08 0.084 ;
    END
  END rec[81]
  PIN rec[82]
    DIRECTION INPUT ;
    USE SIGNAL ;
    PORT
      LAYER M5 ;
        RECT  43.104 0 43.128 0.084 ;
    END
  END rec[82]
  PIN rec[83]
    DIRECTION INPUT ;
    USE SIGNAL ;
    PORT
      LAYER M5 ;
        RECT  43.152 0 43.176 0.084 ;
    END
  END rec[83]
  PIN rec[84]
    DIRECTION INPUT ;
    USE SIGNAL ;
    PORT
      LAYER M5 ;
        RECT  43.2 0 43.224 0.084 ;
    END
  END rec[84]
  PIN rec[85]
    DIRECTION INPUT ;
    USE SIGNAL ;
    PORT
      LAYER M5 ;
        RECT  43.248 0 43.272 0.084 ;
    END
  END rec[85]
  PIN rec[86]
    DIRECTION INPUT ;
    USE SIGNAL ;
    PORT
      LAYER M5 ;
        RECT  43.296 0 43.32 0.084 ;
    END
  END rec[86]
  PIN rec[87]
    DIRECTION INPUT ;
    USE SIGNAL ;
    PORT
      LAYER M5 ;
        RECT  43.344 0 43.368 0.084 ;
    END
  END rec[87]
  PIN rec[88]
    DIRECTION INPUT ;
    USE SIGNAL ;
    PORT
      LAYER M5 ;
        RECT  43.392 0 43.416 0.084 ;
    END
  END rec[88]
  PIN rec[89]
    DIRECTION INPUT ;
    USE SIGNAL ;
    PORT
      LAYER M5 ;
        RECT  43.44 0 43.464 0.084 ;
    END
  END rec[89]
  PIN rec[8]
    DIRECTION INPUT ;
    USE SIGNAL ;
    PORT
      LAYER M5 ;
        RECT  49.152 0 49.176 0.084 ;
    END
  END rec[8]
  PIN rec[90]
    DIRECTION INPUT ;
    USE SIGNAL ;
    PORT
      LAYER M5 ;
        RECT  43.488 0 43.512 0.084 ;
    END
  END rec[90]
  PIN rec[91]
    DIRECTION INPUT ;
    USE SIGNAL ;
    PORT
      LAYER M5 ;
        RECT  43.536 0 43.56 0.084 ;
    END
  END rec[91]
  PIN rec[92]
    DIRECTION INPUT ;
    USE SIGNAL ;
    PORT
      LAYER M5 ;
        RECT  43.584 0 43.608 0.084 ;
    END
  END rec[92]
  PIN rec[93]
    DIRECTION INPUT ;
    USE SIGNAL ;
    PORT
      LAYER M5 ;
        RECT  43.632 0 43.656 0.084 ;
    END
  END rec[93]
  PIN rec[94]
    DIRECTION INPUT ;
    USE SIGNAL ;
    PORT
      LAYER M5 ;
        RECT  43.68 0 43.704 0.084 ;
    END
  END rec[94]
  PIN rec[95]
    DIRECTION INPUT ;
    USE SIGNAL ;
    PORT
      LAYER M5 ;
        RECT  59.856 0 59.88 0.084 ;
    END
  END rec[95]
  PIN rec[96]
    DIRECTION INPUT ;
    USE SIGNAL ;
    PORT
      LAYER M5 ;
        RECT  59.904 0 59.928 0.084 ;
    END
  END rec[96]
  PIN rec[97]
    DIRECTION INPUT ;
    USE SIGNAL ;
    PORT
      LAYER M5 ;
        RECT  59.952 0 59.976 0.084 ;
    END
  END rec[97]
  PIN rec[98]
    DIRECTION INPUT ;
    USE SIGNAL ;
    PORT
      LAYER M5 ;
        RECT  60 0 60.024 0.084 ;
    END
  END rec[98]
  PIN rec[99]
    DIRECTION INPUT ;
    USE SIGNAL ;
    PORT
      LAYER M5 ;
        RECT  60.048 0 60.072 0.084 ;
    END
  END rec[99]
  PIN rec[9]
    DIRECTION INPUT ;
    USE SIGNAL ;
    PORT
      LAYER M5 ;
        RECT  49.2 0 49.224 0.084 ;
    END
  END rec[9]
  PIN rst_n
    DIRECTION INPUT ;
    USE SIGNAL ;
    PORT
      LAYER M5 ;
        RECT  58.896 0 58.92 0.084 ;
    END
  END rst_n
  PIN s1_v
    DIRECTION OUTPUT ;
    USE SIGNAL ;
    PORT
      LAYER M5 ;
        RECT  51.744 71.196 51.768 71.28 ;
    END
    PORT
      LAYER M5 ;
        RECT  51.744 70.069 51.768 71.248 ;
    END
  END s1_v
  PIN VDD
    DIRECTION INOUT ;
    USE POWER ;
    PORT
      LAYER M5 ;
        RECT  126.792 2.151 126.912 69.129 ;
        RECT  121.392 2.151 121.512 69.129 ;
        RECT  115.992 2.151 116.112 69.129 ;
        RECT  110.592 2.151 110.712 69.129 ;
        RECT  105.192 2.151 105.312 69.129 ;
        RECT  99.792 2.151 99.912 69.129 ;
        RECT  94.392 2.151 94.512 69.129 ;
        RECT  88.992 2.151 89.112 69.129 ;
        RECT  83.592 2.151 83.712 69.129 ;
        RECT  78.192 2.151 78.312 69.129 ;
        RECT  72.792 2.151 72.912 69.129 ;
        RECT  67.392 2.151 67.512 69.129 ;
        RECT  61.992 2.151 62.112 69.129 ;
        RECT  56.592 2.151 56.712 69.129 ;
        RECT  51.192 2.151 51.312 69.129 ;
        RECT  45.792 2.151 45.912 69.129 ;
        RECT  40.392 2.151 40.512 69.129 ;
        RECT  34.992 2.151 35.112 69.129 ;
        RECT  29.592 2.151 29.712 69.129 ;
        RECT  24.192 2.151 24.312 69.129 ;
        RECT  18.792 2.151 18.912 69.129 ;
        RECT  13.392 2.151 13.512 69.129 ;
        RECT  7.992 2.151 8.112 69.129 ;
        RECT  2.592 2.151 2.712 69.129 ;
    END
  END VDD
  PIN VSS
    DIRECTION INOUT ;
    USE GROUND ;
    PORT
      LAYER M5 ;
        RECT  126.6 2.137 126.72 69.143 ;
        RECT  121.2 2.137 121.32 69.143 ;
        RECT  115.8 2.137 115.92 69.143 ;
        RECT  110.4 2.137 110.52 69.143 ;
        RECT  105 2.137 105.12 69.143 ;
        RECT  99.6 2.137 99.72 69.143 ;
        RECT  94.2 2.137 94.32 69.143 ;
        RECT  88.8 2.137 88.92 69.143 ;
        RECT  83.4 2.137 83.52 69.143 ;
        RECT  78 2.137 78.12 69.143 ;
        RECT  72.6 2.137 72.72 69.143 ;
        RECT  67.2 2.137 67.32 69.143 ;
        RECT  61.8 2.137 61.92 69.143 ;
        RECT  56.4 2.137 56.52 69.143 ;
        RECT  51 2.137 51.12 69.143 ;
        RECT  45.6 2.137 45.72 69.143 ;
        RECT  40.2 2.137 40.32 69.143 ;
        RECT  34.8 2.137 34.92 69.143 ;
        RECT  29.4 2.137 29.52 69.143 ;
        RECT  24 2.137 24.12 69.143 ;
        RECT  18.6 2.137 18.72 69.143 ;
        RECT  13.2 2.137 13.32 69.143 ;
        RECT  7.8 2.137 7.92 69.143 ;
        RECT  2.4 2.137 2.52 69.143 ;
    END
  END VSS
  # OT_OBS_CLOSED layer=M5 d_um=1.536 added=79
  OBS
    LAYER RVTN ;
     RECT  2.16 2.16 127.44 2.295 ;
     RECT  2.16 2.565 127.44 2.835 ;
     RECT  2.16 3.105 127.44 3.375 ;
     RECT  2.16 3.645 127.44 3.915 ;
     RECT  2.16 4.185 127.44 4.455 ;
     RECT  2.16 4.725 127.44 4.995 ;
     RECT  2.16 5.265 127.44 5.535 ;
     RECT  2.16 5.805 127.44 6.075 ;
     RECT  2.16 6.345 127.44 6.615 ;
     RECT  2.16 6.885 127.44 7.155 ;
     RECT  2.16 7.425 127.44 7.695 ;
     RECT  2.16 7.965 127.44 8.235 ;
     RECT  2.16 8.505 127.44 8.775 ;
     RECT  2.16 9.045 127.44 9.315 ;
     RECT  2.16 9.585 127.44 9.855 ;
     RECT  2.16 10.125 127.44 10.395 ;
     RECT  2.16 10.665 127.44 10.935 ;
     RECT  2.16 11.205 127.44 11.475 ;
     RECT  2.16 11.745 127.44 12.015 ;
     RECT  2.16 12.285 127.44 12.555 ;
     RECT  2.16 12.825 127.44 13.095 ;
     RECT  2.16 13.365 127.44 13.635 ;
     RECT  2.16 13.905 127.44 14.175 ;
     RECT  2.16 14.445 127.44 14.715 ;
     RECT  2.16 14.985 127.44 15.255 ;
     RECT  2.16 15.525 127.44 15.795 ;
     RECT  2.16 16.065 127.44 16.335 ;
     RECT  2.16 16.605 127.44 16.875 ;
     RECT  2.16 17.145 127.44 17.415 ;
     RECT  2.16 17.685 127.44 17.955 ;
     RECT  2.16 18.225 127.44 18.495 ;
     RECT  2.16 18.765 127.44 19.035 ;
     RECT  2.16 19.305 127.44 19.575 ;
     RECT  2.16 19.845 127.44 20.115 ;
     RECT  2.16 20.385 127.44 20.655 ;
     RECT  2.16 20.925 127.44 21.195 ;
     RECT  2.16 21.465 127.44 21.735 ;
     RECT  2.16 22.005 127.44 22.275 ;
     RECT  2.16 22.545 127.44 22.815 ;
     RECT  2.16 23.085 127.44 23.355 ;
     RECT  2.16 23.625 127.44 23.895 ;
     RECT  2.16 24.165 127.44 24.435 ;
     RECT  2.16 24.705 127.44 24.975 ;
     RECT  2.16 25.245 127.44 25.515 ;
     RECT  2.16 25.785 127.44 26.055 ;
     RECT  2.16 26.325 127.44 26.595 ;
     RECT  2.16 26.865 127.44 27.135 ;
     RECT  2.16 27.405 127.44 27.675 ;
     RECT  2.16 27.945 127.44 28.215 ;
     RECT  2.16 28.485 127.44 28.755 ;
     RECT  2.16 29.025 127.44 29.295 ;
     RECT  2.16 29.565 127.44 29.835 ;
     RECT  2.16 30.105 127.44 30.375 ;
     RECT  2.16 30.645 127.44 30.915 ;
     RECT  2.16 31.185 127.44 31.455 ;
     RECT  2.16 31.725 127.44 31.995 ;
     RECT  2.16 32.265 127.44 32.535 ;
     RECT  2.16 32.805 127.44 33.075 ;
     RECT  2.16 33.345 127.44 33.615 ;
     RECT  2.16 33.885 127.44 34.155 ;
     RECT  2.16 34.425 127.44 34.695 ;
     RECT  2.16 34.965 127.44 35.235 ;
     RECT  2.16 35.505 127.44 35.775 ;
     RECT  2.16 36.045 127.44 36.315 ;
     RECT  2.16 36.585 127.44 36.855 ;
     RECT  2.16 37.125 127.44 37.395 ;
     RECT  2.16 37.665 127.44 37.935 ;
     RECT  2.16 38.205 127.44 38.475 ;
     RECT  2.16 38.745 127.44 39.015 ;
     RECT  2.16 39.285 127.44 39.555 ;
     RECT  2.16 39.825 127.44 40.095 ;
     RECT  2.16 40.365 127.44 40.635 ;
     RECT  2.16 40.905 127.44 41.175 ;
     RECT  2.16 41.445 127.44 41.715 ;
     RECT  2.16 41.985 127.44 42.255 ;
     RECT  2.16 42.525 127.44 42.795 ;
     RECT  2.16 43.065 127.44 43.335 ;
     RECT  2.16 43.605 127.44 43.875 ;
     RECT  2.16 44.145 127.44 44.415 ;
     RECT  2.16 44.685 127.44 44.955 ;
     RECT  2.16 45.225 127.44 45.495 ;
     RECT  2.16 45.765 127.44 46.035 ;
     RECT  2.16 46.305 127.44 46.575 ;
     RECT  2.16 46.845 127.44 47.115 ;
     RECT  2.16 47.385 127.44 47.655 ;
     RECT  2.16 47.925 127.44 48.195 ;
     RECT  2.16 48.465 127.44 48.735 ;
     RECT  2.16 49.005 127.44 49.275 ;
     RECT  2.16 49.545 127.44 49.815 ;
     RECT  2.16 50.085 127.44 50.355 ;
     RECT  2.16 50.625 127.44 50.895 ;
     RECT  2.16 51.165 127.44 51.435 ;
     RECT  2.16 51.705 127.44 51.975 ;
     RECT  2.16 52.245 127.44 52.515 ;
     RECT  2.16 52.785 127.44 53.055 ;
     RECT  2.16 53.325 127.44 53.595 ;
     RECT  2.16 53.865 127.44 54.135 ;
     RECT  2.16 54.405 127.44 54.675 ;
     RECT  2.16 54.945 127.44 55.215 ;
     RECT  2.16 55.485 127.44 55.755 ;
     RECT  2.16 56.025 127.44 56.295 ;
     RECT  2.16 56.565 127.44 56.835 ;
     RECT  2.16 57.105 127.44 57.375 ;
     RECT  2.16 57.645 127.44 57.915 ;
     RECT  2.16 58.185 127.44 58.455 ;
     RECT  2.16 58.725 127.44 58.995 ;
     RECT  2.16 59.265 127.44 59.535 ;
     RECT  2.16 59.805 127.44 60.075 ;
     RECT  2.16 60.345 127.44 60.615 ;
     RECT  2.16 60.885 127.44 61.155 ;
     RECT  2.16 61.425 127.44 61.695 ;
     RECT  2.16 61.965 127.44 62.235 ;
     RECT  2.16 62.505 127.44 62.775 ;
     RECT  2.16 63.045 127.44 63.315 ;
     RECT  2.16 63.585 127.44 63.855 ;
     RECT  2.16 64.125 127.44 64.395 ;
     RECT  2.16 64.665 127.44 64.935 ;
     RECT  2.16 65.205 127.44 65.475 ;
     RECT  2.16 65.745 127.44 66.015 ;
     RECT  2.16 66.285 127.44 66.555 ;
     RECT  2.16 66.825 127.44 67.095 ;
     RECT  2.16 67.365 127.44 67.635 ;
     RECT  2.16 67.905 127.44 68.175 ;
     RECT  2.16 68.445 127.44 68.715 ;
     RECT  2.16 68.985 127.44 69.12 ;
    LAYER RVTP ;
     RECT  2.16 2.295 127.44 2.565 ;
     RECT  2.16 2.835 127.44 3.105 ;
     RECT  2.16 3.375 127.44 3.645 ;
     RECT  2.16 3.915 127.44 4.185 ;
     RECT  2.16 4.455 127.44 4.725 ;
     RECT  2.16 4.995 127.44 5.265 ;
     RECT  2.16 5.535 127.44 5.805 ;
     RECT  2.16 6.075 127.44 6.345 ;
     RECT  2.16 6.615 127.44 6.885 ;
     RECT  2.16 7.155 127.44 7.425 ;
     RECT  2.16 7.695 127.44 7.965 ;
     RECT  2.16 8.235 127.44 8.505 ;
     RECT  2.16 8.775 127.44 9.045 ;
     RECT  2.16 9.315 127.44 9.585 ;
     RECT  2.16 9.855 127.44 10.125 ;
     RECT  2.16 10.395 127.44 10.665 ;
     RECT  2.16 10.935 127.44 11.205 ;
     RECT  2.16 11.475 127.44 11.745 ;
     RECT  2.16 12.015 127.44 12.285 ;
     RECT  2.16 12.555 127.44 12.825 ;
     RECT  2.16 13.095 127.44 13.365 ;
     RECT  2.16 13.635 127.44 13.905 ;
     RECT  2.16 14.175 127.44 14.445 ;
     RECT  2.16 14.715 127.44 14.985 ;
     RECT  2.16 15.255 127.44 15.525 ;
     RECT  2.16 15.795 127.44 16.065 ;
     RECT  2.16 16.335 127.44 16.605 ;
     RECT  2.16 16.875 127.44 17.145 ;
     RECT  2.16 17.415 127.44 17.685 ;
     RECT  2.16 17.955 127.44 18.225 ;
     RECT  2.16 18.495 127.44 18.765 ;
     RECT  2.16 19.035 127.44 19.305 ;
     RECT  2.16 19.575 127.44 19.845 ;
     RECT  2.16 20.115 127.44 20.385 ;
     RECT  2.16 20.655 127.44 20.925 ;
     RECT  2.16 21.195 127.44 21.465 ;
     RECT  2.16 21.735 127.44 22.005 ;
     RECT  2.16 22.275 127.44 22.545 ;
     RECT  2.16 22.815 127.44 23.085 ;
     RECT  2.16 23.355 127.44 23.625 ;
     RECT  2.16 23.895 127.44 24.165 ;
     RECT  2.16 24.435 127.44 24.705 ;
     RECT  2.16 24.975 127.44 25.245 ;
     RECT  2.16 25.515 127.44 25.785 ;
     RECT  2.16 26.055 127.44 26.325 ;
     RECT  2.16 26.595 127.44 26.865 ;
     RECT  2.16 27.135 127.44 27.405 ;
     RECT  2.16 27.675 127.44 27.945 ;
     RECT  2.16 28.215 127.44 28.485 ;
     RECT  2.16 28.755 127.44 29.025 ;
     RECT  2.16 29.295 127.44 29.565 ;
     RECT  2.16 29.835 127.44 30.105 ;
     RECT  2.16 30.375 127.44 30.645 ;
     RECT  2.16 30.915 127.44 31.185 ;
     RECT  2.16 31.455 127.44 31.725 ;
     RECT  2.16 31.995 127.44 32.265 ;
     RECT  2.16 32.535 127.44 32.805 ;
     RECT  2.16 33.075 127.44 33.345 ;
     RECT  2.16 33.615 127.44 33.885 ;
     RECT  2.16 34.155 127.44 34.425 ;
     RECT  2.16 34.695 127.44 34.965 ;
     RECT  2.16 35.235 127.44 35.505 ;
     RECT  2.16 35.775 127.44 36.045 ;
     RECT  2.16 36.315 127.44 36.585 ;
     RECT  2.16 36.855 127.44 37.125 ;
     RECT  2.16 37.395 127.44 37.665 ;
     RECT  2.16 37.935 127.44 38.205 ;
     RECT  2.16 38.475 127.44 38.745 ;
     RECT  2.16 39.015 127.44 39.285 ;
     RECT  2.16 39.555 127.44 39.825 ;
     RECT  2.16 40.095 127.44 40.365 ;
     RECT  2.16 40.635 127.44 40.905 ;
     RECT  2.16 41.175 127.44 41.445 ;
     RECT  2.16 41.715 127.44 41.985 ;
     RECT  2.16 42.255 127.44 42.525 ;
     RECT  2.16 42.795 127.44 43.065 ;
     RECT  2.16 43.335 127.44 43.605 ;
     RECT  2.16 43.875 127.44 44.145 ;
     RECT  2.16 44.415 127.44 44.685 ;
     RECT  2.16 44.955 127.44 45.225 ;
     RECT  2.16 45.495 127.44 45.765 ;
     RECT  2.16 46.035 127.44 46.305 ;
     RECT  2.16 46.575 127.44 46.845 ;
     RECT  2.16 47.115 127.44 47.385 ;
     RECT  2.16 47.655 127.44 47.925 ;
     RECT  2.16 48.195 127.44 48.465 ;
     RECT  2.16 48.735 127.44 49.005 ;
     RECT  2.16 49.275 127.44 49.545 ;
     RECT  2.16 49.815 127.44 50.085 ;
     RECT  2.16 50.355 127.44 50.625 ;
     RECT  2.16 50.895 127.44 51.165 ;
     RECT  2.16 51.435 127.44 51.705 ;
     RECT  2.16 51.975 127.44 52.245 ;
     RECT  2.16 52.515 127.44 52.785 ;
     RECT  2.16 53.055 127.44 53.325 ;
     RECT  2.16 53.595 127.44 53.865 ;
     RECT  2.16 54.135 127.44 54.405 ;
     RECT  2.16 54.675 127.44 54.945 ;
     RECT  2.16 55.215 127.44 55.485 ;
     RECT  2.16 55.755 127.44 56.025 ;
     RECT  2.16 56.295 127.44 56.565 ;
     RECT  2.16 56.835 127.44 57.105 ;
     RECT  2.16 57.375 127.44 57.645 ;
     RECT  2.16 57.915 127.44 58.185 ;
     RECT  2.16 58.455 127.44 58.725 ;
     RECT  2.16 58.995 127.44 59.265 ;
     RECT  2.16 59.535 127.44 59.805 ;
     RECT  2.16 60.075 127.44 60.345 ;
     RECT  2.16 60.615 127.44 60.885 ;
     RECT  2.16 61.155 127.44 61.425 ;
     RECT  2.16 61.695 127.44 61.965 ;
     RECT  2.16 62.235 127.44 62.505 ;
     RECT  2.16 62.775 127.44 63.045 ;
     RECT  2.16 63.315 127.44 63.585 ;
     RECT  2.16 63.855 127.44 64.125 ;
     RECT  2.16 64.395 127.44 64.665 ;
     RECT  2.16 64.935 127.44 65.205 ;
     RECT  2.16 65.475 127.44 65.745 ;
     RECT  2.16 66.015 127.44 66.285 ;
     RECT  2.16 66.555 127.44 66.825 ;
     RECT  2.16 67.095 127.44 67.365 ;
     RECT  2.16 67.635 127.44 67.905 ;
     RECT  2.16 68.175 127.44 68.445 ;
     RECT  2.16 68.715 127.44 68.985 ;
    LAYER M1 ;
     RECT  2.16 2.151 127.44 69.129 ;
    LAYER M2 ;
     RECT  2.16 2.151 49.639 69.129 ;
     RECT  49.639 2.106 50.783 69.129 ;
     RECT  50.783 2.151 60.655 69.129 ;
     RECT  62.203 1.152 63.023 1.17 ;
     RECT  60.655 2.106 63.095 69.129 ;
     RECT  65.875 70.65 66.047 70.668 ;
     RECT  63.095 2.151 70.699 69.129 ;
     RECT  70.699 2.106 71.483 69.129 ;
     RECT  71.483 2.151 72.391 69.129 ;
     RECT  72.391 1.728 72.599 69.129 ;
     RECT  71.527 70.686 74.147 70.704 ;
     RECT  72.599 2.151 78.043 69.129 ;
     RECT  76.927 71.082 79.115 71.1 ;
     RECT  78.043 2.151 79.403 69.21 ;
     RECT  79.403 2.151 127.44 69.129 ;
    LAYER M3 ;
     RECT  46.008 0.091 46.026 0.139 ;
     RECT  56.88 0.091 56.898 0.139 ;
     RECT  51.336 0.139 54.594 0.187 ;
     RECT  55.512 0.139 56.898 0.187 ;
     RECT  62.172 0.091 62.19 0.187 ;
     RECT  69.588 0.139 69.606 0.187 ;
     RECT  70.704 0.139 70.722 0.187 ;
     RECT  45.756 0.139 46.71 0.235 ;
     RECT  47.448 0.139 48.186 0.235 ;
     RECT  69.588 0.187 69.786 0.235 ;
     RECT  74.124 0.139 74.142 0.235 ;
     RECT  70.632 0.187 70.722 0.283 ;
     RECT  51.336 0.187 56.898 0.317 ;
     RECT  45.756 0.235 48.186 0.331 ;
     RECT  62.172 0.187 62.226 0.331 ;
     RECT  51.336 0.317 56.322 0.475 ;
     RECT  61.524 0.331 62.226 0.475 ;
     RECT  72.18 0.379 72.198 0.475 ;
     RECT  73.26 0.139 73.278 0.475 ;
     RECT  45.144 0.331 48.186 0.523 ;
     RECT  50.832 0.475 56.322 0.523 ;
     RECT  59.472 0.139 59.49 0.523 ;
     RECT  61.272 0.475 62.226 0.523 ;
     RECT  68.616 0.139 68.634 0.523 ;
     RECT  69.408 0.235 69.786 0.523 ;
     RECT  44.568 0.523 48.186 0.571 ;
     RECT  59.472 0.523 59.706 0.571 ;
     RECT  68.616 0.523 69.786 0.571 ;
     RECT  70.632 0.283 71.37 0.571 ;
     RECT  77.508 0.139 77.526 0.571 ;
     RECT  68.616 0.571 71.37 1.003 ;
     RECT  72.18 0.475 73.278 1.003 ;
     RECT  41.724 0.139 41.742 1.099 ;
     RECT  61.02 0.523 62.226 1.147 ;
     RECT  63 0.139 63.018 1.147 ;
     RECT  58.176 1.147 58.194 1.195 ;
     RECT  59.472 0.571 59.886 1.195 ;
     RECT  77.508 0.571 77.634 1.675 ;
     RECT  41.724 1.099 42.174 1.723 ;
     RECT  44.568 0.571 48.582 1.723 ;
     RECT  50.256 0.523 56.322 1.723 ;
     RECT  58.176 1.195 59.886 1.723 ;
     RECT  68.616 1.003 73.278 1.723 ;
     RECT  74.088 0.235 74.142 1.723 ;
     RECT  77.4 1.675 77.634 1.723 ;
     RECT  43.668 1.723 43.686 1.819 ;
     RECT  58.176 1.723 59.994 1.819 ;
     RECT  61.02 1.147 63.018 1.819 ;
     RECT  50.256 1.723 56.97 1.915 ;
     RECT  50.256 1.915 57.006 2.101 ;
     RECT  58.176 1.819 60.03 2.101 ;
     RECT  61.02 1.819 63.162 2.101 ;
     RECT  77.4 1.723 77.958 2.143 ;
     RECT  41.724 1.723 42.714 2.191 ;
     RECT  43.488 1.819 43.686 2.191 ;
     RECT  44.568 1.723 48.87 2.191 ;
     RECT  68.616 1.723 74.142 2.191 ;
     RECT  49.644 2.101 57.006 2.263 ;
     RECT  41.724 2.191 48.87 2.371 ;
     RECT  49.644 2.263 57.15 2.371 ;
     RECT  58.176 2.101 63.162 2.371 ;
     RECT  77.4 2.143 78.105 2.371 ;
     RECT  2.415 2.143 2.505 2.413 ;
     RECT  7.815 2.143 7.905 2.413 ;
     RECT  13.215 2.143 13.305 2.413 ;
     RECT  18.615 2.143 18.705 2.413 ;
     RECT  24.015 2.143 24.105 2.413 ;
     RECT  29.415 2.143 29.505 2.413 ;
     RECT  34.815 2.143 34.905 2.413 ;
     RECT  40.215 2.143 40.305 2.413 ;
     RECT  67.215 2.143 67.305 2.413 ;
     RECT  83.415 2.143 83.505 2.413 ;
     RECT  88.815 2.143 88.905 2.413 ;
     RECT  94.215 2.143 94.305 2.413 ;
     RECT  99.615 2.143 99.705 2.413 ;
     RECT  105.015 2.143 105.105 2.413 ;
     RECT  110.415 2.143 110.505 2.413 ;
     RECT  115.815 2.143 115.905 2.413 ;
     RECT  121.215 2.143 121.305 2.413 ;
     RECT  126.615 2.143 126.705 2.413 ;
     RECT  68.616 2.191 74.214 2.525 ;
     RECT  58.176 2.371 63.522 2.569 ;
     RECT  41.724 2.371 57.15 2.641 ;
     RECT  58.176 2.569 63.81 2.641 ;
     RECT  68.868 2.525 74.214 2.641 ;
     RECT  75.024 2.263 75.042 2.641 ;
     RECT  77.4 2.371 78.57 2.641 ;
     RECT  41.724 2.641 63.81 2.795 ;
     RECT  42.156 2.795 63.81 3.065 ;
     RECT  42.48 3.065 63.81 3.181 ;
     RECT  68.868 2.641 75.042 3.181 ;
     RECT  76.824 2.641 78.57 3.181 ;
     RECT  76.716 3.181 78.57 3.379 ;
     RECT  42.48 3.181 63.918 3.451 ;
     RECT  42.48 3.451 64.026 3.875 ;
     RECT  42.84 3.875 64.026 5.539 ;
     RECT  42.84 5.539 64.386 5.611 ;
     RECT  42.84 5.611 64.566 5.881 ;
     RECT  68.868 3.181 75.222 6.241 ;
     RECT  42.84 5.881 65.43 6.655 ;
     RECT  67.215 2.413 67.497 6.691 ;
     RECT  42.804 6.655 65.43 6.809 ;
     RECT  42.84 6.809 65.43 6.961 ;
     RECT  42.84 6.961 65.502 7.051 ;
     RECT  68.868 6.241 75.438 7.115 ;
     RECT  42.84 7.051 65.538 7.159 ;
     RECT  42.84 7.159 65.574 7.429 ;
     RECT  42.84 7.429 65.646 7.465 ;
     RECT  66.636 6.691 67.497 7.465 ;
     RECT  68.868 7.115 75.402 7.771 ;
     RECT  76.716 3.379 78.642 7.897 ;
     RECT  76.716 7.897 79.362 8.041 ;
     RECT  42.84 7.465 67.59 8.131 ;
     RECT  68.364 7.771 75.402 8.131 ;
     RECT  42.84 8.131 75.402 8.159 ;
     RECT  76.716 8.041 79.506 8.401 ;
     RECT  42.84 8.159 75.366 8.429 ;
     RECT  76.716 8.401 79.542 8.491 ;
     RECT  42.876 8.429 75.366 8.717 ;
     RECT  80.352 7.897 80.37 8.815 ;
     RECT  80.352 8.815 80.55 8.851 ;
     RECT  43.524 8.717 75.366 8.941 ;
     RECT  76.536 8.491 79.542 8.941 ;
     RECT  80.352 8.851 80.586 8.941 ;
     RECT  43.524 8.941 79.542 9.085 ;
     RECT  80.352 8.941 80.694 9.085 ;
     RECT  43.524 9.085 80.694 9.113 ;
     RECT  43.524 9.113 76.95 9.239 ;
     RECT  77.796 9.113 80.694 9.653 ;
     RECT  43.524 9.239 76.23 9.689 ;
     RECT  76.968 9.931 76.986 10.193 ;
     RECT  43.56 9.689 76.23 10.319 ;
     RECT  78.015 9.653 80.694 10.391 ;
     RECT  44.28 10.319 76.014 10.493 ;
     RECT  42.912 10.555 43.506 10.877 ;
     RECT  41.832 10.831 41.85 10.925 ;
     RECT  42.912 10.877 43.398 11.083 ;
     RECT  42.732 11.083 43.398 11.129 ;
     RECT  78.015 10.391 80.586 11.399 ;
     RECT  43.056 11.129 43.398 11.755 ;
     RECT  44.28 10.493 75.87 11.755 ;
     RECT  43.056 11.755 75.87 11.933 ;
     RECT  78.015 11.399 79.47 11.939 ;
     RECT  80.208 11.399 80.586 11.939 ;
     RECT  43.776 11.933 75.87 11.947 ;
     RECT  43.776 11.947 75.906 12.091 ;
     RECT  76.788 11.821 76.806 12.091 ;
     RECT  78.015 11.939 79.434 12.245 ;
     RECT  78.015 12.245 79.002 12.389 ;
     RECT  43.776 12.091 76.806 12.631 ;
     RECT  43.776 12.631 77.094 12.811 ;
     RECT  43.38 12.811 77.094 12.901 ;
     RECT  43.38 12.901 77.274 13.019 ;
     RECT  43.668 13.019 77.274 13.613 ;
     RECT  44.352 13.613 77.274 14.171 ;
     RECT  44.352 14.171 75.942 14.783 ;
     RECT  76.752 14.171 77.058 14.909 ;
     RECT  44.82 14.783 75.942 14.945 ;
     RECT  44.856 14.945 75.942 15.061 ;
     RECT  44.856 15.061 76.05 15.179 ;
     RECT  44.856 15.179 75.942 15.821 ;
     RECT  46.908 15.821 75.942 16.141 ;
     RECT  46.908 16.141 75.978 16.169 ;
     RECT  48.312 16.169 75.978 16.493 ;
     RECT  48.528 16.493 75.978 16.565 ;
     RECT  48.708 16.565 75.978 16.673 ;
     RECT  48.744 16.673 75.978 16.799 ;
     RECT  48.78 16.799 75.978 16.951 ;
     RECT  76.788 14.909 77.058 16.951 ;
     RECT  48.78 16.951 77.058 17.185 ;
     RECT  78.015 12.389 78.297 17.185 ;
     RECT  48.78 17.185 78.297 17.681 ;
     RECT  49.536 17.681 78.297 17.689 ;
     RECT  49.536 17.689 78.642 17.951 ;
     RECT  80.568 11.939 80.586 17.951 ;
     RECT  49.536 17.951 78.297 19.373 ;
     RECT  44.856 15.821 46.098 19.387 ;
     RECT  46.908 16.169 46.998 19.387 ;
     RECT  49.536 19.373 76.41 19.769 ;
     RECT  44.856 19.387 46.998 19.963 ;
     RECT  47.808 19.921 47.826 20.191 ;
     RECT  47.808 20.191 47.934 20.309 ;
     RECT  49.752 19.769 76.41 20.381 ;
     RECT  52.596 20.381 74.718 20.417 ;
     RECT  44.604 19.963 46.998 20.579 ;
     RECT  49.752 20.381 51.297 20.579 ;
     RECT  44.604 20.579 44.622 20.615 ;
     RECT  52.596 20.417 74.106 20.849 ;
     RECT  50.508 20.579 51.297 20.885 ;
     RECT  52.956 20.849 74.106 20.885 ;
     RECT  53.46 20.885 53.91 20.957 ;
     RECT  77.436 19.373 78.297 21.091 ;
     RECT  45.615 20.579 46.998 21.149 ;
     RECT  54.648 20.885 74.106 21.163 ;
     RECT  53.64 20.957 53.91 21.389 ;
     RECT  54.648 21.163 74.25 21.389 ;
     RECT  75.564 20.381 76.41 21.505 ;
     RECT  77.184 21.091 78.297 21.505 ;
     RECT  55.656 21.389 74.25 21.533 ;
     RECT  45.615 21.149 46.35 21.569 ;
     RECT  54.648 21.389 54.774 21.569 ;
     RECT  55.656 21.533 56.898 21.569 ;
     RECT  54.648 21.569 54.738 21.659 ;
     RECT  55.656 21.569 55.674 21.659 ;
     RECT  58.284 21.533 74.25 21.659 ;
     RECT  53.712 21.389 53.91 21.695 ;
     RECT  75.564 21.505 78.297 21.703 ;
     RECT  59.976 21.659 74.25 21.731 ;
     RECT  53.82 21.695 53.91 21.811 ;
     RECT  75.348 21.703 78.297 21.901 ;
     RECT  53.82 21.811 53.946 21.929 ;
     RECT  56.415 21.569 56.898 21.929 ;
     RECT  53.82 21.929 53.838 21.965 ;
     RECT  60.192 21.731 74.25 21.973 ;
     RECT  60.192 21.973 74.322 22.009 ;
     RECT  75.24 21.901 78.297 22.009 ;
     RECT  60.192 22.009 78.297 22.045 ;
     RECT  60.192 22.045 78.39 22.315 ;
     RECT  58.284 21.659 59.238 22.541 ;
     RECT  54.72 21.659 54.738 22.613 ;
     RECT  58.284 22.541 58.302 22.621 ;
     RECT  60.192 22.315 78.75 22.811 ;
     RECT  75.672 22.811 78.75 22.891 ;
     RECT  57.636 22.621 58.302 22.919 ;
     RECT  60.192 22.811 74.754 22.981 ;
     RECT  57.636 22.919 58.05 23.045 ;
     RECT  59.04 22.541 59.238 23.053 ;
     RECT  60.12 22.981 74.754 23.053 ;
     RECT  75.672 22.891 78.894 23.081 ;
     RECT  75.672 23.081 78.822 23.549 ;
     RECT  59.04 23.053 74.754 23.585 ;
     RECT  59.904 23.585 74.754 23.621 ;
     RECT  60.192 23.621 74.754 23.701 ;
     RECT  75.672 23.549 78.75 23.701 ;
     RECT  56.415 21.929 56.826 23.791 ;
     RECT  56.304 23.791 56.826 23.837 ;
     RECT  58.716 23.803 58.734 23.933 ;
     RECT  60.192 23.701 78.75 25.141 ;
     RECT  60.192 25.141 78.93 25.411 ;
     RECT  60.192 25.411 79.398 25.555 ;
     RECT  60.192 25.555 79.47 25.591 ;
     RECT  56.415 23.837 56.826 26.123 ;
     RECT  60.192 25.591 79.83 26.123 ;
     RECT  60.192 26.123 79.794 26.941 ;
     RECT  60.192 26.941 80.01 27.067 ;
     RECT  60.192 27.067 80.082 27.139 ;
     RECT  60.192 27.139 80.19 27.481 ;
     RECT  49.752 20.579 49.77 27.599 ;
     RECT  60.192 27.481 80.91 27.671 ;
     RECT  52.02 27.751 52.038 27.869 ;
     RECT  60.192 27.671 80.19 27.869 ;
     RECT  60.192 27.869 80.118 28.013 ;
     RECT  60.192 28.013 80.046 28.319 ;
     RECT  60.192 28.319 79.326 28.489 ;
     RECT  59.796 28.489 79.326 28.715 ;
     RECT  59.832 28.715 79.326 29.489 ;
     RECT  59.832 29.489 79.146 29.911 ;
     RECT  59.148 29.911 79.146 30.037 ;
     RECT  58.86 30.037 79.146 30.145 ;
     RECT  58.824 30.145 79.146 30.407 ;
     RECT  58.86 30.407 79.146 30.713 ;
     RECT  59.472 30.713 79.146 30.839 ;
     RECT  59.796 30.839 79.146 31.801 ;
     RECT  59.652 31.801 79.146 31.891 ;
     RECT  59.652 31.891 79.65 31.919 ;
     RECT  59.868 31.919 79.65 32.063 ;
     RECT  60.084 32.063 79.65 33.035 ;
     RECT  60.48 33.035 79.65 33.143 ;
     RECT  61.308 33.143 79.65 34.555 ;
     RECT  61.308 34.555 79.794 34.591 ;
     RECT  61.308 34.591 80.118 34.637 ;
     RECT  61.308 34.637 79.65 53.321 ;
     RECT  61.452 53.321 79.65 54.481 ;
     RECT  61.452 54.481 79.938 54.571 ;
     RECT  61.452 54.571 79.974 54.608 ;
     RECT  61.452 54.608 79.938 55.085 ;
     RECT  61.452 55.085 79.902 55.139 ;
     RECT  61.452 55.139 62.37 56.129 ;
     RECT  63.396 55.139 79.902 56.371 ;
     RECT  63.396 56.371 80.622 57.019 ;
     RECT  63.396 57.019 80.946 57.137 ;
     RECT  64.26 57.137 80.946 57.991 ;
     RECT  63.396 57.137 63.414 58.019 ;
     RECT  50.616 20.885 51.297 60.961 ;
     RECT  64.26 57.991 81.018 60.961 ;
     RECT  50.616 60.961 51.462 60.989 ;
     RECT  60.48 33.143 60.498 61.079 ;
     RECT  64.008 60.961 81.018 61.259 ;
     RECT  70.02 61.259 81.018 61.349 ;
     RECT  61.815 56.129 62.37 61.799 ;
     RECT  51.015 60.989 51.462 61.969 ;
     RECT  48.78 17.681 48.798 61.997 ;
     RECT  51.015 61.969 51.858 62.041 ;
     RECT  60.588 61.231 60.606 62.267 ;
     RECT  51.015 62.041 52.002 62.275 ;
     RECT  64.008 61.259 69.282 62.303 ;
     RECT  51.015 62.275 52.686 62.311 ;
     RECT  64.116 62.303 69.282 62.339 ;
     RECT  64.116 62.339 68.994 62.429 ;
     RECT  51.015 62.311 53.118 62.465 ;
     RECT  53.1 62.465 53.118 62.501 ;
     RECT  64.296 62.429 68.994 62.537 ;
     RECT  51.015 62.465 52.362 62.765 ;
     RECT  52.164 62.765 52.362 62.879 ;
     RECT  70.092 61.349 81.018 63.823 ;
     RECT  70.092 63.823 81.054 64.363 ;
     RECT  70.092 64.363 81.342 64.831 ;
     RECT  69.588 64.831 81.342 65.443 ;
     RECT  82.26 65.371 82.278 65.443 ;
     RECT  64.296 62.537 68.562 65.471 ;
     RECT  64.296 65.471 68.49 66.361 ;
     RECT  64.224 66.361 68.49 66.901 ;
     RECT  69.588 65.443 82.278 67.289 ;
     RECT  63.864 66.901 68.49 67.469 ;
     RECT  63.864 67.469 68.202 67.981 ;
     RECT  52.344 62.879 52.362 68.405 ;
     RECT  63.792 67.981 68.202 68.405 ;
     RECT  51.015 62.765 51.297 68.521 ;
     RECT  69.696 67.289 82.278 68.675 ;
     RECT  51.015 68.521 51.39 68.791 ;
     RECT  2.415 2.413 2.697 68.867 ;
     RECT  7.815 2.413 8.097 68.867 ;
     RECT  13.215 2.413 13.497 68.867 ;
     RECT  18.615 2.413 18.897 68.867 ;
     RECT  24.015 2.413 24.297 68.867 ;
     RECT  29.415 2.413 29.697 68.867 ;
     RECT  34.815 2.413 35.097 68.867 ;
     RECT  40.215 2.413 40.497 68.867 ;
     RECT  45.615 21.569 45.897 68.867 ;
     RECT  56.415 26.123 56.697 68.867 ;
     RECT  61.815 61.799 62.097 68.867 ;
     RECT  83.415 2.413 83.697 68.867 ;
     RECT  88.815 2.413 89.097 68.867 ;
     RECT  94.215 2.413 94.497 68.867 ;
     RECT  99.615 2.413 99.897 68.867 ;
     RECT  105.015 2.413 105.297 68.867 ;
     RECT  110.415 2.413 110.697 68.867 ;
     RECT  115.815 2.413 116.097 68.867 ;
     RECT  121.215 2.413 121.497 68.867 ;
     RECT  126.615 2.413 126.897 68.867 ;
     RECT  69.876 68.675 82.278 68.875 ;
     RECT  69.876 68.875 82.35 68.915 ;
     RECT  69.876 68.915 82.278 68.945 ;
     RECT  64.008 68.405 68.202 68.957 ;
     RECT  64.692 68.957 68.202 69.053 ;
     RECT  51.015 68.791 51.606 69.061 ;
     RECT  2.415 68.867 2.505 69.137 ;
     RECT  7.815 68.867 7.905 69.137 ;
     RECT  13.215 68.867 13.305 69.137 ;
     RECT  18.615 68.867 18.705 69.137 ;
     RECT  24.015 68.867 24.105 69.137 ;
     RECT  29.415 68.867 29.505 69.137 ;
     RECT  34.815 68.867 34.905 69.137 ;
     RECT  40.215 68.867 40.305 69.137 ;
     RECT  45.615 68.867 45.705 69.137 ;
     RECT  51.015 69.061 51.75 69.137 ;
     RECT  56.415 68.867 56.505 69.137 ;
     RECT  61.815 68.867 61.905 69.137 ;
     RECT  64.692 69.053 67.305 69.137 ;
     RECT  83.415 68.867 83.505 69.137 ;
     RECT  88.815 68.867 88.905 69.137 ;
     RECT  94.215 68.867 94.305 69.137 ;
     RECT  99.615 68.867 99.705 69.137 ;
     RECT  105.015 68.867 105.105 69.137 ;
     RECT  110.415 68.867 110.505 69.137 ;
     RECT  115.815 68.867 115.905 69.137 ;
     RECT  121.215 68.867 121.305 69.137 ;
     RECT  126.615 68.867 126.705 69.137 ;
     RECT  64.692 69.137 66.906 69.149 ;
     RECT  64.692 69.149 66.654 69.197 ;
     RECT  64.692 69.197 66.582 69.677 ;
     RECT  69.876 68.945 81.162 69.677 ;
     RECT  51.732 69.137 51.75 70.109 ;
     RECT  69.876 69.677 70.614 70.157 ;
     RECT  64.692 69.677 66.546 70.205 ;
     RECT  71.532 69.677 81.162 70.685 ;
     RECT  71.532 70.685 73.242 70.709 ;
     RECT  70.596 70.157 70.614 70.733 ;
     RECT  71.82 70.709 73.242 70.733 ;
     RECT  73.98 70.685 79.11 70.733 ;
     RECT  71.82 70.733 73.17 70.781 ;
     RECT  65.16 70.205 66.474 71.035 ;
     RECT  65.16 71.035 66.546 71.069 ;
     RECT  74.124 70.733 79.11 71.069 ;
     RECT  79.92 70.685 81.162 71.069 ;
     RECT  76.5 71.069 79.11 71.105 ;
     RECT  65.16 71.069 65.178 71.117 ;
     RECT  65.952 71.069 66.546 71.117 ;
     RECT  71.82 70.781 73.098 71.117 ;
     RECT  74.124 71.069 75.69 71.117 ;
     RECT  76.5 71.105 78.534 71.117 ;
     RECT  80.352 71.069 81.162 71.117 ;
     RECT  74.124 71.117 74.142 71.165 ;
     RECT  75.096 71.117 75.69 71.165 ;
     RECT  78.156 71.117 78.534 71.165 ;
     RECT  81 71.117 81.162 71.165 ;
     RECT  66.528 71.117 66.546 71.261 ;
     RECT  68.184 69.053 68.202 71.261 ;
     RECT  78.156 71.165 78.174 71.261 ;
     RECT  81.144 71.165 81.162 71.261 ;
    LAYER M4 ;
     RECT  2.408 2.148 2.512 69.132 ;
     RECT  2.512 2.418 2.704 68.862 ;
     RECT  7.808 2.148 7.912 69.132 ;
     RECT  7.912 2.418 8.104 68.862 ;
     RECT  13.208 2.148 13.312 69.132 ;
     RECT  13.312 2.418 13.504 68.862 ;
     RECT  18.608 2.148 18.712 69.132 ;
     RECT  18.712 2.418 18.904 68.862 ;
     RECT  24.008 2.148 24.112 69.132 ;
     RECT  24.112 2.418 24.304 68.862 ;
     RECT  29.408 2.148 29.512 69.132 ;
     RECT  29.512 2.418 29.704 68.862 ;
     RECT  34.808 2.148 34.912 69.132 ;
     RECT  34.912 2.418 35.104 68.862 ;
     RECT  40.208 2.148 40.312 69.132 ;
     RECT  40.312 2.418 40.504 68.862 ;
     RECT  41.713 0.144 42.145 0.168 ;
     RECT  42.145 0.144 42.323 1.128 ;
     RECT  42.323 1.104 42.371 1.128 ;
     RECT  42.373 1.728 42.421 1.752 ;
     RECT  42.421 1.728 42.469 2.04 ;
     RECT  42.469 1.728 42.563 2.28 ;
     RECT  42.563 1.728 42.581 1.944 ;
     RECT  42.581 1.728 42.697 1.896 ;
     RECT  41.821 10.896 42.721 10.92 ;
     RECT  42.721 10.896 42.86 11.112 ;
     RECT  42.865 8.688 42.901 8.712 ;
     RECT  42.901 8.16 43.045 8.712 ;
     RECT  42.86 10.56 43.045 11.112 ;
     RECT  43.045 10.56 43.333 11.928 ;
     RECT  43.333 10.272 43.369 11.928 ;
     RECT  43.045 7.968 43.379 8.712 ;
     RECT  43.379 8.16 43.484 8.712 ;
     RECT  43.369 10.272 43.484 12.84 ;
     RECT  43.484 8.16 43.571 12.84 ;
     RECT  43.571 9.696 43.657 12.84 ;
     RECT  42.697 1.728 43.697 1.848 ;
     RECT  43.697 1.824 43.715 1.848 ;
     RECT  43.571 8.16 43.715 8.712 ;
     RECT  43.657 9.696 43.741 13.608 ;
     RECT  43.741 10.032 44.629 13.608 ;
     RECT  43.715 8.16 44.732 8.568 ;
     RECT  44.732 8.16 44.845 8.904 ;
     RECT  44.629 10.032 44.845 14.472 ;
     RECT  45.061 3.984 45.097 4.008 ;
     RECT  44.557 0.528 45.133 0.552 ;
     RECT  45.133 0.336 45.308 0.552 ;
     RECT  45.097 2.016 45.308 2.04 ;
     RECT  44.845 8.16 45.349 14.472 ;
     RECT  44.588 19.968 45.452 19.992 ;
     RECT  45.452 19.92 45.493 19.992 ;
     RECT  45.308 0.336 45.608 2.04 ;
     RECT  45.097 3.408 45.608 4.008 ;
     RECT  45.349 7.68 45.608 14.472 ;
     RECT  43.333 15.504 45.608 15.528 ;
     RECT  45.493 19.92 45.608 20.616 ;
     RECT  45.608 0.336 45.701 69.132 ;
     RECT  45.701 0.144 45.712 69.132 ;
     RECT  45.712 0.144 45.904 68.862 ;
     RECT  45.904 0.144 45.953 2.28 ;
     RECT  45.953 0.096 46.001 2.28 ;
     RECT  45.904 19.392 46.001 20.616 ;
     RECT  46.001 0.096 46.037 0.744 ;
     RECT  45.904 3.408 46.067 5.208 ;
     RECT  46.037 0.144 46.115 0.744 ;
     RECT  45.904 7.68 46.181 8.52 ;
     RECT  45.904 9.504 46.211 15.816 ;
     RECT  46.067 3.408 46.499 4.584 ;
     RECT  46.001 1.728 46.547 2.28 ;
     RECT  46.211 9.936 46.547 15.816 ;
     RECT  46.001 19.392 46.649 20.136 ;
     RECT  46.499 4.416 46.721 4.584 ;
     RECT  46.547 9.936 46.793 14.472 ;
     RECT  45.904 6.288 46.937 6.408 ;
     RECT  46.547 15.456 47.029 15.816 ;
     RECT  46.115 0.144 47.219 0.648 ;
     RECT  46.181 7.68 47.293 8.472 ;
     RECT  46.793 9.936 47.293 14.376 ;
     RECT  46.937 6.288 47.297 6.36 ;
     RECT  47.069 5.136 47.393 5.16 ;
     RECT  46.499 3.408 47.473 3.432 ;
     RECT  47.393 5.136 47.477 5.736 ;
     RECT  47.473 3.408 47.701 4.008 ;
     RECT  47.477 5.136 47.701 5.256 ;
     RECT  46.547 1.728 47.761 2.232 ;
     RECT  47.701 3.408 47.801 5.16 ;
     RECT  47.761 1.728 47.891 2.28 ;
     RECT  47.801 5.136 47.909 5.16 ;
     RECT  47.293 7.68 47.989 14.376 ;
     RECT  47.029 15.456 47.989 16.152 ;
     RECT  47.801 3.408 48.053 3.96 ;
     RECT  47.989 7.68 48.089 16.152 ;
     RECT  48.089 7.68 48.113 8.472 ;
     RECT  47.219 0.144 48.197 0.6 ;
     RECT  48.113 7.392 48.197 8.472 ;
     RECT  48.053 3.408 48.205 3.528 ;
     RECT  47.891 1.728 48.269 1.896 ;
     RECT  48.089 9.648 48.301 16.152 ;
     RECT  48.269 1.728 48.341 1.848 ;
     RECT  48.205 3.504 48.377 3.528 ;
     RECT  48.197 0.576 48.593 0.6 ;
     RECT  48.301 9.648 48.665 16.488 ;
     RECT  48.341 1.728 48.881 1.752 ;
     RECT  48.197 8.16 49.237 8.472 ;
     RECT  49.237 7.776 49.445 9 ;
     RECT  48.665 10.272 49.813 16.488 ;
     RECT  49.813 10.176 49.849 16.488 ;
     RECT  49.445 7.392 50.101 9 ;
     RECT  49.849 10.176 50.101 16.536 ;
     RECT  50.101 7.392 50.137 16.536 ;
     RECT  50.204 0.528 50.281 0.552 ;
     RECT  50.281 0.528 50.341 1.176 ;
     RECT  50.317 2.256 50.341 2.28 ;
     RECT  50.137 6.816 50.353 17.448 ;
     RECT  50.281 3.408 50.677 3.432 ;
     RECT  50.677 3.312 50.713 3.432 ;
     RECT  50.341 0.528 50.725 2.28 ;
     RECT  50.713 3.312 50.725 4.008 ;
     RECT  50.725 0.528 50.749 4.008 ;
     RECT  46.649 20.112 50.773 20.136 ;
     RECT  50.749 0.528 50.821 4.104 ;
     RECT  50.725 5.136 50.821 5.16 ;
     RECT  50.773 19.536 50.849 20.136 ;
     RECT  46.969 21.12 50.849 21.144 ;
     RECT  50.821 0.48 51.008 5.16 ;
     RECT  50.353 6.816 51.008 18.264 ;
     RECT  50.849 19.536 51.008 21.144 ;
     RECT  48.709 23.664 51.008 23.688 ;
     RECT  50.869 27.6 51.008 27.624 ;
     RECT  51.008 0.48 51.112 69.132 ;
     RECT  51.112 0.48 51.155 68.862 ;
     RECT  51.155 0.48 51.253 0.552 ;
     RECT  51.155 1.68 51.304 68.862 ;
     RECT  51.304 6.72 51.401 18.168 ;
     RECT  51.304 1.68 51.539 1.848 ;
     RECT  51.304 2.976 51.761 5.304 ;
     RECT  51.761 2.976 51.779 5.16 ;
     RECT  51.721 70.08 51.805 70.104 ;
     RECT  51.779 3.312 51.833 5.16 ;
     RECT  51.253 0.144 51.923 0.552 ;
     RECT  51.833 3.312 52.085 4.872 ;
     RECT  51.539 1.728 52.333 1.848 ;
     RECT  51.401 6.72 52.549 18.12 ;
     RECT  52.085 3.408 52.933 4.872 ;
     RECT  51.304 20.112 52.945 20.136 ;
     RECT  51.304 21.12 52.945 21.144 ;
     RECT  52.933 3.408 53.029 5.112 ;
     RECT  53.029 3.408 53.093 5.208 ;
     RECT  53.093 5.088 53.116 5.208 ;
     RECT  53.116 5.088 53.129 5.16 ;
     RECT  51.923 0.144 53.153 0.312 ;
     RECT  52.945 20.112 53.161 21.144 ;
     RECT  53.093 3.408 53.363 4.056 ;
     RECT  53.363 3.408 53.453 3.96 ;
     RECT  52.549 6.288 53.557 18.12 ;
     RECT  53.557 6.288 53.66 18.216 ;
     RECT  53.161 19.392 53.66 21.144 ;
     RECT  53.66 6.288 53.701 21.144 ;
     RECT  53.701 6.288 53.785 21.672 ;
     RECT  53.153 0.144 53.891 0.6 ;
     RECT  53.785 6.288 54.065 21.24 ;
     RECT  52.333 1.728 54.131 2.28 ;
     RECT  53.129 5.136 54.133 5.16 ;
     RECT  54.065 6.288 54.133 6.984 ;
     RECT  54.133 5.136 54.281 6.984 ;
     RECT  54.065 8.208 54.325 21.24 ;
     RECT  53.453 3.408 54.469 3.432 ;
     RECT  54.325 8.208 54.755 19.416 ;
     RECT  54.281 5.136 54.773 6.888 ;
     RECT  54.773 4.512 54.857 6.888 ;
     RECT  54.469 3.408 54.889 3.48 ;
     RECT  54.889 3.312 55.043 3.48 ;
     RECT  54.857 5.136 55.181 6.888 ;
     RECT  55.043 3.408 55.213 3.48 ;
     RECT  54.131 1.728 55.285 1.848 ;
     RECT  54.755 19.392 55.397 19.416 ;
     RECT  54.755 8.208 55.429 18.216 ;
     RECT  53.891 0.144 55.681 0.552 ;
     RECT  55.285 1.728 55.681 2.28 ;
     RECT  55.181 6.816 55.753 6.888 ;
     RECT  55.429 7.968 55.753 18.216 ;
     RECT  55.753 6.816 55.861 18.216 ;
     RECT  55.213 3.408 55.957 4.008 ;
     RECT  55.181 5.136 55.957 5.736 ;
     RECT  55.681 0.144 56.051 2.28 ;
     RECT  56.051 1.728 56.113 2.28 ;
     RECT  55.957 3.408 56.113 5.736 ;
     RECT  56.051 0.144 56.243 0.648 ;
     RECT  54.325 20.4 56.401 21.24 ;
     RECT  56.113 1.728 56.408 5.736 ;
     RECT  55.861 6.816 56.408 18.504 ;
     RECT  56.401 20.352 56.408 21.24 ;
     RECT  51.304 23.808 56.408 23.832 ;
     RECT  51.304 62.736 56.408 62.76 ;
     RECT  56.408 1.728 56.512 69.132 ;
     RECT  56.512 1.728 56.704 68.862 ;
     RECT  56.243 0.144 56.773 0.312 ;
     RECT  56.704 1.728 56.867 5.112 ;
     RECT  56.773 0.096 56.909 0.312 ;
     RECT  56.909 0.144 56.915 0.312 ;
     RECT  56.867 3.216 56.915 5.112 ;
     RECT  56.915 0.192 56.963 0.312 ;
     RECT  56.867 1.728 56.981 1.944 ;
     RECT  56.963 0.192 57.011 0.216 ;
     RECT  56.981 1.92 57.017 1.944 ;
     RECT  56.915 3.216 57.125 4.008 ;
     RECT  57.125 3.216 57.251 3.24 ;
     RECT  56.704 6.192 57.299 21.48 ;
     RECT  56.915 5.088 57.305 5.112 ;
     RECT  57.829 22.8 58.061 22.824 ;
     RECT  58.165 2.832 58.201 2.856 ;
     RECT  58.165 1.152 58.237 1.176 ;
     RECT  58.201 2.256 58.237 2.856 ;
     RECT  58.237 1.152 58.345 2.856 ;
     RECT  58.345 1.152 58.451 3.432 ;
     RECT  58.451 1.2 58.499 3.432 ;
     RECT  58.499 3.408 58.625 3.432 ;
     RECT  56.704 23.808 58.705 23.832 ;
     RECT  58.625 3.408 58.709 3.72 ;
     RECT  57.299 6.24 58.745 21.48 ;
     RECT  58.705 23.808 58.745 23.928 ;
     RECT  58.499 1.2 58.781 2.04 ;
     RECT  58.781 1.728 59.033 2.04 ;
     RECT  59.461 0.144 59.677 0.168 ;
     RECT  58.745 6.864 59.756 21.48 ;
     RECT  59.677 0.144 59.785 0.552 ;
     RECT  59.033 1.728 59.785 1.848 ;
     RECT  59.756 6.816 59.843 21.48 ;
     RECT  59.785 0.144 59.987 1.848 ;
     RECT  59.987 1.728 60.005 1.848 ;
     RECT  60.005 1.824 60.041 1.848 ;
     RECT  59.987 0.144 60.131 0.552 ;
     RECT  59.843 7.056 60.329 21.48 ;
     RECT  58.745 23.904 60.649 23.928 ;
     RECT  60.649 23.184 60.937 23.928 ;
     RECT  60.997 1.968 61.081 1.992 ;
     RECT  61.045 3.408 61.109 3.432 ;
     RECT  60.131 0.528 61.225 0.552 ;
     RECT  61.225 0.528 61.234 0.648 ;
     RECT  61.234 0.48 61.513 0.648 ;
     RECT  61.109 3.408 61.621 4.008 ;
     RECT  61.513 0.336 61.657 0.648 ;
     RECT  61.081 1.728 61.657 1.992 ;
     RECT  61.585 28.8 61.657 28.824 ;
     RECT  61.621 3.408 61.669 4.536 ;
     RECT  60.329 7.056 61.693 21.24 ;
     RECT  60.937 22.848 61.765 23.928 ;
     RECT  61.657 28.704 61.765 28.824 ;
     RECT  61.513 29.856 61.765 29.88 ;
     RECT  61.657 0.336 61.808 1.992 ;
     RECT  61.669 3.312 61.808 4.536 ;
     RECT  61.693 6.864 61.808 21.24 ;
     RECT  61.765 22.848 61.808 24.696 ;
     RECT  61.585 26.736 61.808 26.76 ;
     RECT  61.765 28.704 61.808 29.88 ;
     RECT  61.621 31.44 61.808 31.464 ;
     RECT  61.801 33.12 61.808 33.144 ;
     RECT  56.704 62.736 61.808 62.76 ;
     RECT  61.808 0.336 61.912 69.132 ;
     RECT  61.912 0.336 62.104 68.862 ;
     RECT  62.104 0.336 62.117 2.136 ;
     RECT  62.104 29.76 62.129 29.784 ;
     RECT  62.104 31.056 62.129 31.992 ;
     RECT  62.117 0.096 62.291 2.136 ;
     RECT  62.104 3.408 62.353 4.488 ;
     RECT  62.291 0.096 62.579 1.944 ;
     RECT  62.129 31.056 62.677 31.896 ;
     RECT  62.353 3.408 62.705 4.104 ;
     RECT  62.104 22.464 62.777 26.328 ;
     RECT  62.677 31.44 62.813 31.896 ;
     RECT  62.579 0.096 62.819 0.216 ;
     RECT  62.813 31.632 62.849 31.896 ;
     RECT  62.579 1.728 62.857 1.944 ;
     RECT  62.857 1.824 62.921 1.944 ;
     RECT  62.849 31.68 62.921 31.896 ;
     RECT  62.777 26.304 62.993 26.328 ;
     RECT  62.819 0.096 63.011 0.168 ;
     RECT  63.011 0.144 63.029 0.168 ;
     RECT  62.104 6.816 63.133 21.24 ;
     RECT  62.777 22.464 63.133 24.984 ;
     RECT  62.104 27.312 63.133 27.336 ;
     RECT  62.705 3.408 63.137 3.432 ;
     RECT  63.133 6.816 63.137 24.984 ;
     RECT  63.137 6.816 63.169 24.888 ;
     RECT  62.921 1.824 63.173 1.848 ;
     RECT  63.169 6.72 63.209 24.888 ;
     RECT  63.209 6.72 63.292 24.84 ;
     RECT  63.385 29.088 63.421 29.112 ;
     RECT  62.921 31.824 63.529 31.896 ;
     RECT  63.421 29.088 63.569 29.208 ;
     RECT  63.569 29.184 63.605 29.208 ;
     RECT  63.292 6.72 63.817 23.064 ;
     RECT  63.817 29.712 63.961 29.784 ;
     RECT  63.961 29.712 64.037 29.976 ;
     RECT  63.817 6.24 64.115 23.064 ;
     RECT  64.115 6.672 64.181 23.064 ;
     RECT  64.037 29.76 64.217 29.976 ;
     RECT  63.997 68.928 64.249 68.952 ;
     RECT  63.529 31.824 64.285 31.944 ;
     RECT  63.817 33.072 64.285 33.096 ;
     RECT  63.133 26.88 64.321 27.336 ;
     RECT  64.217 29.76 64.325 29.784 ;
     RECT  64.181 6.672 64.355 22.584 ;
     RECT  64.321 26.304 64.393 27.336 ;
     RECT  64.285 59.28 64.451 59.304 ;
     RECT  63.292 24.432 64.453 24.84 ;
     RECT  64.453 23.568 64.465 24.84 ;
     RECT  64.393 25.968 64.465 27.336 ;
     RECT  64.213 60.432 64.501 60.456 ;
     RECT  64.355 6.816 64.547 22.584 ;
     RECT  64.501 58.704 64.556 58.728 ;
     RECT  64.597 40.416 64.609 40.44 ;
     RECT  64.547 22.176 64.613 22.584 ;
     RECT  64.556 58.656 64.643 58.728 ;
     RECT  64.547 6.816 64.657 21.144 ;
     RECT  63.997 61.632 64.753 61.656 ;
     RECT  64.613 22.176 64.757 22.44 ;
     RECT  64.753 61.536 64.793 61.656 ;
     RECT  64.657 7.392 64.865 21.144 ;
     RECT  64.681 70.176 64.969 70.2 ;
     RECT  64.865 20.544 64.973 21.144 ;
     RECT  64.501 60.432 64.973 60.504 ;
     RECT  64.285 31.824 64.991 33.096 ;
     RECT  64.991 31.776 65.009 33.096 ;
     RECT  64.973 21.12 65.075 21.144 ;
     RECT  64.249 68.4 65.105 68.952 ;
     RECT  64.969 70.08 65.105 70.2 ;
     RECT  65.105 67.776 65.221 68.952 ;
     RECT  65.105 70.08 65.221 71.112 ;
     RECT  65.009 31.776 65.225 33.048 ;
     RECT  65.029 59.856 65.225 59.88 ;
     RECT  65.225 31.776 65.365 33 ;
     RECT  64.865 7.392 65.369 19.56 ;
     RECT  65.324 56.64 65.509 56.664 ;
     RECT  64.793 61.536 65.509 61.56 ;
     RECT  65.42 54.576 65.653 54.6 ;
     RECT  64.609 40.368 65.701 40.44 ;
     RECT  65.509 56.448 65.701 56.664 ;
     RECT  64.757 22.416 65.725 22.44 ;
     RECT  65.369 7.584 65.729 19.56 ;
     RECT  64.643 58.704 65.729 58.728 ;
     RECT  65.653 53.76 65.747 54.6 ;
     RECT  65.725 21.984 65.833 22.44 ;
     RECT  64.465 23.568 65.833 27.336 ;
     RECT  65.747 54.336 65.833 54.6 ;
     RECT  65.833 21.984 65.873 27.336 ;
     RECT  65.761 28.848 65.905 28.872 ;
     RECT  65.221 67.776 65.905 71.112 ;
     RECT  65.365 31.344 65.909 33 ;
     RECT  65.905 28.848 65.981 29.112 ;
     RECT  65.701 56.448 66.053 57.288 ;
     RECT  65.729 7.632 66.083 19.56 ;
     RECT  65.905 67.248 66.085 71.112 ;
     RECT  66.085 66.72 66.089 71.112 ;
     RECT  66.083 7.92 66.121 19.56 ;
     RECT  65.909 31.92 66.125 33 ;
     RECT  66.121 7.92 66.133 20.184 ;
     RECT  66.133 7.92 66.193 20.232 ;
     RECT  65.873 21.984 66.193 27.192 ;
     RECT  66.053 56.448 66.205 56.472 ;
     RECT  65.981 28.896 66.229 29.112 ;
     RECT  65.701 40.368 66.233 41.016 ;
     RECT  66.037 58.656 66.233 58.68 ;
     RECT  66.125 32.208 66.265 33 ;
     RECT  63.205 34.08 66.265 34.104 ;
     RECT  65.833 54.336 66.445 54.744 ;
     RECT  66.229 28.896 66.517 29.16 ;
     RECT  66.089 67.824 66.517 71.112 ;
     RECT  66.517 67.824 66.557 71.256 ;
     RECT  66.557 67.824 66.593 69.672 ;
     RECT  66.593 67.824 66.679 69.192 ;
     RECT  66.679 67.824 66.917 69.144 ;
     RECT  66.445 54.336 67.093 54.792 ;
     RECT  66.193 7.92 67.208 27.192 ;
     RECT  66.517 28.896 67.208 29.688 ;
     RECT  66.265 32.208 67.208 34.104 ;
     RECT  66.233 40.368 67.208 40.872 ;
     RECT  67.093 54.096 67.208 54.792 ;
     RECT  66.445 55.776 67.208 56.424 ;
     RECT  65.509 61.152 67.208 61.56 ;
     RECT  62.104 62.736 67.208 62.76 ;
     RECT  66.089 66.72 67.208 66.84 ;
     RECT  66.917 67.824 67.208 69.132 ;
     RECT  67.208 2.148 67.312 69.132 ;
     RECT  67.312 2.418 67.504 69.048 ;
     RECT  67.504 53.568 67.667 56.232 ;
     RECT  67.504 66.672 67.709 67.464 ;
     RECT  67.667 53.568 67.715 54.072 ;
     RECT  67.667 56.208 67.715 56.232 ;
     RECT  67.504 32.208 67.817 32.328 ;
     RECT  67.709 66.672 67.817 66.84 ;
     RECT  67.504 26.112 67.853 30.12 ;
     RECT  67.817 32.208 67.853 32.28 ;
     RECT  67.817 66.672 67.853 66.696 ;
     RECT  67.504 22.464 67.889 23.592 ;
     RECT  67.853 32.256 67.925 32.28 ;
     RECT  67.504 69.024 67.997 69.048 ;
     RECT  67.504 16.512 68.033 21.432 ;
     RECT  67.715 53.568 68.099 53.592 ;
     RECT  67.504 61.152 68.099 62.76 ;
     RECT  67.504 7.968 68.105 15.48 ;
     RECT  66.557 71.232 68.213 71.256 ;
     RECT  68.033 18 68.249 21.432 ;
     RECT  68.105 7.968 68.321 10.2 ;
     RECT  67.504 24.912 68.497 24.936 ;
     RECT  67.853 26.112 68.497 27.336 ;
     RECT  68.321 7.968 68.581 10.056 ;
     RECT  68.497 24.912 68.753 27.336 ;
     RECT  67.889 22.464 68.771 23.544 ;
     RECT  68.753 24.912 68.789 26.28 ;
     RECT  67.504 33.36 68.876 34.104 ;
     RECT  67.853 28.512 68.915 30.12 ;
     RECT  68.789 25.68 68.933 26.28 ;
     RECT  68.915 28.512 68.956 29.832 ;
     RECT  68.105 11.376 68.965 15.48 ;
     RECT  68.033 16.512 68.965 16.536 ;
     RECT  68.753 27.312 68.965 27.336 ;
     RECT  68.956 28.512 68.965 29.112 ;
     RECT  68.933 25.776 68.969 26.28 ;
     RECT  68.965 27.312 68.969 29.112 ;
     RECT  68.249 18 69.001 20.424 ;
     RECT  68.969 26.112 69.005 26.28 ;
     RECT  68.876 32.784 69.145 34.104 ;
     RECT  68.969 27.312 69.149 28.248 ;
     RECT  68.965 11.376 69.164 16.536 ;
     RECT  69.001 17.76 69.164 20.424 ;
     RECT  68.581 7.92 69.217 10.056 ;
     RECT  68.929 21.456 69.253 21.48 ;
     RECT  68.771 22.464 69.253 23.352 ;
     RECT  68.605 0.144 69.289 0.168 ;
     RECT  69.145 32.688 69.293 34.104 ;
     RECT  69.149 27.312 69.365 28.056 ;
     RECT  69.293 33.36 69.365 34.104 ;
     RECT  69.164 11.376 69.397 20.424 ;
     RECT  69.253 21.456 69.397 23.352 ;
     RECT  69.289 0.144 69.433 0.552 ;
     RECT  69.361 30.816 69.509 30.84 ;
     RECT  69.433 0.144 69.569 1.128 ;
     RECT  67.504 40.224 69.581 40.872 ;
     RECT  69.365 27.312 69.653 27.864 ;
     RECT  69.569 0.144 69.685 1.176 ;
     RECT  69.073 3.984 69.685 4.008 ;
     RECT  69.685 3.648 69.721 4.008 ;
     RECT  68.099 61.152 69.788 62.184 ;
     RECT  69.685 0.144 69.827 1.8 ;
     RECT  69.827 1.728 69.829 1.8 ;
     RECT  69.217 7.776 69.865 10.056 ;
     RECT  69.397 11.376 69.865 23.352 ;
     RECT  69.505 24.432 69.865 24.504 ;
     RECT  69.788 60.672 69.875 62.184 ;
     RECT  69.865 7.776 69.973 24.504 ;
     RECT  69.653 27.312 70.009 27.48 ;
     RECT  69.937 68.736 70.009 68.76 ;
     RECT  69.829 56.832 70.037 56.856 ;
     RECT  69.875 61.152 70.049 62.184 ;
     RECT  69.973 7.776 70.115 25.464 ;
     RECT  69.721 3.408 70.117 4.008 ;
     RECT  70.009 68.592 70.117 68.76 ;
     RECT  70.037 56.832 70.121 57.624 ;
     RECT  69.829 1.728 70.165 1.848 ;
     RECT  70.117 3.408 70.201 4.2 ;
     RECT  69.827 0.144 70.259 0.6 ;
     RECT  70.049 61.2 70.307 62.184 ;
     RECT  70.115 18.048 70.337 25.464 ;
     RECT  70.117 68.592 70.477 68.952 ;
     RECT  69.865 70.128 70.477 70.152 ;
     RECT  70.009 27.168 70.481 27.48 ;
     RECT  70.165 1.728 70.517 2.28 ;
     RECT  70.115 7.776 70.549 16.584 ;
     RECT  70.517 1.728 70.553 2.184 ;
     RECT  70.477 68.592 70.585 70.152 ;
     RECT  70.405 32.928 70.621 32.952 ;
     RECT  70.553 1.728 70.625 2.136 ;
     RECT  70.337 18.048 70.691 22.824 ;
     RECT  70.621 32.688 70.693 32.952 ;
     RECT  69.365 34.08 70.693 34.104 ;
     RECT  70.259 0.144 70.733 0.312 ;
     RECT  70.585 68.592 70.837 70.728 ;
     RECT  70.337 23.904 70.841 25.464 ;
     RECT  70.841 23.904 70.913 24.36 ;
     RECT  70.121 56.832 70.94 57.048 ;
     RECT  70.625 1.728 70.949 1.896 ;
     RECT  70.201 3.408 70.949 4.008 ;
     RECT  70.613 59.28 70.981 59.304 ;
     RECT  70.837 67.872 71.017 70.728 ;
     RECT  70.693 31.92 71.057 34.104 ;
     RECT  70.981 58.368 71.068 59.304 ;
     RECT  70.549 6.816 71.123 16.584 ;
     RECT  70.94 55.92 71.161 57.048 ;
     RECT  71.123 7.248 71.173 16.584 ;
     RECT  70.765 29.088 71.197 29.112 ;
     RECT  70.621 30.336 71.197 30.36 ;
     RECT  69.581 40.224 71.221 40.488 ;
     RECT  71.017 67.536 71.221 70.728 ;
     RECT  70.949 1.728 71.237 1.8 ;
     RECT  71.221 39.744 71.267 40.488 ;
     RECT  71.197 29.088 71.269 29.352 ;
     RECT  71.197 30.336 71.269 30.84 ;
     RECT  70.307 61.2 71.269 61.656 ;
     RECT  71.267 39.744 71.317 40.248 ;
     RECT  70.691 18.768 71.341 22.824 ;
     RECT  70.733 0.288 71.381 0.312 ;
     RECT  71.173 7.248 71.413 16.92 ;
     RECT  71.269 61.2 71.449 62.28 ;
     RECT  70.981 35.952 71.477 36.168 ;
     RECT  70.009 37.296 71.477 37.32 ;
     RECT  71.057 33.264 71.509 34.104 ;
     RECT  71.221 66.768 71.509 70.728 ;
     RECT  71.509 33.264 71.521 34.536 ;
     RECT  71.477 35.952 71.521 37.32 ;
     RECT  71.068 58.704 71.521 59.304 ;
     RECT  71.449 61.008 71.521 62.28 ;
     RECT  71.269 29.088 71.525 30.888 ;
     RECT  71.057 31.92 71.525 31.944 ;
     RECT  71.317 39.696 71.555 40.248 ;
     RECT  71.233 65.04 71.557 65.064 ;
     RECT  71.509 66.288 71.557 70.728 ;
     RECT  71.521 33.264 71.603 37.32 ;
     RECT  71.557 65.04 71.629 70.728 ;
     RECT  71.413 7.248 71.633 16.968 ;
     RECT  71.341 18.768 71.653 22.92 ;
     RECT  70.913 23.904 71.653 24.216 ;
     RECT  71.525 29.088 71.665 29.352 ;
     RECT  71.633 11.76 71.701 16.968 ;
     RECT  71.221 54.096 71.701 54.12 ;
     RECT  71.701 11.76 71.749 17.208 ;
     RECT  71.629 64.992 71.765 70.728 ;
     RECT  71.525 30.336 71.773 30.888 ;
     RECT  71.701 54.096 71.797 54.696 ;
     RECT  71.161 55.92 71.797 57.624 ;
     RECT  71.521 58.704 71.797 59.64 ;
     RECT  71.521 60.816 71.797 62.28 ;
     RECT  71.797 58.704 71.845 62.28 ;
     RECT  71.765 64.992 71.845 71.112 ;
     RECT  71.749 11.76 71.881 17.496 ;
     RECT  71.653 18.768 71.881 24.216 ;
     RECT  70.481 27.168 71.917 27.192 ;
     RECT  71.773 30.336 71.917 30.936 ;
     RECT  71.845 58.704 71.941 62.808 ;
     RECT  71.941 58.704 72.085 63.624 ;
     RECT  71.881 11.76 72.133 24.216 ;
     RECT  71.797 54.096 72.14 57.624 ;
     RECT  72.14 53.76 72.181 57.624 ;
     RECT  72.085 58.704 72.181 63.72 ;
     RECT  70.841 25.44 72.241 25.464 ;
     RECT  72.181 53.76 72.277 63.72 ;
     RECT  71.989 0.384 72.313 1.032 ;
     RECT  72.133 11.76 72.373 24.264 ;
     RECT  72.241 25.44 72.373 25.656 ;
     RECT  71.917 26.88 72.373 27.192 ;
     RECT  72.313 0.384 72.421 1.128 ;
     RECT  72.373 3.84 72.421 3.864 ;
     RECT  72.421 0.24 72.469 1.128 ;
     RECT  71.603 34.512 72.493 37.32 ;
     RECT  72.277 53.76 72.493 63.816 ;
     RECT  71.845 64.944 72.493 71.112 ;
     RECT  72.421 3.408 72.608 3.864 ;
     RECT  71.633 7.248 72.608 10.776 ;
     RECT  72.373 11.76 72.608 27.192 ;
     RECT  71.665 28.416 72.608 29.352 ;
     RECT  71.917 30.336 72.608 31.464 ;
     RECT  71.603 33.264 72.608 33.288 ;
     RECT  72.493 34.512 72.608 37.416 ;
     RECT  71.555 39.696 72.608 39.768 ;
     RECT  71.557 45.696 72.608 45.72 ;
     RECT  72.469 51.216 72.608 51.24 ;
     RECT  72.493 53.76 72.608 71.112 ;
     RECT  72.469 0.144 72.611 1.128 ;
     RECT  72.608 2.148 72.881 71.112 ;
     RECT  72.881 1.728 72.904 71.112 ;
     RECT  72.611 0.144 72.965 0.744 ;
     RECT  72.904 6.96 73.037 10.584 ;
     RECT  72.904 53.52 73.043 59.496 ;
     RECT  72.904 11.568 73.091 23.928 ;
     RECT  72.904 60.72 73.109 71.112 ;
     RECT  72.904 3.984 73.139 4.536 ;
     RECT  73.091 11.568 73.187 23.592 ;
     RECT  72.904 25.104 73.217 25.704 ;
     RECT  72.904 33.072 73.217 35.448 ;
     RECT  72.904 51.216 73.217 51.384 ;
     RECT  72.965 0.144 73.235 0.648 ;
     RECT  73.139 3.984 73.283 4.44 ;
     RECT  73.187 11.568 73.361 23.4 ;
     RECT  73.361 11.568 73.427 21.528 ;
     RECT  73.427 21.36 73.475 21.528 ;
     RECT  73.361 22.512 73.523 23.4 ;
     RECT  73.217 25.152 73.541 25.704 ;
     RECT  73.217 33.168 73.571 35.448 ;
     RECT  73.475 21.36 73.577 21.384 ;
     RECT  73.571 33.168 73.612 34.536 ;
     RECT  73.283 3.984 73.613 4.2 ;
     RECT  73.612 33.168 73.667 33.912 ;
     RECT  72.904 26.736 73.685 26.76 ;
     RECT  73.109 60.72 73.685 70.92 ;
     RECT  73.667 33.168 73.721 33.816 ;
     RECT  73.427 11.568 73.756 20.184 ;
     RECT  73.756 11.568 73.763 19.08 ;
     RECT  73.763 15.984 73.793 19.08 ;
     RECT  73.043 53.52 73.801 59.448 ;
     RECT  73.793 15.984 73.804 16.248 ;
     RECT  73.541 25.68 73.811 25.704 ;
     RECT  73.037 8.592 73.897 10.584 ;
     RECT  73.763 11.568 73.897 14.904 ;
     RECT  73.523 22.512 73.901 22.584 ;
     RECT  73.613 3.984 73.909 4.008 ;
     RECT  73.793 17.328 73.937 19.08 ;
     RECT  72.904 1.728 73.973 1.944 ;
     RECT  73.973 1.776 74.005 1.944 ;
     RECT  73.804 15.984 74.009 16.152 ;
     RECT  74.009 15.984 74.051 16.056 ;
     RECT  74.005 1.776 74.081 1.992 ;
     RECT  74.081 1.968 74.089 1.992 ;
     RECT  73.756 20.16 74.099 20.184 ;
     RECT  72.904 27.84 74.099 31.896 ;
     RECT  73.685 60.864 74.099 70.92 ;
     RECT  74.099 69.456 74.113 70.92 ;
     RECT  73.235 0.144 74.117 0.264 ;
     RECT  73.897 8.592 74.117 14.904 ;
     RECT  72.904 37.296 74.149 37.608 ;
     RECT  73.801 59.184 74.149 59.448 ;
     RECT  74.117 0.144 74.153 0.168 ;
     RECT  74.099 27.84 74.153 30.408 ;
     RECT  74.153 27.84 74.221 29.64 ;
     RECT  73.901 22.56 74.225 22.584 ;
     RECT  73.217 51.36 74.257 51.384 ;
     RECT  72.904 45.696 74.261 45.72 ;
     RECT  73.801 53.52 74.261 58.152 ;
     RECT  74.149 37.008 74.333 37.608 ;
     RECT  74.117 9.024 74.339 14.904 ;
     RECT  74.221 27.744 74.396 29.64 ;
     RECT  73.037 6.96 74.437 7.416 ;
     RECT  73.721 33.168 74.477 33.624 ;
     RECT  74.396 27.648 74.483 29.64 ;
     RECT  74.099 31.824 74.509 31.896 ;
     RECT  74.477 33.168 74.509 33.528 ;
     RECT  74.339 10.848 74.585 14.904 ;
     RECT  74.339 9.024 74.627 9.768 ;
     RECT  74.261 53.52 74.649 57.288 ;
     RECT  74.257 50.736 74.653 51.384 ;
     RECT  74.483 28.032 74.693 29.64 ;
     RECT  74.581 25.728 74.761 25.848 ;
     RECT  73.937 17.376 74.833 19.08 ;
     RECT  74.761 25.728 74.833 25.944 ;
     RECT  74.149 59.184 74.833 59.544 ;
     RECT  74.099 60.864 74.833 68.472 ;
     RECT  74.833 59.184 74.869 68.472 ;
     RECT  74.833 25.728 74.908 26.04 ;
     RECT  74.653 50.736 74.909 51.576 ;
     RECT  74.333 37.296 74.963 37.608 ;
     RECT  74.627 9.024 75.011 9.096 ;
     RECT  74.585 11.424 75.013 14.904 ;
     RECT  74.051 15.984 75.013 16.008 ;
     RECT  74.245 41.088 75.013 41.112 ;
     RECT  74.869 58.56 75.053 68.472 ;
     RECT  75.013 11.424 75.085 16.008 ;
     RECT  74.833 17.376 75.085 19.224 ;
     RECT  75.085 11.424 75.107 19.224 ;
     RECT  75.107 14.64 75.125 19.224 ;
     RECT  74.509 31.824 75.125 33.528 ;
     RECT  75.125 18 75.161 19.224 ;
     RECT  74.693 28.272 75.193 29.64 ;
     RECT  75.013 41.088 75.193 41.64 ;
     RECT  74.908 25.68 75.233 26.04 ;
     RECT  75.125 32.976 75.233 33.528 ;
     RECT  74.437 6.768 75.251 7.416 ;
     RECT  75.125 14.64 75.251 16.824 ;
     RECT  75.233 32.976 75.269 33.336 ;
     RECT  74.917 45.888 75.269 45.912 ;
     RECT  74.909 51.36 75.299 51.576 ;
     RECT  75.193 28.272 75.301 30.072 ;
     RECT  75.233 25.68 75.341 25.704 ;
     RECT  74.649 53.568 75.404 57.288 ;
     RECT  75.053 58.56 75.404 67.848 ;
     RECT  75.193 41.04 75.409 41.64 ;
     RECT  75.409 40.416 75.413 41.64 ;
     RECT  75.251 6.768 75.491 6.792 ;
     RECT  75.251 14.64 75.491 16.536 ;
     RECT  74.113 69.456 75.493 71.16 ;
     RECT  75.011 9.072 75.587 9.096 ;
     RECT  75.107 11.424 75.629 13.656 ;
     RECT  75.629 11.856 75.635 13.656 ;
     RECT  75.491 15.312 75.665 16.536 ;
     RECT  75.665 16.512 75.683 16.536 ;
     RECT  75.404 53.568 75.692 67.848 ;
     RECT  75.493 68.832 75.745 71.16 ;
     RECT  75.635 12.528 75.773 13.656 ;
     RECT  75.269 33.264 75.809 33.336 ;
     RECT  75.301 28.272 75.913 30.648 ;
     RECT  75.125 31.824 75.913 31.896 ;
     RECT  75.161 18 75.917 19.08 ;
     RECT  75.805 26.736 75.953 26.76 ;
     RECT  75.913 28.272 75.953 31.896 ;
     RECT  75.809 33.264 75.953 33.288 ;
     RECT  75.692 53.52 75.98 67.848 ;
     RECT  75.773 12.528 76.025 12.552 ;
     RECT  75.98 53.184 76.049 67.848 ;
     RECT  75.745 68.832 76.049 71.112 ;
     RECT  75.917 18 76.061 18.216 ;
     RECT  76.049 53.184 76.067 71.112 ;
     RECT  76.021 26.784 76.093 26.808 ;
     RECT  75.953 28.272 76.093 31.56 ;
     RECT  75.665 15.312 76.115 15.336 ;
     RECT  76.061 18 76.169 18.024 ;
     RECT  76.093 26.784 76.349 31.56 ;
     RECT  74.963 37.296 76.349 37.32 ;
     RECT  76.237 32.736 76.451 32.952 ;
     RECT  76.349 26.784 76.493 27.336 ;
     RECT  76.493 26.88 76.529 27.336 ;
     RECT  75.299 51.36 76.597 51.384 ;
     RECT  75.773 13.632 76.643 13.656 ;
     RECT  76.604 37.536 76.691 37.56 ;
     RECT  76.451 32.784 76.709 32.952 ;
     RECT  76.067 53.76 76.732 71.112 ;
     RECT  75.985 10.464 76.739 10.488 ;
     RECT  76.709 32.784 76.745 32.808 ;
     RECT  75.877 25.152 76.817 25.176 ;
     RECT  76.597 51.36 76.828 51.816 ;
     RECT  76.732 57.312 76.925 71.112 ;
     RECT  76.529 27.312 76.997 27.336 ;
     RECT  76.349 28.32 77.027 31.56 ;
     RECT  76.732 53.76 77.027 55.848 ;
     RECT  76.693 44.448 77.137 44.472 ;
     RECT  76.525 8.496 77.18 8.52 ;
     RECT  77.027 53.76 77.209 55.8 ;
     RECT  77.18 8.352 77.221 8.52 ;
     RECT  76.828 51.36 77.281 51.576 ;
     RECT  77.281 51.216 77.317 51.576 ;
     RECT  76.925 66 77.317 71.112 ;
     RECT  77.389 1.68 77.425 1.704 ;
     RECT  77.209 53.472 77.497 55.8 ;
     RECT  77.425 1.68 77.533 2.28 ;
     RECT  77.497 0.144 77.605 0.168 ;
     RECT  77.533 1.152 77.605 2.28 ;
     RECT  77.137 44.4 77.605 44.472 ;
     RECT  77.605 0.144 77.617 2.28 ;
     RECT  77.617 0.144 77.689 0.6 ;
     RECT  77.689 0.144 77.699 0.168 ;
     RECT  77.027 28.416 77.749 31.56 ;
     RECT  77.221 8.352 77.785 9.144 ;
     RECT  77.617 1.728 78.008 2.28 ;
     RECT  77.785 8.352 78.008 9.624 ;
     RECT  77.749 28.416 78.008 32.328 ;
     RECT  75.413 40.416 78.008 41.064 ;
     RECT  77.605 44.4 78.008 45.192 ;
     RECT  77.317 50.736 78.008 51.576 ;
     RECT  77.497 53.328 78.008 55.8 ;
     RECT  76.925 57.312 78.008 65.016 ;
     RECT  77.317 66 78.008 71.16 ;
     RECT  78.008 1.728 78.013 71.16 ;
     RECT  78.013 2.148 78.112 71.16 ;
     RECT  78.112 2.418 78.145 71.16 ;
     RECT  78.145 2.418 78.304 71.256 ;
     RECT  78.304 40.032 78.365 40.44 ;
     RECT  78.304 53.328 78.365 57.336 ;
     RECT  78.304 8.496 78.419 11.976 ;
     RECT  78.365 53.328 78.419 57.24 ;
     RECT  78.419 9.072 78.467 9.624 ;
     RECT  78.419 10.608 78.467 11.976 ;
     RECT  78.304 32.304 78.467 32.52 ;
     RECT  78.304 51.216 78.508 51.576 ;
     RECT  78.304 23.328 78.509 23.352 ;
     RECT  78.304 58.704 78.617 71.256 ;
     RECT  78.365 40.032 78.689 40.056 ;
     RECT  78.304 44.352 78.689 45.192 ;
     RECT  78.304 30.672 78.755 30.696 ;
     RECT  78.467 32.448 78.755 32.52 ;
     RECT  78.419 53.328 78.869 57.096 ;
     RECT  78.304 27.6 78.905 28.776 ;
     RECT  78.617 58.704 79.139 69.096 ;
     RECT  79.139 58.704 79.193 63.24 ;
     RECT  78.467 11.52 79.235 11.976 ;
     RECT  78.467 9.072 79.273 9.192 ;
     RECT  78.508 51.216 79.283 51.24 ;
     RECT  79.139 64.368 79.301 69.096 ;
     RECT  79.235 11.952 79.331 11.976 ;
     RECT  79.193 58.704 79.333 58.872 ;
     RECT  78.689 44.352 79.373 44.376 ;
     RECT  79.333 7.968 79.417 7.992 ;
     RECT  79.273 9.168 79.42 9.192 ;
     RECT  79.333 58.128 79.427 58.872 ;
     RECT  78.617 70.08 79.445 71.256 ;
     RECT  79.301 64.992 79.475 69.096 ;
     RECT  78.869 55.824 79.477 57.096 ;
     RECT  79.427 58.128 79.477 58.728 ;
     RECT  79.193 59.856 79.523 63.24 ;
     RECT  79.477 55.824 79.571 58.728 ;
     RECT  79.523 59.856 79.589 62.232 ;
     RECT  79.571 55.824 79.619 58.152 ;
     RECT  79.621 10.224 79.705 10.248 ;
     RECT  78.869 53.328 79.715 54.696 ;
     RECT  79.525 34.608 79.717 34.632 ;
     RECT  78.755 32.448 79.763 32.472 ;
     RECT  78.905 27.6 79.765 28.104 ;
     RECT  79.717 34.56 79.805 34.632 ;
     RECT  79.475 65.376 79.805 69.096 ;
     RECT  79.619 55.824 79.811 57.24 ;
     RECT  79.805 65.376 79.811 67.272 ;
     RECT  79.765 27.072 79.869 28.104 ;
     RECT  79.523 63.216 79.907 63.24 ;
     RECT  79.445 70.368 79.907 71.256 ;
     RECT  79.715 54.576 79.909 54.696 ;
     RECT  79.869 27.072 79.949 27.624 ;
     RECT  79.909 54.576 79.985 55.08 ;
     RECT  79.811 65.376 80.021 66.792 ;
     RECT  79.949 27.072 80.093 27.096 ;
     RECT  79.805 34.608 80.129 34.632 ;
     RECT  79.907 70.896 80.129 71.256 ;
     RECT  79.589 60.768 80.273 62.232 ;
     RECT  80.129 70.944 80.273 71.256 ;
     RECT  80.273 60.768 80.387 61.608 ;
     RECT  79.715 53.328 80.435 53.352 ;
     RECT  80.021 66.144 80.435 66.792 ;
     RECT  79.985 55.056 80.483 55.08 ;
     RECT  80.435 66.144 80.483 66.264 ;
     RECT  79.811 56.928 80.531 57.24 ;
     RECT  80.483 66.24 80.531 66.264 ;
     RECT  79.805 68.256 80.597 69.096 ;
     RECT  80.597 68.256 80.633 68.952 ;
     RECT  80.387 60.768 80.705 61.176 ;
     RECT  80.633 68.352 80.777 68.904 ;
     RECT  80.773 65.04 80.876 65.064 ;
     RECT  80.273 70.992 80.957 71.256 ;
     RECT  80.531 56.928 80.963 57.048 ;
     RECT  80.705 60.864 80.963 61.176 ;
     RECT  80.876 64.848 80.963 65.064 ;
     RECT  80.957 71.136 81.029 71.256 ;
     RECT  81.029 71.232 81.173 71.256 ;
     RECT  80.777 68.592 81.785 68.904 ;
     RECT  81.785 68.688 81.821 68.904 ;
     RECT  81.821 68.88 82.361 68.904 ;
     RECT  83.408 2.148 83.512 69.132 ;
     RECT  83.512 2.418 83.704 68.862 ;
     RECT  88.808 2.148 88.912 69.132 ;
     RECT  88.912 2.418 89.104 68.862 ;
     RECT  94.208 2.148 94.312 69.132 ;
     RECT  94.312 2.418 94.504 68.862 ;
     RECT  99.608 2.148 99.712 69.132 ;
     RECT  99.712 2.418 99.904 68.862 ;
     RECT  105.008 2.148 105.112 69.132 ;
     RECT  105.112 2.418 105.304 68.862 ;
     RECT  110.408 2.148 110.512 69.132 ;
     RECT  110.512 2.418 110.704 68.862 ;
     RECT  115.808 2.148 115.912 69.132 ;
     RECT  115.912 2.418 116.104 68.862 ;
     RECT  121.208 2.148 121.312 69.132 ;
     RECT  121.312 2.418 121.504 68.862 ;
     RECT  126.608 2.148 126.712 69.132 ;
     RECT  126.712 2.418 126.904 68.862 ;
    LAYER M5 ;
     RECT  58.32 0.016 62.904 0.085 ;
     RECT  50.256 0.016 56.856 0.133 ;
     RECT  72.528 0.016 74.04 0.133 ;
     RECT  42.288 0.016 42.648 0.179 ;
     RECT  69.456 0.016 70.968 0.179 ;
     RECT  50.256 0.133 56.904 0.181 ;
     RECT  72.48 0.133 74.04 0.229 ;
     RECT  50.256 0.181 57 0.563 ;
     RECT  58.32 0.085 63 0.563 ;
     RECT  58.32 0.563 60.024 0.611 ;
     RECT  72.432 0.229 74.04 0.709 ;
     RECT  42.336 0.179 42.648 1.139 ;
     RECT  45.36 0.016 48.792 1.139 ;
     RECT  77.52 0.016 77.976 1.715 ;
     RECT  42.384 1.139 42.648 1.763 ;
     RECT  43.632 0.016 43.704 1.763 ;
     RECT  45.408 1.139 48.792 1.763 ;
     RECT  59.904 0.611 60.024 1.763 ;
     RECT  69.504 0.179 70.968 1.763 ;
     RECT  77.712 1.715 77.976 1.763 ;
     RECT  43.68 1.763 43.704 1.859 ;
     RECT  60 1.763 60.024 1.859 ;
     RECT  77.76 1.763 77.976 1.859 ;
     RECT  42.432 1.763 42.648 1.907 ;
     RECT  69.504 1.763 70.92 1.907 ;
     RECT  77.808 1.859 77.976 1.955 ;
     RECT  61.008 0.563 63 2.003 ;
     RECT  72.384 0.709 74.04 2.003 ;
     RECT  42.432 1.907 42.552 2.051 ;
     RECT  58.32 0.611 58.92 2.051 ;
     RECT  77.904 1.955 77.976 2.137 ;
     RECT  2.4 2.137 2.52 2.151 ;
     RECT  7.8 2.137 7.92 2.151 ;
     RECT  13.2 2.137 13.32 2.151 ;
     RECT  18.6 2.137 18.72 2.151 ;
     RECT  24 2.137 24.12 2.151 ;
     RECT  29.4 2.137 29.52 2.151 ;
     RECT  34.8 2.137 34.92 2.151 ;
     RECT  40.2 2.137 40.32 2.151 ;
     RECT  67.2 2.137 67.32 2.151 ;
     RECT  77.904 2.137 78.12 2.151 ;
     RECT  83.4 2.137 83.52 2.151 ;
     RECT  88.8 2.137 88.92 2.151 ;
     RECT  94.2 2.137 94.32 2.151 ;
     RECT  99.6 2.137 99.72 2.151 ;
     RECT  105 2.137 105.12 2.151 ;
     RECT  110.4 2.137 110.52 2.151 ;
     RECT  115.8 2.137 115.92 2.151 ;
     RECT  121.2 2.137 121.32 2.151 ;
     RECT  126.6 2.137 126.72 2.151 ;
     RECT  42.528 2.051 42.552 2.291 ;
     RECT  58.32 2.051 58.68 2.291 ;
     RECT  77.904 2.151 78.312 2.291 ;
     RECT  58.464 2.291 58.68 2.867 ;
     RECT  50.304 0.563 57 3.205 ;
     RECT  50.304 3.205 57.24 3.443 ;
     RECT  58.512 2.867 58.68 3.443 ;
     RECT  61.152 2.003 63 3.443 ;
     RECT  58.656 3.443 58.68 3.731 ;
     RECT  72.384 2.003 73.896 3.875 ;
     RECT  45.408 1.763 48.744 4.019 ;
     RECT  61.152 3.443 62.568 4.019 ;
     RECT  69.504 1.907 70.824 4.019 ;
     RECT  72.6 3.875 73.896 4.019 ;
     RECT  61.632 4.019 62.52 4.115 ;
     RECT  70.128 4.019 70.152 4.211 ;
     RECT  72.6 4.019 73.56 4.211 ;
     RECT  72.6 4.211 73.272 4.451 ;
     RECT  61.632 4.115 62.328 4.499 ;
     RECT  61.632 4.499 62.112 4.547 ;
     RECT  72.6 4.451 73.128 4.547 ;
     RECT  50.688 3.443 57.24 6.181 ;
     RECT  45.6 4.019 48.744 6.371 ;
     RECT  45.6 6.371 46.92 6.419 ;
     RECT  64.08 6.229 64.104 6.661 ;
     RECT  64.08 6.661 64.344 6.709 ;
     RECT  61.8 4.547 62.112 6.805 ;
     RECT  63.408 6.709 64.344 6.805 ;
     RECT  75.456 6.757 75.48 6.805 ;
     RECT  61.8 6.805 64.632 7.189 ;
     RECT  71.088 6.805 71.112 7.237 ;
     RECT  72.6 4.547 72.912 7.237 ;
     RECT  48 6.371 48.744 7.381 ;
     RECT  50.688 6.181 57.288 7.381 ;
     RECT  58.32 6.709 58.344 7.381 ;
     RECT  59.808 6.805 59.832 7.381 ;
     RECT  61.584 7.189 64.632 7.381 ;
     RECT  71.088 7.237 72.912 7.381 ;
     RECT  45.6 6.419 46.68 7.669 ;
     RECT  71.088 7.381 73.032 7.765 ;
     RECT  48 7.381 57.288 7.813 ;
     RECT  58.32 7.381 60.12 7.813 ;
     RECT  45.36 7.669 46.68 7.861 ;
     RECT  66.048 7.621 66.072 7.909 ;
     RECT  67.2 2.151 67.512 7.909 ;
     RECT  43.344 7.957 43.368 8.149 ;
     RECT  42.912 8.149 43.368 8.341 ;
     RECT  78 2.291 78.312 8.341 ;
     RECT  48 7.813 60.12 8.485 ;
     RECT  61.584 7.381 65.016 8.485 ;
     RECT  77.232 8.341 78.312 8.485 ;
     RECT  79.344 7.957 79.368 8.485 ;
     RECT  70.128 7.765 73.032 8.821 ;
     RECT  74.592 6.805 75.48 8.821 ;
     RECT  45.36 7.861 46.824 8.869 ;
     RECT  48 8.485 65.016 8.869 ;
     RECT  68.592 7.909 68.616 9.013 ;
     RECT  70.128 8.821 75.48 9.013 ;
     RECT  68.592 9.013 75.48 9.061 ;
     RECT  77.232 8.485 79.368 9.155 ;
     RECT  77.328 9.155 79.368 9.203 ;
     RECT  44.784 8.869 65.016 9.637 ;
     RECT  66.048 7.909 67.512 9.637 ;
     RECT  42.912 8.341 43.704 9.731 ;
     RECT  44.784 9.637 67.512 10.021 ;
     RECT  44.688 10.021 67.512 10.165 ;
     RECT  68.592 9.061 75.576 10.165 ;
     RECT  77.328 9.203 79.224 10.213 ;
     RECT  77.328 10.213 79.656 10.453 ;
     RECT  42.912 9.731 43.56 10.739 ;
     RECT  42.912 10.739 42.936 11.123 ;
     RECT  44.688 10.165 75.576 11.797 ;
     RECT  44.64 11.797 75.576 11.845 ;
     RECT  44.64 11.845 75.624 12.373 ;
     RECT  44.448 12.373 75.624 13.139 ;
     RECT  44.496 13.139 75.624 13.523 ;
     RECT  76.704 10.453 79.656 13.621 ;
     RECT  44.64 13.523 75.624 14.915 ;
     RECT  48.672 14.915 75.624 15.203 ;
     RECT  50.784 15.203 75.624 15.301 ;
     RECT  76.608 13.621 79.656 15.301 ;
     RECT  50.784 15.301 79.656 15.347 ;
     RECT  48.672 15.203 49.608 15.443 ;
     RECT  43.344 11.845 43.368 15.539 ;
     RECT  48.72 15.443 49.608 16.067 ;
     RECT  44.64 14.915 47.064 16.163 ;
     RECT  50.784 15.347 68.088 16.213 ;
     RECT  50.4 16.213 68.088 16.259 ;
     RECT  50.4 16.259 51.528 16.787 ;
     RECT  69.216 15.347 79.656 16.931 ;
     RECT  52.848 16.259 68.088 17.267 ;
     RECT  52.848 17.267 63.432 17.315 ;
     RECT  69.744 16.931 79.656 17.507 ;
     RECT  64.416 17.267 68.088 18.181 ;
     RECT  50.4 16.787 51.312 18.275 ;
     RECT  52.992 17.315 63.432 18.419 ;
     RECT  64.416 18.181 68.184 18.757 ;
     RECT  61.248 18.419 63.432 18.803 ;
     RECT  64.416 18.757 68.76 18.949 ;
     RECT  70.08 17.507 79.656 18.949 ;
     RECT  44.64 16.163 46.536 19.427 ;
     RECT  52.992 18.419 60.072 19.427 ;
     RECT  61.248 18.803 63.288 19.427 ;
     RECT  50.784 18.275 51.312 19.571 ;
     RECT  44.64 19.427 45.912 20.003 ;
     RECT  52.992 19.427 54.312 20.003 ;
     RECT  61.248 19.427 63.24 20.003 ;
     RECT  52.992 20.003 53.832 20.339 ;
     RECT  55.68 19.427 60.072 20.339 ;
     RECT  52.992 20.339 53.736 20.579 ;
     RECT  55.68 20.339 57.864 20.579 ;
     RECT  59.232 20.339 60.072 20.579 ;
     RECT  45.504 20.003 45.912 20.627 ;
     RECT  61.584 20.003 63.24 20.723 ;
     RECT  51 19.571 51.312 20.725 ;
     RECT  64.416 18.949 79.656 21.109 ;
     RECT  56.4 20.579 56.808 21.155 ;
     RECT  59.232 20.579 59.64 21.155 ;
     RECT  64.32 21.109 79.656 21.157 ;
     RECT  61.8 20.723 63.24 21.251 ;
     RECT  53.712 20.579 53.736 21.683 ;
     RECT  57.84 20.579 57.864 22.835 ;
     RECT  64.224 21.157 79.656 23.363 ;
     RECT  64.224 23.363 68.76 23.555 ;
     RECT  48.72 16.067 48.744 23.699 ;
     RECT  69.984 23.363 79.656 25.475 ;
     RECT  64.224 23.555 68.424 26.579 ;
     RECT  64.224 26.579 68.184 27.347 ;
     RECT  50.88 20.725 51.312 27.635 ;
     RECT  70.08 25.475 79.656 28.069 ;
     RECT  64.224 27.347 68.088 29.797 ;
     RECT  64.224 29.797 68.904 29.987 ;
     RECT  61.8 21.251 62.112 31.045 ;
     RECT  63.216 21.251 63.24 31.045 ;
     RECT  61.8 31.045 63.24 31.907 ;
     RECT  64.224 29.987 68.088 32.773 ;
     RECT  64.224 32.773 68.952 32.915 ;
     RECT  63.216 31.907 63.24 34.115 ;
     RECT  70.08 28.069 79.8 53.317 ;
     RECT  64.224 32.915 68.088 53.603 ;
     RECT  70.08 53.317 80.424 55.045 ;
     RECT  64.224 53.603 67.704 56.243 ;
     RECT  70.08 55.045 80.472 56.917 ;
     RECT  70.08 56.917 80.952 57.059 ;
     RECT  64.224 56.243 67.608 57.299 ;
     RECT  70.08 57.059 80.52 57.635 ;
     RECT  64.224 57.299 65.4 58.645 ;
     RECT  66.576 57.299 67.608 58.645 ;
     RECT  64.224 58.645 67.608 58.739 ;
     RECT  70.656 57.635 80.52 59.075 ;
     RECT  70.656 59.075 74.088 59.315 ;
     RECT  64.224 58.739 65.064 59.891 ;
     RECT  64.224 59.891 64.536 60.467 ;
     RECT  64.512 60.467 64.536 60.515 ;
     RECT  75.12 59.075 80.52 60.853 ;
     RECT  66.048 58.739 67.608 61.141 ;
     RECT  75.12 60.853 80.952 61.187 ;
     RECT  69.84 60.661 69.864 61.379 ;
     RECT  71.232 59.315 74.088 61.525 ;
     RECT  75.12 61.187 80.52 61.525 ;
     RECT  66.048 61.141 68.424 61.619 ;
     RECT  70.272 61.525 80.52 62.195 ;
     RECT  66.048 61.619 68.088 62.771 ;
     RECT  71.232 62.195 80.52 64.837 ;
     RECT  71.232 64.837 80.952 65.075 ;
     RECT  71.232 65.075 80.52 66.275 ;
     RECT  71.232 66.275 80.424 66.803 ;
     RECT  71.28 66.803 79.896 66.899 ;
     RECT  66.048 62.771 67.608 67.237 ;
     RECT  65.952 67.237 67.608 67.331 ;
     RECT  65.952 67.331 67.512 67.765 ;
     RECT  71.616 66.899 79.896 67.811 ;
     RECT  2.4 2.151 2.712 69.129 ;
     RECT  7.8 2.151 8.112 69.129 ;
     RECT  13.2 2.151 13.512 69.129 ;
     RECT  18.6 2.151 18.912 69.129 ;
     RECT  24 2.151 24.312 69.129 ;
     RECT  29.4 2.151 29.712 69.129 ;
     RECT  34.8 2.151 35.112 69.129 ;
     RECT  40.2 2.151 40.512 69.129 ;
     RECT  45.6 20.627 45.912 69.129 ;
     RECT  56.4 21.155 56.712 69.129 ;
     RECT  61.8 31.907 62.112 69.129 ;
     RECT  65.136 67.765 67.512 69.129 ;
     RECT  83.4 2.151 83.712 69.129 ;
     RECT  88.8 2.151 89.112 69.129 ;
     RECT  94.2 2.151 94.512 69.129 ;
     RECT  99.6 2.151 99.912 69.129 ;
     RECT  105 2.151 105.312 69.129 ;
     RECT  110.4 2.151 110.712 69.129 ;
     RECT  115.8 2.151 116.112 69.129 ;
     RECT  121.2 2.151 121.512 69.129 ;
     RECT  126.6 2.151 126.912 69.129 ;
     RECT  2.4 69.129 2.52 69.143 ;
     RECT  7.8 69.129 7.92 69.143 ;
     RECT  13.2 69.129 13.32 69.143 ;
     RECT  18.6 69.129 18.72 69.143 ;
     RECT  24 69.129 24.12 69.143 ;
     RECT  29.4 69.129 29.52 69.143 ;
     RECT  34.8 69.129 34.92 69.143 ;
     RECT  40.2 69.129 40.32 69.143 ;
     RECT  45.6 69.129 45.72 69.143 ;
     RECT  51 27.635 51.312 69.143 ;
     RECT  56.4 69.129 56.52 69.143 ;
     RECT  61.8 69.129 61.92 69.143 ;
     RECT  65.136 69.129 67.32 69.143 ;
     RECT  83.4 69.129 83.52 69.143 ;
     RECT  88.8 69.129 88.92 69.143 ;
     RECT  94.2 69.129 94.32 69.143 ;
     RECT  99.6 69.129 99.72 69.143 ;
     RECT  105 69.129 105.12 69.143 ;
     RECT  110.4 69.129 110.52 69.143 ;
     RECT  115.8 69.129 115.92 69.143 ;
     RECT  121.2 69.129 121.32 69.143 ;
     RECT  126.6 69.129 126.72 69.143 ;
     RECT  71.856 67.811 79.896 69.541 ;
     RECT  71.712 69.541 79.896 70.403 ;
     RECT  71.712 70.403 79.32 70.693 ;
     RECT  65.136 69.143 66.648 71.248 ;
     RECT  71.664 70.693 79.32 71.248 ;
     RECT  57.96 0.016 58.272 0.132 ;
     RECT  42.648 0.132 43.632 1.763 ;
     RECT  48.792 0.132 50.256 0.563 ;
     RECT  56.856 0.132 58.32 0.133 ;
     RECT  56.904 0.133 58.32 0.181 ;
     RECT  70.968 0.133 72.48 0.229 ;
     RECT  57 0.181 58.32 2.291 ;
     RECT  70.968 0.229 72.432 0.709 ;
     RECT  48.792 0.563 50.304 1.763 ;
     RECT  60.024 0.563 61.008 1.859 ;
     RECT  58.92 0.611 59.904 1.763 ;
     RECT  70.968 0.709 72.384 1.763 ;
     RECT  42.648 1.763 43.68 1.859 ;
     RECT  58.92 1.763 60 1.859 ;
     RECT  70.92 1.763 72.384 1.907 ;
     RECT  57 2.291 58.464 2.867 ;
     RECT  57 2.867 58.512 3.205 ;
     RECT  57.24 3.205 58.512 3.443 ;
     RECT  57.24 3.443 58.656 3.731 ;
     RECT  46.92 6.371 48 6.419 ;
     RECT  46.68 6.419 48 7.861 ;
     RECT  57.288 6.709 58.32 7.813 ;
     RECT  62.112 6.709 63.408 6.805 ;
     RECT  58.344 6.805 59.808 7.381 ;
     RECT  71.112 6.805 72.6 7.237 ;
     RECT  60.12 7.381 61.584 8.485 ;
     RECT  65.016 7.621 66.048 9.637 ;
     RECT  66.072 7.621 67.2 7.909 ;
     RECT  46.824 7.861 48 8.869 ;
     RECT  67.512 7.909 68.592 10.165 ;
     RECT  68.616 7.909 70.128 9.013 ;
     RECT  78.312 7.957 79.344 8.485 ;
     RECT  43.704 8.869 44.784 9.731 ;
     RECT  77.232 9.155 77.328 10.453 ;
     RECT  79.224 9.203 79.368 10.213 ;
     RECT  43.56 9.731 44.784 10.021 ;
     RECT  43.56 10.021 44.688 10.739 ;
     RECT  75.576 10.453 76.704 11.845 ;
     RECT  42.936 10.739 44.688 11.123 ;
     RECT  43.344 11.123 44.688 11.797 ;
     RECT  43.344 11.797 44.64 11.845 ;
     RECT  43.368 11.845 44.64 12.373 ;
     RECT  75.624 11.845 76.704 13.621 ;
     RECT  43.368 12.373 44.448 13.139 ;
     RECT  43.368 13.139 44.496 13.523 ;
     RECT  43.368 13.523 44.64 15.539 ;
     RECT  75.624 13.621 76.608 15.301 ;
     RECT  49.608 15.203 50.784 16.067 ;
     RECT  68.088 15.347 69.216 16.931 ;
     RECT  50.4 16.067 50.784 16.213 ;
     RECT  51.528 16.259 52.848 16.787 ;
     RECT  68.088 16.931 68.184 18.181 ;
     RECT  63.432 17.267 64.416 18.803 ;
     RECT  69.744 17.507 70.08 18.757 ;
     RECT  60.072 18.419 61.248 20.003 ;
     RECT  68.76 18.757 70.08 18.949 ;
     RECT  63.288 18.803 64.416 19.427 ;
     RECT  54.312 19.427 55.68 20.003 ;
     RECT  63.24 19.427 64.416 21.109 ;
     RECT  50.88 19.571 51 20.725 ;
     RECT  60.072 20.003 61.584 20.579 ;
     RECT  57.864 20.339 59.232 21.155 ;
     RECT  56.808 20.579 57.84 21.155 ;
     RECT  63.24 21.109 64.32 21.157 ;
     RECT  56.712 21.155 57.84 22.835 ;
     RECT  63.24 21.157 64.224 34.115 ;
     RECT  62.112 21.251 63.216 31.045 ;
     RECT  68.76 23.363 69.984 23.555 ;
     RECT  68.904 29.797 70.08 29.987 ;
     RECT  62.112 31.907 63.216 34.115 ;
     RECT  68.952 32.773 70.08 32.915 ;
     RECT  65.4 57.299 66.576 58.645 ;
     RECT  65.064 58.739 66.048 59.891 ;
     RECT  74.088 59.075 75.12 61.525 ;
     RECT  70.656 59.315 71.232 60.661 ;
     RECT  64.536 59.891 66.048 60.515 ;
     RECT  69.864 60.661 71.232 61.379 ;
     RECT  68.424 61.141 69.84 61.379 ;
     RECT  70.272 61.379 71.232 61.525 ;
  END
END ot_hgi_qdq_fr_one_payload_face
END LIBRARY
